VERSION 5.7 ;
  NOWIREEXTENSIONATPIN ON ;
  DIVIDERCHAR "/" ;
  BUSBITCHARS "[]" ;
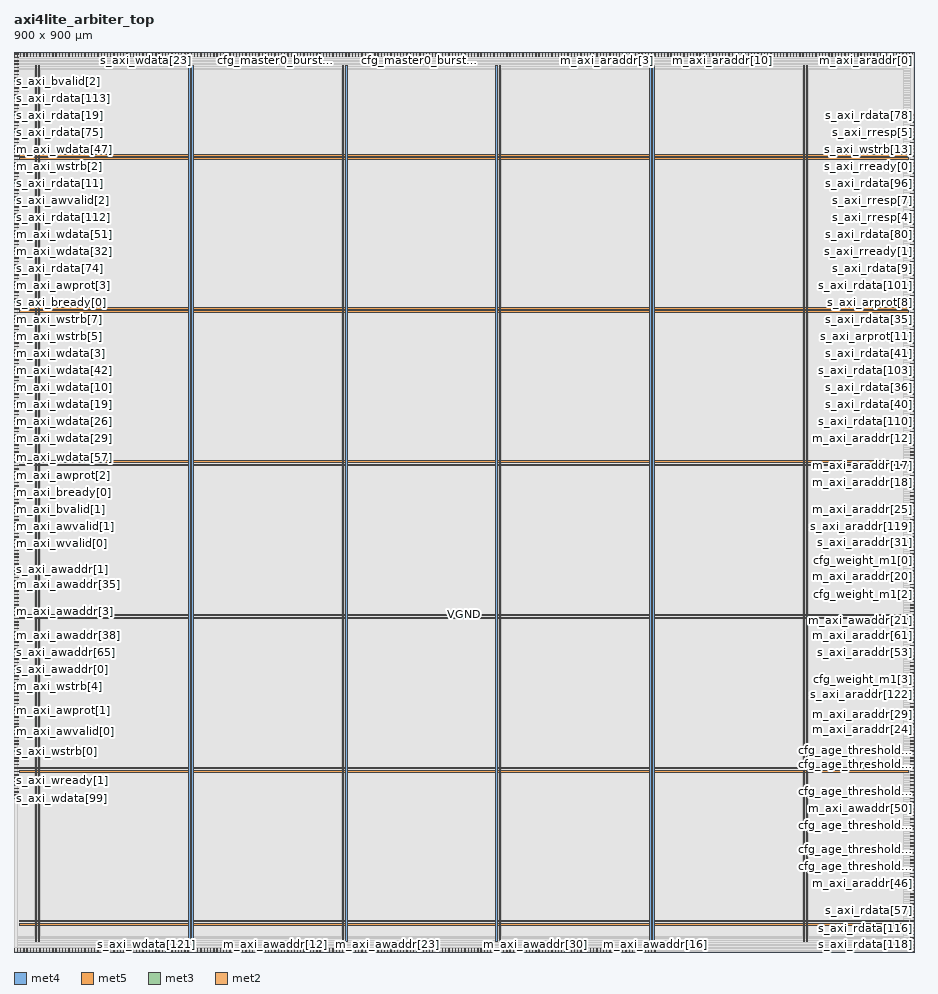
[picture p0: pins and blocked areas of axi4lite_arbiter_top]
MACRO axi4lite_arbiter_top
  CLASS BLOCK ;
  FOREIGN axi4lite_arbiter_top ;
  ORIGIN 0.000 0.000 ;
  SIZE 900.000 BY 900.000 ;
  PIN VGND
    DIRECTION INOUT ;
    USE GROUND ;
    PORT
      LAYER met4 ;
        RECT 24.340 10.640 25.940 886.960 ;
    END
    PORT
      LAYER met4 ;
        RECT 177.940 10.640 179.540 886.960 ;
    END
    PORT
      LAYER met4 ;
        RECT 331.540 10.640 333.140 886.960 ;
    END
    PORT
      LAYER met4 ;
        RECT 485.140 10.640 486.740 886.960 ;
    END
    PORT
      LAYER met4 ;
        RECT 638.740 10.640 640.340 886.960 ;
    END
    PORT
      LAYER met4 ;
        RECT 792.340 10.640 793.940 886.960 ;
    END
    PORT
      LAYER met5 ;
        RECT 5.280 30.030 894.480 31.630 ;
    END
    PORT
      LAYER met5 ;
        RECT 5.280 183.210 894.480 184.810 ;
    END
    PORT
      LAYER met5 ;
        RECT 5.280 336.390 894.480 337.990 ;
    END
    PORT
      LAYER met5 ;
        RECT 5.280 489.570 894.480 491.170 ;
    END
    PORT
      LAYER met5 ;
        RECT 5.280 642.750 894.480 644.350 ;
    END
    PORT
      LAYER met5 ;
        RECT 5.280 795.930 894.480 797.530 ;
    END
  END VGND
  PIN VPWR
    DIRECTION INOUT ;
    USE POWER ;
    PORT
      LAYER met4 ;
        RECT 21.040 10.640 22.640 886.960 ;
    END
    PORT
      LAYER met4 ;
        RECT 174.640 10.640 176.240 886.960 ;
    END
    PORT
      LAYER met4 ;
        RECT 328.240 10.640 329.840 886.960 ;
    END
    PORT
      LAYER met4 ;
        RECT 481.840 10.640 483.440 886.960 ;
    END
    PORT
      LAYER met4 ;
        RECT 635.440 10.640 637.040 886.960 ;
    END
    PORT
      LAYER met4 ;
        RECT 789.040 10.640 790.640 886.960 ;
    END
    PORT
      LAYER met5 ;
        RECT 5.280 26.730 894.480 28.330 ;
    END
    PORT
      LAYER met5 ;
        RECT 5.280 179.910 894.480 181.510 ;
    END
    PORT
      LAYER met5 ;
        RECT 5.280 333.090 894.480 334.690 ;
    END
    PORT
      LAYER met5 ;
        RECT 5.280 486.270 894.480 487.870 ;
    END
    PORT
      LAYER met5 ;
        RECT 5.280 639.450 894.480 641.050 ;
    END
    PORT
      LAYER met5 ;
        RECT 5.280 792.630 894.480 794.230 ;
    END
  END VPWR
  PIN aclk
    DIRECTION INPUT ;
    USE SIGNAL ;
    ANTENNAGATEAREA 0.852000 ;
    ANTENNADIFFAREA 0.869400 ;
    PORT
      LAYER met3 ;
        RECT 896.000 6.840 900.000 7.440 ;
    END
  END aclk
  PIN aresetn
    DIRECTION INPUT ;
    USE SIGNAL ;
    ANTENNAGATEAREA 0.990000 ;
    PORT
      LAYER met3 ;
        RECT 896.000 37.440 900.000 38.040 ;
    END
  END aresetn
  PIN cfg_age_threshold[0]
    DIRECTION INPUT ;
    USE SIGNAL ;
    ANTENNAGATEAREA 0.213000 ;
    PORT
      LAYER met3 ;
        RECT 896.000 85.040 900.000 85.640 ;
    END
  END cfg_age_threshold[0]
  PIN cfg_age_threshold[1]
    DIRECTION INPUT ;
    USE SIGNAL ;
    ANTENNAGATEAREA 0.159000 ;
    PORT
      LAYER met3 ;
        RECT 896.000 187.040 900.000 187.640 ;
    END
  END cfg_age_threshold[1]
  PIN cfg_age_threshold[2]
    DIRECTION INPUT ;
    USE SIGNAL ;
    ANTENNAGATEAREA 0.213000 ;
    PORT
      LAYER met3 ;
        RECT 896.000 193.840 900.000 194.440 ;
    END
  END cfg_age_threshold[2]
  PIN cfg_age_threshold[3]
    DIRECTION INPUT ;
    USE SIGNAL ;
    ANTENNAGATEAREA 0.247500 ;
    PORT
      LAYER met3 ;
        RECT 896.000 125.840 900.000 126.440 ;
    END
  END cfg_age_threshold[3]
  PIN cfg_age_threshold[4]
    DIRECTION INPUT ;
    USE SIGNAL ;
    ANTENNAGATEAREA 0.213000 ;
    PORT
      LAYER met3 ;
        RECT 896.000 159.840 900.000 160.440 ;
    END
  END cfg_age_threshold[4]
  PIN cfg_age_threshold[5]
    DIRECTION INPUT ;
    USE SIGNAL ;
    ANTENNAGATEAREA 0.247500 ;
    PORT
      LAYER met3 ;
        RECT 896.000 102.040 900.000 102.640 ;
    END
  END cfg_age_threshold[5]
  PIN cfg_age_threshold[6]
    DIRECTION INPUT ;
    USE SIGNAL ;
    ANTENNAGATEAREA 0.213000 ;
    PORT
      LAYER met3 ;
        RECT 896.000 173.440 900.000 174.040 ;
    END
  END cfg_age_threshold[6]
  PIN cfg_age_threshold[7]
    DIRECTION INPUT ;
    USE SIGNAL ;
    ANTENNAGATEAREA 0.213000 ;
    PORT
      LAYER met3 ;
        RECT 896.000 234.640 900.000 235.240 ;
    END
  END cfg_age_threshold[7]
  PIN cfg_master0_burst_limit[0]
    DIRECTION INPUT ;
    USE SIGNAL ;
    ANTENNAGATEAREA 0.247500 ;
    PORT
      LAYER met2 ;
        RECT 405.810 896.000 406.090 900.000 ;
    END
  END cfg_master0_burst_limit[0]
  PIN cfg_master0_burst_limit[1]
    DIRECTION INPUT ;
    USE SIGNAL ;
    ANTENNAGATEAREA 0.495000 ;
    PORT
      LAYER met2 ;
        RECT 260.910 896.000 261.190 900.000 ;
    END
  END cfg_master0_burst_limit[1]
  PIN cfg_master0_burst_limit[2]
    DIRECTION INPUT ;
    USE SIGNAL ;
    ANTENNAGATEAREA 0.426000 ;
    PORT
      LAYER met2 ;
        RECT 428.350 896.000 428.630 900.000 ;
    END
  END cfg_master0_burst_limit[2]
  PIN cfg_master0_burst_limit[3]
    DIRECTION INPUT ;
    USE SIGNAL ;
    ANTENNAGATEAREA 0.426000 ;
    PORT
      LAYER met2 ;
        RECT 318.870 896.000 319.150 900.000 ;
    END
  END cfg_master0_burst_limit[3]
  PIN cfg_master0_burst_limit[4]
    DIRECTION INPUT ;
    USE SIGNAL ;
    ANTENNAGATEAREA 0.247500 ;
    PORT
      LAYER met2 ;
        RECT 476.650 896.000 476.930 900.000 ;
    END
  END cfg_master0_burst_limit[4]
  PIN cfg_master0_burst_limit[5]
    DIRECTION INPUT ;
    USE SIGNAL ;
    ANTENNAGATEAREA 0.495000 ;
    PORT
      LAYER met2 ;
        RECT 309.210 896.000 309.490 900.000 ;
    END
  END cfg_master0_burst_limit[5]
  PIN cfg_master0_burst_limit[6]
    DIRECTION INPUT ;
    USE SIGNAL ;
    ANTENNAGATEAREA 0.426000 ;
    PORT
      LAYER met2 ;
        RECT 463.770 896.000 464.050 900.000 ;
    END
  END cfg_master0_burst_limit[6]
  PIN cfg_master0_burst_limit[7]
    DIRECTION INPUT ;
    USE SIGNAL ;
    ANTENNAGATEAREA 0.426000 ;
    PORT
      LAYER met2 ;
        RECT 360.730 896.000 361.010 900.000 ;
    END
  END cfg_master0_burst_limit[7]
  PIN cfg_master0_priority
    DIRECTION INPUT ;
    USE SIGNAL ;
    ANTENNAGATEAREA 0.495000 ;
    PORT
      LAYER met2 ;
        RECT 264.130 896.000 264.410 900.000 ;
    END
  END cfg_master0_priority
  PIN cfg_weight_m0[0]
    DIRECTION INPUT ;
    USE SIGNAL ;
    PORT
      LAYER met2 ;
        RECT 0.090 0.000 0.370 4.000 ;
    END
  END cfg_weight_m0[0]
  PIN cfg_weight_m0[1]
    DIRECTION INPUT ;
    USE SIGNAL ;
    PORT
      LAYER met2 ;
        RECT 3.310 0.000 3.590 4.000 ;
    END
  END cfg_weight_m0[1]
  PIN cfg_weight_m0[2]
    DIRECTION INPUT ;
    USE SIGNAL ;
    PORT
      LAYER met2 ;
        RECT 6.530 0.000 6.810 4.000 ;
    END
  END cfg_weight_m0[2]
  PIN cfg_weight_m0[3]
    DIRECTION INPUT ;
    USE SIGNAL ;
    PORT
      LAYER met2 ;
        RECT 9.750 0.000 10.030 4.000 ;
    END
  END cfg_weight_m0[3]
  PIN cfg_weight_m1[0]
    DIRECTION INPUT ;
    USE SIGNAL ;
    ANTENNAGATEAREA 0.126000 ;
    PORT
      LAYER met3 ;
        RECT 896.000 391.040 900.000 391.640 ;
    END
  END cfg_weight_m1[0]
  PIN cfg_weight_m1[1]
    DIRECTION INPUT ;
    USE SIGNAL ;
    ANTENNAGATEAREA 0.126000 ;
    PORT
      LAYER met3 ;
        RECT 896.000 370.640 900.000 371.240 ;
    END
  END cfg_weight_m1[1]
  PIN cfg_weight_m1[2]
    DIRECTION INPUT ;
    USE SIGNAL ;
    ANTENNAGATEAREA 0.126000 ;
    PORT
      LAYER met3 ;
        RECT 896.000 357.040 900.000 357.640 ;
    END
  END cfg_weight_m1[2]
  PIN cfg_weight_m1[3]
    DIRECTION INPUT ;
    USE SIGNAL ;
    ANTENNAGATEAREA 0.126000 ;
    PORT
      LAYER met3 ;
        RECT 896.000 272.040 900.000 272.640 ;
    END
  END cfg_weight_m1[3]
  PIN cfg_weight_m2[0]
    DIRECTION INPUT ;
    USE SIGNAL ;
    ANTENNAGATEAREA 0.426000 ;
    PORT
      LAYER met2 ;
        RECT 386.490 896.000 386.770 900.000 ;
    END
  END cfg_weight_m2[0]
  PIN cfg_weight_m2[1]
    DIRECTION INPUT ;
    USE SIGNAL ;
    ANTENNAGATEAREA 0.426000 ;
    PORT
      LAYER met2 ;
        RECT 447.670 896.000 447.950 900.000 ;
    END
  END cfg_weight_m2[1]
  PIN cfg_weight_m2[2]
    DIRECTION INPUT ;
    USE SIGNAL ;
    ANTENNAGATEAREA 0.495000 ;
    PORT
      LAYER met2 ;
        RECT 331.750 896.000 332.030 900.000 ;
    END
  END cfg_weight_m2[2]
  PIN cfg_weight_m2[3]
    DIRECTION INPUT ;
    USE SIGNAL ;
    ANTENNAGATEAREA 0.426000 ;
    PORT
      LAYER met2 ;
        RECT 457.330 896.000 457.610 900.000 ;
    END
  END cfg_weight_m2[3]
  PIN cfg_weight_m3[0]
    DIRECTION INPUT ;
    USE SIGNAL ;
    ANTENNAGATEAREA 0.213000 ;
    PORT
      LAYER met3 ;
        RECT 896.000 54.440 900.000 55.040 ;
    END
  END cfg_weight_m3[0]
  PIN cfg_weight_m3[1]
    DIRECTION INPUT ;
    USE SIGNAL ;
    ANTENNAGATEAREA 0.213000 ;
    PORT
      LAYER met3 ;
        RECT 896.000 27.240 900.000 27.840 ;
    END
  END cfg_weight_m3[1]
  PIN cfg_weight_m3[2]
    DIRECTION INPUT ;
    USE SIGNAL ;
    ANTENNAGATEAREA 0.213000 ;
    PORT
      LAYER met3 ;
        RECT 896.000 91.840 900.000 92.440 ;
    END
  END cfg_weight_m3[2]
  PIN cfg_weight_m3[3]
    DIRECTION INPUT ;
    USE SIGNAL ;
    ANTENNAGATEAREA 0.213000 ;
    PORT
      LAYER met3 ;
        RECT 896.000 404.640 900.000 405.240 ;
    END
  END cfg_weight_m3[3]
  PIN m_axi_araddr[0]
    DIRECTION OUTPUT ;
    USE SIGNAL ;
    ANTENNADIFFAREA 0.340600 ;
    PORT
      LAYER met2 ;
        RECT 882.370 896.000 882.650 900.000 ;
    END
  END m_axi_araddr[0]
  PIN m_axi_araddr[10]
    DIRECTION OUTPUT ;
    USE SIGNAL ;
    ANTENNADIFFAREA 0.340600 ;
    PORT
      LAYER met2 ;
        RECT 708.490 896.000 708.770 900.000 ;
    END
  END m_axi_araddr[10]
  PIN m_axi_araddr[11]
    DIRECTION OUTPUT ;
    USE SIGNAL ;
    ANTENNADIFFAREA 0.340600 ;
    PORT
      LAYER met3 ;
        RECT 896.000 360.440 900.000 361.040 ;
    END
  END m_axi_araddr[11]
  PIN m_axi_araddr[12]
    DIRECTION OUTPUT ;
    USE SIGNAL ;
    ANTENNADIFFAREA 0.340600 ;
    PORT
      LAYER met3 ;
        RECT 896.000 513.440 900.000 514.040 ;
    END
  END m_axi_araddr[12]
  PIN m_axi_araddr[13]
    DIRECTION OUTPUT ;
    USE SIGNAL ;
    ANTENNADIFFAREA 0.340600 ;
    PORT
      LAYER met2 ;
        RECT 714.930 896.000 715.210 900.000 ;
    END
  END m_axi_araddr[13]
  PIN m_axi_araddr[14]
    DIRECTION OUTPUT ;
    USE SIGNAL ;
    ANTENNADIFFAREA 0.340600 ;
    PORT
      LAYER met3 ;
        RECT 896.000 397.840 900.000 398.440 ;
    END
  END m_axi_araddr[14]
  PIN m_axi_araddr[15]
    DIRECTION OUTPUT ;
    USE SIGNAL ;
    ANTENNADIFFAREA 0.340600 ;
    PORT
      LAYER met3 ;
        RECT 896.000 170.040 900.000 170.640 ;
    END
  END m_axi_araddr[15]
  PIN m_axi_araddr[16]
    DIRECTION OUTPUT ;
    USE SIGNAL ;
    ANTENNADIFFAREA 0.340600 ;
    PORT
      LAYER met2 ;
        RECT 843.730 896.000 844.010 900.000 ;
    END
  END m_axi_araddr[16]
  PIN m_axi_araddr[17]
    DIRECTION OUTPUT ;
    USE SIGNAL ;
    ANTENNADIFFAREA 0.340600 ;
    PORT
      LAYER met3 ;
        RECT 896.000 486.240 900.000 486.840 ;
    END
  END m_axi_araddr[17]
  PIN m_axi_araddr[18]
    DIRECTION OUTPUT ;
    USE SIGNAL ;
    ANTENNADIFFAREA 0.340600 ;
    PORT
      LAYER met3 ;
        RECT 896.000 469.240 900.000 469.840 ;
    END
  END m_axi_araddr[18]
  PIN m_axi_araddr[19]
    DIRECTION OUTPUT ;
    USE SIGNAL ;
    ANTENNADIFFAREA 0.340600 ;
    PORT
      LAYER met3 ;
        RECT 896.000 268.640 900.000 269.240 ;
    END
  END m_axi_araddr[19]
  PIN m_axi_araddr[1]
    DIRECTION OUTPUT ;
    USE SIGNAL ;
    ANTENNADIFFAREA 0.340600 ;
    PORT
      LAYER met2 ;
        RECT 553.930 896.000 554.210 900.000 ;
    END
  END m_axi_araddr[1]
  PIN m_axi_araddr[20]
    DIRECTION OUTPUT ;
    USE SIGNAL ;
    ANTENNADIFFAREA 0.340600 ;
    PORT
      LAYER met3 ;
        RECT 896.000 367.240 900.000 367.840 ;
    END
  END m_axi_araddr[20]
  PIN m_axi_araddr[21]
    DIRECTION OUTPUT ;
    USE SIGNAL ;
    ANTENNADIFFAREA 0.340600 ;
    PORT
      LAYER met3 ;
        RECT 896.000 462.440 900.000 463.040 ;
    END
  END m_axi_araddr[21]
  PIN m_axi_araddr[22]
    DIRECTION OUTPUT ;
    USE SIGNAL ;
    ANTENNADIFFAREA 0.340600 ;
    PORT
      LAYER met3 ;
        RECT 896.000 455.640 900.000 456.240 ;
    END
  END m_axi_araddr[22]
  PIN m_axi_araddr[23]
    DIRECTION OUTPUT ;
    USE SIGNAL ;
    ANTENNADIFFAREA 0.340600 ;
    PORT
      LAYER met3 ;
        RECT 896.000 132.640 900.000 133.240 ;
    END
  END m_axi_araddr[23]
  PIN m_axi_araddr[24]
    DIRECTION OUTPUT ;
    USE SIGNAL ;
    ANTENNADIFFAREA 0.340600 ;
    PORT
      LAYER met3 ;
        RECT 896.000 214.240 900.000 214.840 ;
    END
  END m_axi_araddr[24]
  PIN m_axi_araddr[25]
    DIRECTION OUTPUT ;
    USE SIGNAL ;
    ANTENNADIFFAREA 0.340600 ;
    PORT
      LAYER met3 ;
        RECT 896.000 442.040 900.000 442.640 ;
    END
  END m_axi_araddr[25]
  PIN m_axi_araddr[26]
    DIRECTION OUTPUT ;
    USE SIGNAL ;
    ANTENNADIFFAREA 0.340600 ;
    PORT
      LAYER met3 ;
        RECT 896.000 129.240 900.000 129.840 ;
    END
  END m_axi_araddr[26]
  PIN m_axi_araddr[27]
    DIRECTION OUTPUT ;
    USE SIGNAL ;
    ANTENNADIFFAREA 0.340600 ;
    PORT
      LAYER met3 ;
        RECT 896.000 319.640 900.000 320.240 ;
    END
  END m_axi_araddr[27]
  PIN m_axi_araddr[28]
    DIRECTION OUTPUT ;
    USE SIGNAL ;
    ANTENNADIFFAREA 0.340600 ;
    PORT
      LAYER met3 ;
        RECT 896.000 476.040 900.000 476.640 ;
    END
  END m_axi_araddr[28]
  PIN m_axi_araddr[29]
    DIRECTION OUTPUT ;
    USE SIGNAL ;
    ANTENNADIFFAREA 0.340600 ;
    PORT
      LAYER met3 ;
        RECT 896.000 244.840 900.000 245.440 ;
    END
  END m_axi_araddr[29]
  PIN m_axi_araddr[2]
    DIRECTION OUTPUT ;
    USE SIGNAL ;
    ANTENNADIFFAREA 0.340600 ;
    PORT
      LAYER met2 ;
        RECT 454.110 896.000 454.390 900.000 ;
    END
  END m_axi_araddr[2]
  PIN m_axi_araddr[30]
    DIRECTION OUTPUT ;
    USE SIGNAL ;
    ANTENNADIFFAREA 0.340600 ;
    PORT
      LAYER met2 ;
        RECT 811.530 896.000 811.810 900.000 ;
    END
  END m_axi_araddr[30]
  PIN m_axi_araddr[31]
    DIRECTION OUTPUT ;
    USE SIGNAL ;
    ANTENNADIFFAREA 0.340600 ;
    PORT
      LAYER met3 ;
        RECT 896.000 394.440 900.000 395.040 ;
    END
  END m_axi_araddr[31]
  PIN m_axi_araddr[32]
    DIRECTION OUTPUT ;
    USE SIGNAL ;
    ANTENNADIFFAREA 0.340600 ;
    PORT
      LAYER met2 ;
        RECT 846.950 896.000 847.230 900.000 ;
    END
  END m_axi_araddr[32]
  PIN m_axi_araddr[33]
    DIRECTION OUTPUT ;
    USE SIGNAL ;
    ANTENNADIFFAREA 0.340600 ;
    PORT
      LAYER met2 ;
        RECT 312.430 896.000 312.710 900.000 ;
    END
  END m_axi_araddr[33]
  PIN m_axi_araddr[34]
    DIRECTION OUTPUT ;
    USE SIGNAL ;
    ANTENNADIFFAREA 0.340600 ;
    PORT
      LAYER met2 ;
        RECT 267.350 896.000 267.630 900.000 ;
    END
  END m_axi_araddr[34]
  PIN m_axi_araddr[35]
    DIRECTION OUTPUT ;
    USE SIGNAL ;
    ANTENNADIFFAREA 0.340600 ;
    PORT
      LAYER met2 ;
        RECT 859.830 896.000 860.110 900.000 ;
    END
  END m_axi_araddr[35]
  PIN m_axi_araddr[36]
    DIRECTION OUTPUT ;
    USE SIGNAL ;
    ANTENNADIFFAREA 0.340600 ;
    PORT
      LAYER met2 ;
        RECT 627.990 896.000 628.270 900.000 ;
    END
  END m_axi_araddr[36]
  PIN m_axi_araddr[37]
    DIRECTION OUTPUT ;
    USE SIGNAL ;
    ANTENNADIFFAREA 0.340600 ;
    PORT
      LAYER met2 ;
        RECT 866.270 896.000 866.550 900.000 ;
    END
  END m_axi_araddr[37]
  PIN m_axi_araddr[38]
    DIRECTION OUTPUT ;
    USE SIGNAL ;
    ANTENNADIFFAREA 0.340600 ;
    PORT
      LAYER met2 ;
        RECT 669.850 896.000 670.130 900.000 ;
    END
  END m_axi_araddr[38]
  PIN m_axi_araddr[39]
    DIRECTION OUTPUT ;
    USE SIGNAL ;
    ANTENNADIFFAREA 0.340600 ;
    PORT
      LAYER met2 ;
        RECT 785.770 896.000 786.050 900.000 ;
    END
  END m_axi_araddr[39]
  PIN m_axi_araddr[3]
    DIRECTION OUTPUT ;
    USE SIGNAL ;
    ANTENNADIFFAREA 0.340600 ;
    PORT
      LAYER met2 ;
        RECT 592.570 896.000 592.850 900.000 ;
    END
  END m_axi_araddr[3]
  PIN m_axi_araddr[40]
    DIRECTION OUTPUT ;
    USE SIGNAL ;
    ANTENNADIFFAREA 0.340600 ;
    PORT
      LAYER met3 ;
        RECT 896.000 663.040 900.000 663.640 ;
    END
  END m_axi_araddr[40]
  PIN m_axi_araddr[41]
    DIRECTION OUTPUT ;
    USE SIGNAL ;
    ANTENNADIFFAREA 0.340600 ;
    PORT
      LAYER met2 ;
        RECT 644.090 896.000 644.370 900.000 ;
    END
  END m_axi_araddr[41]
  PIN m_axi_araddr[42]
    DIRECTION OUTPUT ;
    USE SIGNAL ;
    ANTENNADIFFAREA 0.340600 ;
    PORT
      LAYER met2 ;
        RECT 631.210 896.000 631.490 900.000 ;
    END
  END m_axi_araddr[42]
  PIN m_axi_araddr[43]
    DIRECTION OUTPUT ;
    USE SIGNAL ;
    ANTENNADIFFAREA 0.340600 ;
    PORT
      LAYER met3 ;
        RECT 896.000 88.440 900.000 89.040 ;
    END
  END m_axi_araddr[43]
  PIN m_axi_araddr[44]
    DIRECTION OUTPUT ;
    USE SIGNAL ;
    ANTENNADIFFAREA 0.340600 ;
    PORT
      LAYER met3 ;
        RECT 896.000 23.840 900.000 24.440 ;
    END
  END m_axi_araddr[44]
  PIN m_axi_araddr[45]
    DIRECTION OUTPUT ;
    USE SIGNAL ;
    ANTENNADIFFAREA 0.340600 ;
    PORT
      LAYER met2 ;
        RECT 792.210 896.000 792.490 900.000 ;
    END
  END m_axi_araddr[45]
  PIN m_axi_araddr[46]
    DIRECTION OUTPUT ;
    USE SIGNAL ;
    ANTENNADIFFAREA 0.340600 ;
    PORT
      LAYER met3 ;
        RECT 896.000 68.040 900.000 68.640 ;
    END
  END m_axi_araddr[46]
  PIN m_axi_araddr[47]
    DIRECTION OUTPUT ;
    USE SIGNAL ;
    ANTENNADIFFAREA 0.340600 ;
    PORT
      LAYER met3 ;
        RECT 896.000 190.440 900.000 191.040 ;
    END
  END m_axi_araddr[47]
  PIN m_axi_araddr[48]
    DIRECTION OUTPUT ;
    USE SIGNAL ;
    ANTENNADIFFAREA 0.340600 ;
    PORT
      LAYER met2 ;
        RECT 747.130 896.000 747.410 900.000 ;
    END
  END m_axi_araddr[48]
  PIN m_axi_araddr[49]
    DIRECTION OUTPUT ;
    USE SIGNAL ;
    ANTENNADIFFAREA 0.340600 ;
    PORT
      LAYER met3 ;
        RECT 896.000 489.640 900.000 490.240 ;
    END
  END m_axi_araddr[49]
  PIN m_axi_araddr[4]
    DIRECTION OUTPUT ;
    USE SIGNAL ;
    ANTENNADIFFAREA 0.340600 ;
    PORT
      LAYER met2 ;
        RECT 624.770 896.000 625.050 900.000 ;
    END
  END m_axi_araddr[4]
  PIN m_axi_araddr[50]
    DIRECTION OUTPUT ;
    USE SIGNAL ;
    ANTENNADIFFAREA 0.340600 ;
    PORT
      LAYER met3 ;
        RECT 896.000 472.640 900.000 473.240 ;
    END
  END m_axi_araddr[50]
  PIN m_axi_araddr[51]
    DIRECTION OUTPUT ;
    USE SIGNAL ;
    ANTENNADIFFAREA 0.340600 ;
    PORT
      LAYER met3 ;
        RECT 896.000 479.440 900.000 480.040 ;
    END
  END m_axi_araddr[51]
  PIN m_axi_araddr[52]
    DIRECTION OUTPUT ;
    USE SIGNAL ;
    ANTENNADIFFAREA 0.340600 ;
    PORT
      LAYER met3 ;
        RECT 896.000 448.840 900.000 449.440 ;
    END
  END m_axi_araddr[52]
  PIN m_axi_araddr[53]
    DIRECTION OUTPUT ;
    USE SIGNAL ;
    ANTENNADIFFAREA 0.340600 ;
    PORT
      LAYER met3 ;
        RECT 896.000 459.040 900.000 459.640 ;
    END
  END m_axi_araddr[53]
  PIN m_axi_araddr[54]
    DIRECTION OUTPUT ;
    USE SIGNAL ;
    ANTENNADIFFAREA 0.340600 ;
    PORT
      LAYER met3 ;
        RECT 896.000 465.840 900.000 466.440 ;
    END
  END m_axi_araddr[54]
  PIN m_axi_araddr[55]
    DIRECTION OUTPUT ;
    USE SIGNAL ;
    ANTENNADIFFAREA 0.340600 ;
    PORT
      LAYER met3 ;
        RECT 896.000 197.240 900.000 197.840 ;
    END
  END m_axi_araddr[55]
  PIN m_axi_araddr[56]
    DIRECTION OUTPUT ;
    USE SIGNAL ;
    ANTENNADIFFAREA 0.340600 ;
    PORT
      LAYER met3 ;
        RECT 896.000 452.240 900.000 452.840 ;
    END
  END m_axi_araddr[56]
  PIN m_axi_araddr[57]
    DIRECTION OUTPUT ;
    USE SIGNAL ;
    ANTENNADIFFAREA 0.340600 ;
    PORT
      LAYER met3 ;
        RECT 896.000 445.440 900.000 446.040 ;
    END
  END m_axi_araddr[57]
  PIN m_axi_araddr[58]
    DIRECTION OUTPUT ;
    USE SIGNAL ;
    ANTENNADIFFAREA 0.340600 ;
    PORT
      LAYER met3 ;
        RECT 896.000 261.840 900.000 262.440 ;
    END
  END m_axi_araddr[58]
  PIN m_axi_araddr[59]
    DIRECTION OUTPUT ;
    USE SIGNAL ;
    ANTENNADIFFAREA 0.340600 ;
    PORT
      LAYER met3 ;
        RECT 896.000 295.840 900.000 296.440 ;
    END
  END m_axi_araddr[59]
  PIN m_axi_araddr[5]
    DIRECTION OUTPUT ;
    USE SIGNAL ;
    ANTENNADIFFAREA 0.340600 ;
    PORT
      LAYER met2 ;
        RECT 737.470 896.000 737.750 900.000 ;
    END
  END m_axi_araddr[5]
  PIN m_axi_araddr[60]
    DIRECTION OUTPUT ;
    USE SIGNAL ;
    ANTENNADIFFAREA 0.340600 ;
    PORT
      LAYER met3 ;
        RECT 896.000 482.840 900.000 483.440 ;
    END
  END m_axi_araddr[60]
  PIN m_axi_araddr[61]
    DIRECTION OUTPUT ;
    USE SIGNAL ;
    ANTENNADIFFAREA 0.340600 ;
    PORT
      LAYER met3 ;
        RECT 896.000 316.240 900.000 316.840 ;
    END
  END m_axi_araddr[61]
  PIN m_axi_araddr[62]
    DIRECTION OUTPUT ;
    USE SIGNAL ;
    ANTENNADIFFAREA 0.340600 ;
    PORT
      LAYER met2 ;
        RECT 834.070 896.000 834.350 900.000 ;
    END
  END m_axi_araddr[62]
  PIN m_axi_araddr[63]
    DIRECTION OUTPUT ;
    USE SIGNAL ;
    ANTENNADIFFAREA 0.340600 ;
    PORT
      LAYER met3 ;
        RECT 896.000 258.440 900.000 259.040 ;
    END
  END m_axi_araddr[63]
  PIN m_axi_araddr[6]
    DIRECTION OUTPUT ;
    USE SIGNAL ;
    ANTENNADIFFAREA 0.340600 ;
    PORT
      LAYER met2 ;
        RECT 621.550 896.000 621.830 900.000 ;
    END
  END m_axi_araddr[6]
  PIN m_axi_araddr[7]
    DIRECTION OUTPUT ;
    USE SIGNAL ;
    ANTENNADIFFAREA 0.340600 ;
    PORT
      LAYER met2 ;
        RECT 650.530 896.000 650.810 900.000 ;
    END
  END m_axi_araddr[7]
  PIN m_axi_araddr[8]
    DIRECTION OUTPUT ;
    USE SIGNAL ;
    ANTENNADIFFAREA 0.340600 ;
    PORT
      LAYER met3 ;
        RECT 896.000 629.040 900.000 629.640 ;
    END
  END m_axi_araddr[8]
  PIN m_axi_araddr[9]
    DIRECTION OUTPUT ;
    USE SIGNAL ;
    ANTENNADIFFAREA 0.340600 ;
    PORT
      LAYER met2 ;
        RECT 808.310 896.000 808.590 900.000 ;
    END
  END m_axi_araddr[9]
  PIN m_axi_arprot[0]
    DIRECTION OUTPUT ;
    USE SIGNAL ;
    ANTENNADIFFAREA 0.340600 ;
    PORT
      LAYER met2 ;
        RECT 615.110 896.000 615.390 900.000 ;
    END
  END m_axi_arprot[0]
  PIN m_axi_arprot[1]
    DIRECTION OUTPUT ;
    USE SIGNAL ;
    ANTENNADIFFAREA 0.340600 ;
    PORT
      LAYER met2 ;
        RECT 776.110 896.000 776.390 900.000 ;
    END
  END m_axi_arprot[1]
  PIN m_axi_arprot[2]
    DIRECTION OUTPUT ;
    USE SIGNAL ;
    ANTENNADIFFAREA 0.340600 ;
    PORT
      LAYER met2 ;
        RECT 579.690 896.000 579.970 900.000 ;
    END
  END m_axi_arprot[2]
  PIN m_axi_arprot[3]
    DIRECTION OUTPUT ;
    USE SIGNAL ;
    ANTENNADIFFAREA 0.340600 ;
    PORT
      LAYER met2 ;
        RECT 611.890 896.000 612.170 900.000 ;
    END
  END m_axi_arprot[3]
  PIN m_axi_arprot[4]
    DIRECTION OUTPUT ;
    USE SIGNAL ;
    ANTENNADIFFAREA 0.340600 ;
    PORT
      LAYER met2 ;
        RECT 602.230 896.000 602.510 900.000 ;
    END
  END m_axi_arprot[4]
  PIN m_axi_arprot[5]
    DIRECTION OUTPUT ;
    USE SIGNAL ;
    ANTENNADIFFAREA 0.340600 ;
    PORT
      LAYER met2 ;
        RECT 570.030 896.000 570.310 900.000 ;
    END
  END m_axi_arprot[5]
  PIN m_axi_arready[0]
    DIRECTION INPUT ;
    USE SIGNAL ;
    ANTENNAGATEAREA 0.196500 ;
    PORT
      LAYER met2 ;
        RECT 550.710 896.000 550.990 900.000 ;
    END
  END m_axi_arready[0]
  PIN m_axi_arready[1]
    DIRECTION INPUT ;
    USE SIGNAL ;
    ANTENNAGATEAREA 0.196500 ;
    PORT
      LAYER met2 ;
        RECT 489.530 896.000 489.810 900.000 ;
    END
  END m_axi_arready[1]
  PIN m_axi_arvalid[0]
    DIRECTION OUTPUT ;
    USE SIGNAL ;
    ANTENNADIFFAREA 0.340600 ;
    PORT
      LAYER met2 ;
        RECT 560.370 896.000 560.650 900.000 ;
    END
  END m_axi_arvalid[0]
  PIN m_axi_arvalid[1]
    DIRECTION OUTPUT ;
    USE SIGNAL ;
    ANTENNADIFFAREA 0.340600 ;
    PORT
      LAYER met2 ;
        RECT 508.850 896.000 509.130 900.000 ;
    END
  END m_axi_arvalid[1]
  PIN m_axi_awaddr[0]
    DIRECTION OUTPUT ;
    USE SIGNAL ;
    ANTENNADIFFAREA 0.340600 ;
    PORT
      LAYER met2 ;
        RECT 12.970 0.000 13.250 4.000 ;
    END
  END m_axi_awaddr[0]
  PIN m_axi_awaddr[10]
    DIRECTION OUTPUT ;
    USE SIGNAL ;
    ANTENNADIFFAREA 0.340600 ;
    PORT
      LAYER met2 ;
        RECT 186.850 0.000 187.130 4.000 ;
    END
  END m_axi_awaddr[10]
  PIN m_axi_awaddr[11]
    DIRECTION OUTPUT ;
    USE SIGNAL ;
    ANTENNADIFFAREA 0.340600 ;
    PORT
      LAYER met2 ;
        RECT 257.690 0.000 257.970 4.000 ;
    END
  END m_axi_awaddr[11]
  PIN m_axi_awaddr[12]
    DIRECTION OUTPUT ;
    USE SIGNAL ;
    ANTENNADIFFAREA 0.340600 ;
    PORT
      LAYER met2 ;
        RECT 260.910 0.000 261.190 4.000 ;
    END
  END m_axi_awaddr[12]
  PIN m_axi_awaddr[13]
    DIRECTION OUTPUT ;
    USE SIGNAL ;
    ANTENNADIFFAREA 0.340600 ;
    PORT
      LAYER met2 ;
        RECT 161.090 0.000 161.370 4.000 ;
    END
  END m_axi_awaddr[13]
  PIN m_axi_awaddr[14]
    DIRECTION OUTPUT ;
    USE SIGNAL ;
    ANTENNADIFFAREA 0.340600 ;
    PORT
      LAYER met2 ;
        RECT 244.810 0.000 245.090 4.000 ;
    END
  END m_axi_awaddr[14]
  PIN m_axi_awaddr[15]
    DIRECTION OUTPUT ;
    USE SIGNAL ;
    ANTENNADIFFAREA 0.340600 ;
    PORT
      LAYER met2 ;
        RECT 206.170 0.000 206.450 4.000 ;
    END
  END m_axi_awaddr[15]
  PIN m_axi_awaddr[16]
    DIRECTION OUTPUT ;
    USE SIGNAL ;
    ANTENNADIFFAREA 0.340600 ;
    PORT
      LAYER met2 ;
        RECT 640.870 0.000 641.150 4.000 ;
    END
  END m_axi_awaddr[16]
  PIN m_axi_awaddr[17]
    DIRECTION OUTPUT ;
    USE SIGNAL ;
    ANTENNADIFFAREA 0.340600 ;
    PORT
      LAYER met2 ;
        RECT 589.350 0.000 589.630 4.000 ;
    END
  END m_axi_awaddr[17]
  PIN m_axi_awaddr[18]
    DIRECTION OUTPUT ;
    USE SIGNAL ;
    ANTENNADIFFAREA 0.340600 ;
    PORT
      LAYER met3 ;
        RECT 896.000 326.440 900.000 327.040 ;
    END
  END m_axi_awaddr[18]
  PIN m_axi_awaddr[19]
    DIRECTION OUTPUT ;
    USE SIGNAL ;
    ANTENNADIFFAREA 0.340600 ;
    PORT
      LAYER met2 ;
        RECT 16.190 0.000 16.470 4.000 ;
    END
  END m_axi_awaddr[19]
  PIN m_axi_awaddr[1]
    DIRECTION OUTPUT ;
    USE SIGNAL ;
    ANTENNADIFFAREA 0.340600 ;
    PORT
      LAYER met2 ;
        RECT 144.990 0.000 145.270 4.000 ;
    END
  END m_axi_awaddr[1]
  PIN m_axi_awaddr[20]
    DIRECTION OUTPUT ;
    USE SIGNAL ;
    ANTENNADIFFAREA 0.340600 ;
    PORT
      LAYER met2 ;
        RECT 570.030 0.000 570.310 4.000 ;
    END
  END m_axi_awaddr[20]
  PIN m_axi_awaddr[21]
    DIRECTION OUTPUT ;
    USE SIGNAL ;
    ANTENNADIFFAREA 0.340600 ;
    PORT
      LAYER met3 ;
        RECT 896.000 323.040 900.000 323.640 ;
    END
  END m_axi_awaddr[21]
  PIN m_axi_awaddr[22]
    DIRECTION OUTPUT ;
    USE SIGNAL ;
    ANTENNADIFFAREA 0.340600 ;
    PORT
      LAYER met2 ;
        RECT 547.490 0.000 547.770 4.000 ;
    END
  END m_axi_awaddr[22]
  PIN m_axi_awaddr[23]
    DIRECTION OUTPUT ;
    USE SIGNAL ;
    ANTENNADIFFAREA 0.340600 ;
    PORT
      LAYER met2 ;
        RECT 373.610 0.000 373.890 4.000 ;
    END
  END m_axi_awaddr[23]
  PIN m_axi_awaddr[24]
    DIRECTION OUTPUT ;
    USE SIGNAL ;
    ANTENNADIFFAREA 0.340600 ;
    PORT
      LAYER met2 ;
        RECT 576.470 0.000 576.750 4.000 ;
    END
  END m_axi_awaddr[24]
  PIN m_axi_awaddr[25]
    DIRECTION OUTPUT ;
    USE SIGNAL ;
    ANTENNADIFFAREA 0.340600 ;
    PORT
      LAYER met2 ;
        RECT 454.110 0.000 454.390 4.000 ;
    END
  END m_axi_awaddr[25]
  PIN m_axi_awaddr[26]
    DIRECTION OUTPUT ;
    USE SIGNAL ;
    ANTENNADIFFAREA 0.340600 ;
    PORT
      LAYER met3 ;
        RECT 896.000 119.040 900.000 119.640 ;
    END
  END m_axi_awaddr[26]
  PIN m_axi_awaddr[27]
    DIRECTION OUTPUT ;
    USE SIGNAL ;
    ANTENNADIFFAREA 0.340600 ;
    PORT
      LAYER met3 ;
        RECT 896.000 44.240 900.000 44.840 ;
    END
  END m_axi_awaddr[27]
  PIN m_axi_awaddr[28]
    DIRECTION OUTPUT ;
    USE SIGNAL ;
    ANTENNADIFFAREA 0.340600 ;
    PORT
      LAYER met2 ;
        RECT 557.150 0.000 557.430 4.000 ;
    END
  END m_axi_awaddr[28]
  PIN m_axi_awaddr[29]
    DIRECTION OUTPUT ;
    USE SIGNAL ;
    ANTENNADIFFAREA 0.340600 ;
    PORT
      LAYER met2 ;
        RECT 586.130 0.000 586.410 4.000 ;
    END
  END m_axi_awaddr[29]
  PIN m_axi_awaddr[2]
    DIRECTION OUTPUT ;
    USE SIGNAL ;
    ANTENNADIFFAREA 0.340600 ;
    PORT
      LAYER met3 ;
        RECT 0.000 302.640 4.000 303.240 ;
    END
  END m_axi_awaddr[2]
  PIN m_axi_awaddr[30]
    DIRECTION OUTPUT ;
    USE SIGNAL ;
    ANTENNADIFFAREA 0.340600 ;
    PORT
      LAYER met2 ;
        RECT 521.730 0.000 522.010 4.000 ;
    END
  END m_axi_awaddr[30]
  PIN m_axi_awaddr[31]
    DIRECTION OUTPUT ;
    USE SIGNAL ;
    ANTENNADIFFAREA 0.340600 ;
    PORT
      LAYER met2 ;
        RECT 605.450 0.000 605.730 4.000 ;
    END
  END m_axi_awaddr[31]
  PIN m_axi_awaddr[32]
    DIRECTION OUTPUT ;
    USE SIGNAL ;
    ANTENNADIFFAREA 0.340600 ;
    PORT
      LAYER met2 ;
        RECT 183.630 0.000 183.910 4.000 ;
    END
  END m_axi_awaddr[32]
  PIN m_axi_awaddr[33]
    DIRECTION OUTPUT ;
    USE SIGNAL ;
    ANTENNADIFFAREA 0.340600 ;
    PORT
      LAYER met2 ;
        RECT 141.770 0.000 142.050 4.000 ;
    END
  END m_axi_awaddr[33]
  PIN m_axi_awaddr[34]
    DIRECTION OUTPUT ;
    USE SIGNAL ;
    ANTENNADIFFAREA 0.340600 ;
    PORT
      LAYER met3 ;
        RECT 0.000 411.440 4.000 412.040 ;
    END
  END m_axi_awaddr[34]
  PIN m_axi_awaddr[35]
    DIRECTION OUTPUT ;
    USE SIGNAL ;
    ANTENNADIFFAREA 0.340600 ;
    PORT
      LAYER met3 ;
        RECT 0.000 367.240 4.000 367.840 ;
    END
  END m_axi_awaddr[35]
  PIN m_axi_awaddr[36]
    DIRECTION OUTPUT ;
    USE SIGNAL ;
    ANTENNADIFFAREA 0.340600 ;
    PORT
      LAYER met2 ;
        RECT 61.270 0.000 61.550 4.000 ;
    END
  END m_axi_awaddr[36]
  PIN m_axi_awaddr[37]
    DIRECTION OUTPUT ;
    USE SIGNAL ;
    ANTENNADIFFAREA 0.340600 ;
    PORT
      LAYER met3 ;
        RECT 0.000 251.640 4.000 252.240 ;
    END
  END m_axi_awaddr[37]
  PIN m_axi_awaddr[38]
    DIRECTION OUTPUT ;
    USE SIGNAL ;
    ANTENNADIFFAREA 0.340600 ;
    PORT
      LAYER met3 ;
        RECT 0.000 316.240 4.000 316.840 ;
    END
  END m_axi_awaddr[38]
  PIN m_axi_awaddr[39]
    DIRECTION OUTPUT ;
    USE SIGNAL ;
    ANTENNADIFFAREA 0.340600 ;
    PORT
      LAYER met2 ;
        RECT 299.550 0.000 299.830 4.000 ;
    END
  END m_axi_awaddr[39]
  PIN m_axi_awaddr[3]
    DIRECTION OUTPUT ;
    USE SIGNAL ;
    ANTENNADIFFAREA 0.340600 ;
    PORT
      LAYER met3 ;
        RECT 0.000 340.040 4.000 340.640 ;
    END
  END m_axi_awaddr[3]
  PIN m_axi_awaddr[40]
    DIRECTION OUTPUT ;
    USE SIGNAL ;
    ANTENNADIFFAREA 0.340600 ;
    PORT
      LAYER met2 ;
        RECT 48.390 0.000 48.670 4.000 ;
    END
  END m_axi_awaddr[40]
  PIN m_axi_awaddr[41]
    DIRECTION OUTPUT ;
    USE SIGNAL ;
    ANTENNADIFFAREA 0.340600 ;
    PORT
      LAYER met2 ;
        RECT 173.970 0.000 174.250 4.000 ;
    END
  END m_axi_awaddr[41]
  PIN m_axi_awaddr[42]
    DIRECTION OUTPUT ;
    USE SIGNAL ;
    ANTENNADIFFAREA 0.340600 ;
    PORT
      LAYER met2 ;
        RECT 280.230 0.000 280.510 4.000 ;
    END
  END m_axi_awaddr[42]
  PIN m_axi_awaddr[43]
    DIRECTION OUTPUT ;
    USE SIGNAL ;
    ANTENNADIFFAREA 0.340600 ;
    PORT
      LAYER met2 ;
        RECT 264.130 0.000 264.410 4.000 ;
    END
  END m_axi_awaddr[43]
  PIN m_axi_awaddr[44]
    DIRECTION OUTPUT ;
    USE SIGNAL ;
    ANTENNADIFFAREA 0.340600 ;
    PORT
      LAYER met2 ;
        RECT 267.350 0.000 267.630 4.000 ;
    END
  END m_axi_awaddr[44]
  PIN m_axi_awaddr[45]
    DIRECTION OUTPUT ;
    USE SIGNAL ;
    ANTENNADIFFAREA 0.340600 ;
    PORT
      LAYER met2 ;
        RECT 157.870 0.000 158.150 4.000 ;
    END
  END m_axi_awaddr[45]
  PIN m_axi_awaddr[46]
    DIRECTION OUTPUT ;
    USE SIGNAL ;
    ANTENNADIFFAREA 0.340600 ;
    PORT
      LAYER met2 ;
        RECT 309.210 0.000 309.490 4.000 ;
    END
  END m_axi_awaddr[46]
  PIN m_axi_awaddr[47]
    DIRECTION OUTPUT ;
    USE SIGNAL ;
    ANTENNADIFFAREA 0.340600 ;
    PORT
      LAYER met2 ;
        RECT 202.950 0.000 203.230 4.000 ;
    END
  END m_axi_awaddr[47]
  PIN m_axi_awaddr[48]
    DIRECTION OUTPUT ;
    USE SIGNAL ;
    ANTENNADIFFAREA 0.340600 ;
    PORT
      LAYER met2 ;
        RECT 537.830 0.000 538.110 4.000 ;
    END
  END m_axi_awaddr[48]
  PIN m_axi_awaddr[49]
    DIRECTION OUTPUT ;
    USE SIGNAL ;
    ANTENNADIFFAREA 0.340600 ;
    PORT
      LAYER met2 ;
        RECT 409.030 0.000 409.310 4.000 ;
    END
  END m_axi_awaddr[49]
  PIN m_axi_awaddr[4]
    DIRECTION OUTPUT ;
    USE SIGNAL ;
    ANTENNADIFFAREA 0.340600 ;
    PORT
      LAYER met2 ;
        RECT 51.610 0.000 51.890 4.000 ;
    END
  END m_axi_awaddr[4]
  PIN m_axi_awaddr[50]
    DIRECTION OUTPUT ;
    USE SIGNAL ;
    ANTENNADIFFAREA 0.340600 ;
    PORT
      LAYER met3 ;
        RECT 896.000 142.840 900.000 143.440 ;
    END
  END m_axi_awaddr[50]
  PIN m_axi_awaddr[51]
    DIRECTION OUTPUT ;
    USE SIGNAL ;
    ANTENNADIFFAREA 0.340600 ;
    PORT
      LAYER met2 ;
        RECT 32.290 0.000 32.570 4.000 ;
    END
  END m_axi_awaddr[51]
  PIN m_axi_awaddr[52]
    DIRECTION OUTPUT ;
    USE SIGNAL ;
    ANTENNADIFFAREA 0.340600 ;
    PORT
      LAYER met2 ;
        RECT 380.050 0.000 380.330 4.000 ;
    END
  END m_axi_awaddr[52]
  PIN m_axi_awaddr[53]
    DIRECTION OUTPUT ;
    USE SIGNAL ;
    ANTENNADIFFAREA 0.340600 ;
    PORT
      LAYER met3 ;
        RECT 896.000 302.640 900.000 303.240 ;
    END
  END m_axi_awaddr[53]
  PIN m_axi_awaddr[54]
    DIRECTION OUTPUT ;
    USE SIGNAL ;
    ANTENNADIFFAREA 0.340600 ;
    PORT
      LAYER met2 ;
        RECT 528.170 0.000 528.450 4.000 ;
    END
  END m_axi_awaddr[54]
  PIN m_axi_awaddr[55]
    DIRECTION OUTPUT ;
    USE SIGNAL ;
    ANTENNADIFFAREA 0.340600 ;
    PORT
      LAYER met2 ;
        RECT 25.850 0.000 26.130 4.000 ;
    END
  END m_axi_awaddr[55]
  PIN m_axi_awaddr[56]
    DIRECTION OUTPUT ;
    USE SIGNAL ;
    ANTENNADIFFAREA 0.340600 ;
    PORT
      LAYER met2 ;
        RECT 599.010 0.000 599.290 4.000 ;
    END
  END m_axi_awaddr[56]
  PIN m_axi_awaddr[57]
    DIRECTION OUTPUT ;
    USE SIGNAL ;
    ANTENNADIFFAREA 0.340600 ;
    PORT
      LAYER met2 ;
        RECT 505.630 0.000 505.910 4.000 ;
    END
  END m_axi_awaddr[57]
  PIN m_axi_awaddr[58]
    DIRECTION OUTPUT ;
    USE SIGNAL ;
    ANTENNADIFFAREA 0.340600 ;
    PORT
      LAYER met2 ;
        RECT 544.270 0.000 544.550 4.000 ;
    END
  END m_axi_awaddr[58]
  PIN m_axi_awaddr[59]
    DIRECTION OUTPUT ;
    USE SIGNAL ;
    ANTENNADIFFAREA 0.340600 ;
    PORT
      LAYER met3 ;
        RECT 896.000 47.640 900.000 48.240 ;
    END
  END m_axi_awaddr[59]
  PIN m_axi_awaddr[5]
    DIRECTION OUTPUT ;
    USE SIGNAL ;
    ANTENNADIFFAREA 0.340600 ;
    PORT
      LAYER met3 ;
        RECT 0.000 323.040 4.000 323.640 ;
    END
  END m_axi_awaddr[5]
  PIN m_axi_awaddr[60]
    DIRECTION OUTPUT ;
    USE SIGNAL ;
    ANTENNADIFFAREA 0.340600 ;
    PORT
      LAYER met2 ;
        RECT 611.890 0.000 612.170 4.000 ;
    END
  END m_axi_awaddr[60]
  PIN m_axi_awaddr[61]
    DIRECTION OUTPUT ;
    USE SIGNAL ;
    ANTENNADIFFAREA 0.340600 ;
    PORT
      LAYER met2 ;
        RECT 624.770 0.000 625.050 4.000 ;
    END
  END m_axi_awaddr[61]
  PIN m_axi_awaddr[62]
    DIRECTION OUTPUT ;
    USE SIGNAL ;
    ANTENNADIFFAREA 0.340600 ;
    PORT
      LAYER met2 ;
        RECT 470.210 0.000 470.490 4.000 ;
    END
  END m_axi_awaddr[62]
  PIN m_axi_awaddr[63]
    DIRECTION OUTPUT ;
    USE SIGNAL ;
    ANTENNADIFFAREA 0.340600 ;
    PORT
      LAYER met2 ;
        RECT 631.210 0.000 631.490 4.000 ;
    END
  END m_axi_awaddr[63]
  PIN m_axi_awaddr[6]
    DIRECTION OUTPUT ;
    USE SIGNAL ;
    ANTENNADIFFAREA 0.340600 ;
    PORT
      LAYER met3 ;
        RECT 0.000 357.040 4.000 357.640 ;
    END
  END m_axi_awaddr[6]
  PIN m_axi_awaddr[7]
    DIRECTION OUTPUT ;
    USE SIGNAL ;
    ANTENNADIFFAREA 0.340600 ;
    PORT
      LAYER met2 ;
        RECT 248.030 0.000 248.310 4.000 ;
    END
  END m_axi_awaddr[7]
  PIN m_axi_awaddr[8]
    DIRECTION OUTPUT ;
    USE SIGNAL ;
    ANTENNADIFFAREA 0.340600 ;
    PORT
      LAYER met2 ;
        RECT 425.130 0.000 425.410 4.000 ;
    END
  END m_axi_awaddr[8]
  PIN m_axi_awaddr[9]
    DIRECTION OUTPUT ;
    USE SIGNAL ;
    ANTENNADIFFAREA 0.340600 ;
    PORT
      LAYER met2 ;
        RECT 180.410 0.000 180.690 4.000 ;
    END
  END m_axi_awaddr[9]
  PIN m_axi_awprot[0]
    DIRECTION OUTPUT ;
    USE SIGNAL ;
    ANTENNADIFFAREA 0.340600 ;
    PORT
      LAYER met3 ;
        RECT 0.000 663.040 4.000 663.640 ;
    END
  END m_axi_awprot[0]
  PIN m_axi_awprot[1]
    DIRECTION OUTPUT ;
    USE SIGNAL ;
    ANTENNADIFFAREA 0.340600 ;
    PORT
      LAYER met3 ;
        RECT 0.000 241.440 4.000 242.040 ;
    END
  END m_axi_awprot[1]
  PIN m_axi_awprot[2]
    DIRECTION OUTPUT ;
    USE SIGNAL ;
    ANTENNADIFFAREA 0.340600 ;
    PORT
      LAYER met3 ;
        RECT 0.000 476.040 4.000 476.640 ;
    END
  END m_axi_awprot[2]
  PIN m_axi_awprot[3]
    DIRECTION OUTPUT ;
    USE SIGNAL ;
    ANTENNADIFFAREA 0.340600 ;
    PORT
      LAYER met3 ;
        RECT 0.000 666.440 4.000 667.040 ;
    END
  END m_axi_awprot[3]
  PIN m_axi_awprot[4]
    DIRECTION OUTPUT ;
    USE SIGNAL ;
    ANTENNADIFFAREA 0.340600 ;
    PORT
      LAYER met3 ;
        RECT 0.000 258.440 4.000 259.040 ;
    END
  END m_axi_awprot[4]
  PIN m_axi_awprot[5]
    DIRECTION OUTPUT ;
    USE SIGNAL ;
    ANTENNADIFFAREA 0.340600 ;
    PORT
      LAYER met3 ;
        RECT 0.000 533.840 4.000 534.440 ;
    END
  END m_axi_awprot[5]
  PIN m_axi_awready[0]
    DIRECTION INPUT ;
    USE SIGNAL ;
    ANTENNAGATEAREA 0.196500 ;
    PORT
      LAYER met3 ;
        RECT 0.000 431.840 4.000 432.440 ;
    END
  END m_axi_awready[0]
  PIN m_axi_awready[1]
    DIRECTION INPUT ;
    USE SIGNAL ;
    ANTENNAGATEAREA 0.126000 ;
    PORT
      LAYER met3 ;
        RECT 0.000 234.640 4.000 235.240 ;
    END
  END m_axi_awready[1]
  PIN m_axi_awvalid[0]
    DIRECTION OUTPUT ;
    USE SIGNAL ;
    ANTENNADIFFAREA 0.340600 ;
    PORT
      LAYER met3 ;
        RECT 0.000 227.840 4.000 228.440 ;
    END
  END m_axi_awvalid[0]
  PIN m_axi_awvalid[1]
    DIRECTION OUTPUT ;
    USE SIGNAL ;
    ANTENNADIFFAREA 0.340600 ;
    PORT
      LAYER met3 ;
        RECT 0.000 425.040 4.000 425.640 ;
    END
  END m_axi_awvalid[1]
  PIN m_axi_bready[0]
    DIRECTION OUTPUT ;
    USE SIGNAL ;
    ANTENNADIFFAREA 0.340600 ;
    PORT
      LAYER met3 ;
        RECT 0.000 459.040 4.000 459.640 ;
    END
  END m_axi_bready[0]
  PIN m_axi_bready[1]
    DIRECTION OUTPUT ;
    USE SIGNAL ;
    ANTENNADIFFAREA 0.340600 ;
    PORT
      LAYER met3 ;
        RECT 0.000 455.640 4.000 456.240 ;
    END
  END m_axi_bready[1]
  PIN m_axi_bresp[0]
    DIRECTION INPUT ;
    USE SIGNAL ;
    ANTENNAGATEAREA 0.196500 ;
    PORT
      LAYER met3 ;
        RECT 0.000 312.840 4.000 313.440 ;
    END
  END m_axi_bresp[0]
  PIN m_axi_bresp[1]
    DIRECTION INPUT ;
    USE SIGNAL ;
    ANTENNAGATEAREA 0.196500 ;
    PORT
      LAYER met3 ;
        RECT 0.000 285.640 4.000 286.240 ;
    END
  END m_axi_bresp[1]
  PIN m_axi_bresp[2]
    DIRECTION INPUT ;
    USE SIGNAL ;
    ANTENNAGATEAREA 0.196500 ;
    PORT
      LAYER met3 ;
        RECT 0.000 387.640 4.000 388.240 ;
    END
  END m_axi_bresp[2]
  PIN m_axi_bresp[3]
    DIRECTION INPUT ;
    USE SIGNAL ;
    ANTENNAGATEAREA 0.196500 ;
    PORT
      LAYER met3 ;
        RECT 0.000 275.440 4.000 276.040 ;
    END
  END m_axi_bresp[3]
  PIN m_axi_bvalid[0]
    DIRECTION INPUT ;
    USE SIGNAL ;
    ANTENNAGATEAREA 0.196500 ;
    PORT
      LAYER met3 ;
        RECT 0.000 438.640 4.000 439.240 ;
    END
  END m_axi_bvalid[0]
  PIN m_axi_bvalid[1]
    DIRECTION INPUT ;
    USE SIGNAL ;
    ANTENNAGATEAREA 0.196500 ;
    PORT
      LAYER met3 ;
        RECT 0.000 442.040 4.000 442.640 ;
    END
  END m_axi_bvalid[1]
  PIN m_axi_rdata[0]
    DIRECTION INPUT ;
    USE SIGNAL ;
    ANTENNAGATEAREA 0.196500 ;
    PORT
      LAYER met2 ;
        RECT 434.790 896.000 435.070 900.000 ;
    END
  END m_axi_rdata[0]
  PIN m_axi_rdata[10]
    DIRECTION INPUT ;
    USE SIGNAL ;
    ANTENNAGATEAREA 0.196500 ;
    PORT
      LAYER met2 ;
        RECT 289.890 896.000 290.170 900.000 ;
    END
  END m_axi_rdata[10]
  PIN m_axi_rdata[11]
    DIRECTION INPUT ;
    USE SIGNAL ;
    ANTENNAGATEAREA 0.196500 ;
    PORT
      LAYER met2 ;
        RECT 444.450 896.000 444.730 900.000 ;
    END
  END m_axi_rdata[11]
  PIN m_axi_rdata[12]
    DIRECTION INPUT ;
    USE SIGNAL ;
    ANTENNAGATEAREA 0.196500 ;
    PORT
      LAYER met2 ;
        RECT 479.870 896.000 480.150 900.000 ;
    END
  END m_axi_rdata[12]
  PIN m_axi_rdata[13]
    DIRECTION INPUT ;
    USE SIGNAL ;
    ANTENNAGATEAREA 0.196500 ;
    PORT
      LAYER met2 ;
        RECT 396.150 896.000 396.430 900.000 ;
    END
  END m_axi_rdata[13]
  PIN m_axi_rdata[14]
    DIRECTION INPUT ;
    USE SIGNAL ;
    ANTENNAGATEAREA 0.196500 ;
    PORT
      LAYER met2 ;
        RECT 421.910 896.000 422.190 900.000 ;
    END
  END m_axi_rdata[14]
  PIN m_axi_rdata[15]
    DIRECTION INPUT ;
    USE SIGNAL ;
    ANTENNAGATEAREA 0.196500 ;
    PORT
      LAYER met2 ;
        RECT 415.470 896.000 415.750 900.000 ;
    END
  END m_axi_rdata[15]
  PIN m_axi_rdata[16]
    DIRECTION INPUT ;
    USE SIGNAL ;
    ANTENNAGATEAREA 0.196500 ;
    PORT
      LAYER met2 ;
        RECT 273.790 896.000 274.070 900.000 ;
    END
  END m_axi_rdata[16]
  PIN m_axi_rdata[17]
    DIRECTION INPUT ;
    USE SIGNAL ;
    ANTENNAGATEAREA 0.126000 ;
    PORT
      LAYER met2 ;
        RECT 277.010 896.000 277.290 900.000 ;
    END
  END m_axi_rdata[17]
  PIN m_axi_rdata[18]
    DIRECTION INPUT ;
    USE SIGNAL ;
    ANTENNAGATEAREA 0.196500 ;
    PORT
      LAYER met2 ;
        RECT 293.110 896.000 293.390 900.000 ;
    END
  END m_axi_rdata[18]
  PIN m_axi_rdata[19]
    DIRECTION INPUT ;
    USE SIGNAL ;
    ANTENNAGATEAREA 0.196500 ;
    PORT
      LAYER met2 ;
        RECT 347.850 896.000 348.130 900.000 ;
    END
  END m_axi_rdata[19]
  PIN m_axi_rdata[1]
    DIRECTION INPUT ;
    USE SIGNAL ;
    ANTENNAGATEAREA 0.196500 ;
    PORT
      LAYER met2 ;
        RECT 473.430 896.000 473.710 900.000 ;
    END
  END m_axi_rdata[1]
  PIN m_axi_rdata[20]
    DIRECTION INPUT ;
    USE SIGNAL ;
    ANTENNAGATEAREA 0.196500 ;
    PORT
      LAYER met2 ;
        RECT 495.970 896.000 496.250 900.000 ;
    END
  END m_axi_rdata[20]
  PIN m_axi_rdata[21]
    DIRECTION INPUT ;
    USE SIGNAL ;
    ANTENNAGATEAREA 0.196500 ;
    PORT
      LAYER met2 ;
        RECT 483.090 896.000 483.370 900.000 ;
    END
  END m_axi_rdata[21]
  PIN m_axi_rdata[22]
    DIRECTION INPUT ;
    USE SIGNAL ;
    ANTENNAGATEAREA 0.196500 ;
    PORT
      LAYER met2 ;
        RECT 357.510 896.000 357.790 900.000 ;
    END
  END m_axi_rdata[22]
  PIN m_axi_rdata[23]
    DIRECTION INPUT ;
    USE SIGNAL ;
    ANTENNAGATEAREA 0.196500 ;
    PORT
      LAYER met2 ;
        RECT 518.510 896.000 518.790 900.000 ;
    END
  END m_axi_rdata[23]
  PIN m_axi_rdata[24]
    DIRECTION INPUT ;
    USE SIGNAL ;
    ANTENNAGATEAREA 0.196500 ;
    PORT
      LAYER met2 ;
        RECT 412.250 896.000 412.530 900.000 ;
    END
  END m_axi_rdata[24]
  PIN m_axi_rdata[25]
    DIRECTION INPUT ;
    USE SIGNAL ;
    ANTENNAGATEAREA 0.196500 ;
    PORT
      LAYER met2 ;
        RECT 512.070 896.000 512.350 900.000 ;
    END
  END m_axi_rdata[25]
  PIN m_axi_rdata[26]
    DIRECTION INPUT ;
    USE SIGNAL ;
    ANTENNAGATEAREA 0.213000 ;
    PORT
      LAYER met2 ;
        RECT 315.650 896.000 315.930 900.000 ;
    END
  END m_axi_rdata[26]
  PIN m_axi_rdata[27]
    DIRECTION INPUT ;
    USE SIGNAL ;
    ANTENNAGATEAREA 0.196500 ;
    PORT
      LAYER met2 ;
        RECT 338.190 896.000 338.470 900.000 ;
    END
  END m_axi_rdata[27]
  PIN m_axi_rdata[28]
    DIRECTION INPUT ;
    USE SIGNAL ;
    ANTENNAGATEAREA 0.196500 ;
    PORT
      LAYER met2 ;
        RECT 392.930 896.000 393.210 900.000 ;
    END
  END m_axi_rdata[28]
  PIN m_axi_rdata[29]
    DIRECTION INPUT ;
    USE SIGNAL ;
    ANTENNAGATEAREA 0.196500 ;
    PORT
      LAYER met2 ;
        RECT 470.210 896.000 470.490 900.000 ;
    END
  END m_axi_rdata[29]
  PIN m_axi_rdata[2]
    DIRECTION INPUT ;
    USE SIGNAL ;
    ANTENNAGATEAREA 0.196500 ;
    PORT
      LAYER met2 ;
        RECT 299.550 896.000 299.830 900.000 ;
    END
  END m_axi_rdata[2]
  PIN m_axi_rdata[30]
    DIRECTION INPUT ;
    USE SIGNAL ;
    ANTENNAGATEAREA 0.196500 ;
    PORT
      LAYER met2 ;
        RECT 302.770 896.000 303.050 900.000 ;
    END
  END m_axi_rdata[30]
  PIN m_axi_rdata[31]
    DIRECTION INPUT ;
    USE SIGNAL ;
    ANTENNAGATEAREA 0.196500 ;
    PORT
      LAYER met2 ;
        RECT 367.170 896.000 367.450 900.000 ;
    END
  END m_axi_rdata[31]
  PIN m_axi_rdata[32]
    DIRECTION INPUT ;
    USE SIGNAL ;
    ANTENNAGATEAREA 0.196500 ;
    PORT
      LAYER met2 ;
        RECT 286.670 896.000 286.950 900.000 ;
    END
  END m_axi_rdata[32]
  PIN m_axi_rdata[33]
    DIRECTION INPUT ;
    USE SIGNAL ;
    ANTENNAGATEAREA 0.196500 ;
    PORT
      LAYER met2 ;
        RECT 524.950 896.000 525.230 900.000 ;
    END
  END m_axi_rdata[33]
  PIN m_axi_rdata[34]
    DIRECTION INPUT ;
    USE SIGNAL ;
    ANTENNAGATEAREA 0.196500 ;
    PORT
      LAYER met2 ;
        RECT 296.330 896.000 296.610 900.000 ;
    END
  END m_axi_rdata[34]
  PIN m_axi_rdata[35]
    DIRECTION INPUT ;
    USE SIGNAL ;
    ANTENNAGATEAREA 0.196500 ;
    PORT
      LAYER met2 ;
        RECT 283.450 896.000 283.730 900.000 ;
    END
  END m_axi_rdata[35]
  PIN m_axi_rdata[36]
    DIRECTION INPUT ;
    USE SIGNAL ;
    ANTENNAGATEAREA 0.196500 ;
    PORT
      LAYER met2 ;
        RECT 557.150 896.000 557.430 900.000 ;
    END
  END m_axi_rdata[36]
  PIN m_axi_rdata[37]
    DIRECTION INPUT ;
    USE SIGNAL ;
    ANTENNAGATEAREA 0.196500 ;
    PORT
      LAYER met2 ;
        RECT 534.610 896.000 534.890 900.000 ;
    END
  END m_axi_rdata[37]
  PIN m_axi_rdata[38]
    DIRECTION INPUT ;
    USE SIGNAL ;
    ANTENNAGATEAREA 0.196500 ;
    PORT
      LAYER met2 ;
        RECT 257.690 896.000 257.970 900.000 ;
    END
  END m_axi_rdata[38]
  PIN m_axi_rdata[39]
    DIRECTION INPUT ;
    USE SIGNAL ;
    ANTENNAGATEAREA 0.196500 ;
    PORT
      LAYER met2 ;
        RECT 325.310 896.000 325.590 900.000 ;
    END
  END m_axi_rdata[39]
  PIN m_axi_rdata[3]
    DIRECTION INPUT ;
    USE SIGNAL ;
    ANTENNAGATEAREA 0.196500 ;
    PORT
      LAYER met2 ;
        RECT 344.630 896.000 344.910 900.000 ;
    END
  END m_axi_rdata[3]
  PIN m_axi_rdata[40]
    DIRECTION INPUT ;
    USE SIGNAL ;
    ANTENNAGATEAREA 0.196500 ;
    PORT
      LAYER met2 ;
        RECT 515.290 896.000 515.570 900.000 ;
    END
  END m_axi_rdata[40]
  PIN m_axi_rdata[41]
    DIRECTION INPUT ;
    USE SIGNAL ;
    ANTENNAGATEAREA 0.196500 ;
    PORT
      LAYER met2 ;
        RECT 376.830 896.000 377.110 900.000 ;
    END
  END m_axi_rdata[41]
  PIN m_axi_rdata[42]
    DIRECTION INPUT ;
    USE SIGNAL ;
    ANTENNAGATEAREA 0.196500 ;
    PORT
      LAYER met2 ;
        RECT 380.050 896.000 380.330 900.000 ;
    END
  END m_axi_rdata[42]
  PIN m_axi_rdata[43]
    DIRECTION INPUT ;
    USE SIGNAL ;
    ANTENNAGATEAREA 0.196500 ;
    PORT
      LAYER met2 ;
        RECT 441.230 896.000 441.510 900.000 ;
    END
  END m_axi_rdata[43]
  PIN m_axi_rdata[44]
    DIRECTION INPUT ;
    USE SIGNAL ;
    ANTENNAGATEAREA 0.196500 ;
    PORT
      LAYER met2 ;
        RECT 460.550 896.000 460.830 900.000 ;
    END
  END m_axi_rdata[44]
  PIN m_axi_rdata[45]
    DIRECTION INPUT ;
    USE SIGNAL ;
    ANTENNAGATEAREA 0.196500 ;
    PORT
      LAYER met2 ;
        RECT 389.710 896.000 389.990 900.000 ;
    END
  END m_axi_rdata[45]
  PIN m_axi_rdata[46]
    DIRECTION INPUT ;
    USE SIGNAL ;
    ANTENNAGATEAREA 0.196500 ;
    PORT
      LAYER met2 ;
        RECT 354.290 896.000 354.570 900.000 ;
    END
  END m_axi_rdata[46]
  PIN m_axi_rdata[47]
    DIRECTION INPUT ;
    USE SIGNAL ;
    ANTENNAGATEAREA 0.196500 ;
    PORT
      LAYER met2 ;
        RECT 505.630 896.000 505.910 900.000 ;
    END
  END m_axi_rdata[47]
  PIN m_axi_rdata[48]
    DIRECTION INPUT ;
    USE SIGNAL ;
    ANTENNAGATEAREA 0.196500 ;
    PORT
      LAYER met2 ;
        RECT 328.530 896.000 328.810 900.000 ;
    END
  END m_axi_rdata[48]
  PIN m_axi_rdata[49]
    DIRECTION INPUT ;
    USE SIGNAL ;
    ANTENNAGATEAREA 0.196500 ;
    PORT
      LAYER met2 ;
        RECT 438.010 896.000 438.290 900.000 ;
    END
  END m_axi_rdata[49]
  PIN m_axi_rdata[4]
    DIRECTION INPUT ;
    USE SIGNAL ;
    ANTENNAGATEAREA 0.159000 ;
    PORT
      LAYER met2 ;
        RECT 270.570 896.000 270.850 900.000 ;
    END
  END m_axi_rdata[4]
  PIN m_axi_rdata[50]
    DIRECTION INPUT ;
    USE SIGNAL ;
    ANTENNAGATEAREA 0.196500 ;
    PORT
      LAYER met2 ;
        RECT 450.890 896.000 451.170 900.000 ;
    END
  END m_axi_rdata[50]
  PIN m_axi_rdata[51]
    DIRECTION INPUT ;
    USE SIGNAL ;
    ANTENNAGATEAREA 0.196500 ;
    PORT
      LAYER met2 ;
        RECT 383.270 896.000 383.550 900.000 ;
    END
  END m_axi_rdata[51]
  PIN m_axi_rdata[52]
    DIRECTION INPUT ;
    USE SIGNAL ;
    ANTENNAGATEAREA 0.196500 ;
    PORT
      LAYER met2 ;
        RECT 373.610 896.000 373.890 900.000 ;
    END
  END m_axi_rdata[52]
  PIN m_axi_rdata[53]
    DIRECTION INPUT ;
    USE SIGNAL ;
    ANTENNAGATEAREA 0.196500 ;
    PORT
      LAYER met2 ;
        RECT 531.390 896.000 531.670 900.000 ;
    END
  END m_axi_rdata[53]
  PIN m_axi_rdata[54]
    DIRECTION INPUT ;
    USE SIGNAL ;
    ANTENNAGATEAREA 0.196500 ;
    PORT
      LAYER met2 ;
        RECT 418.690 896.000 418.970 900.000 ;
    END
  END m_axi_rdata[54]
  PIN m_axi_rdata[55]
    DIRECTION INPUT ;
    USE SIGNAL ;
    ANTENNAGATEAREA 0.213000 ;
    PORT
      LAYER met2 ;
        RECT 280.230 896.000 280.510 900.000 ;
    END
  END m_axi_rdata[55]
  PIN m_axi_rdata[56]
    DIRECTION INPUT ;
    USE SIGNAL ;
    ANTENNAGATEAREA 0.196500 ;
    PORT
      LAYER met2 ;
        RECT 425.130 896.000 425.410 900.000 ;
    END
  END m_axi_rdata[56]
  PIN m_axi_rdata[57]
    DIRECTION INPUT ;
    USE SIGNAL ;
    ANTENNAGATEAREA 0.196500 ;
    PORT
      LAYER met2 ;
        RECT 409.030 896.000 409.310 900.000 ;
    END
  END m_axi_rdata[57]
  PIN m_axi_rdata[58]
    DIRECTION INPUT ;
    USE SIGNAL ;
    ANTENNAGATEAREA 0.196500 ;
    PORT
      LAYER met2 ;
        RECT 521.730 896.000 522.010 900.000 ;
    END
  END m_axi_rdata[58]
  PIN m_axi_rdata[59]
    DIRECTION INPUT ;
    USE SIGNAL ;
    ANTENNAGATEAREA 0.196500 ;
    PORT
      LAYER met2 ;
        RECT 399.370 896.000 399.650 900.000 ;
    END
  END m_axi_rdata[59]
  PIN m_axi_rdata[5]
    DIRECTION INPUT ;
    USE SIGNAL ;
    ANTENNAGATEAREA 0.159000 ;
    PORT
      LAYER met2 ;
        RECT 305.990 896.000 306.270 900.000 ;
    END
  END m_axi_rdata[5]
  PIN m_axi_rdata[60]
    DIRECTION INPUT ;
    USE SIGNAL ;
    ANTENNAGATEAREA 0.196500 ;
    PORT
      LAYER met2 ;
        RECT 363.950 896.000 364.230 900.000 ;
    END
  END m_axi_rdata[60]
  PIN m_axi_rdata[61]
    DIRECTION INPUT ;
    USE SIGNAL ;
    ANTENNAGATEAREA 0.196500 ;
    PORT
      LAYER met2 ;
        RECT 341.410 896.000 341.690 900.000 ;
    END
  END m_axi_rdata[61]
  PIN m_axi_rdata[62]
    DIRECTION INPUT ;
    USE SIGNAL ;
    ANTENNAGATEAREA 0.196500 ;
    PORT
      LAYER met2 ;
        RECT 370.390 896.000 370.670 900.000 ;
    END
  END m_axi_rdata[62]
  PIN m_axi_rdata[63]
    DIRECTION INPUT ;
    USE SIGNAL ;
    ANTENNAGATEAREA 0.196500 ;
    PORT
      LAYER met2 ;
        RECT 334.970 896.000 335.250 900.000 ;
    END
  END m_axi_rdata[63]
  PIN m_axi_rdata[6]
    DIRECTION INPUT ;
    USE SIGNAL ;
    ANTENNAGATEAREA 0.196500 ;
    PORT
      LAYER met2 ;
        RECT 351.070 896.000 351.350 900.000 ;
    END
  END m_axi_rdata[6]
  PIN m_axi_rdata[7]
    DIRECTION INPUT ;
    USE SIGNAL ;
    ANTENNAGATEAREA 0.126000 ;
    PORT
      LAYER met2 ;
        RECT 431.570 896.000 431.850 900.000 ;
    END
  END m_axi_rdata[7]
  PIN m_axi_rdata[8]
    DIRECTION INPUT ;
    USE SIGNAL ;
    ANTENNAGATEAREA 0.213000 ;
    PORT
      LAYER met2 ;
        RECT 402.590 896.000 402.870 900.000 ;
    END
  END m_axi_rdata[8]
  PIN m_axi_rdata[9]
    DIRECTION INPUT ;
    USE SIGNAL ;
    ANTENNAGATEAREA 0.196500 ;
    PORT
      LAYER met2 ;
        RECT 322.090 896.000 322.370 900.000 ;
    END
  END m_axi_rdata[9]
  PIN m_axi_rready[0]
    DIRECTION OUTPUT ;
    USE SIGNAL ;
    ANTENNADIFFAREA 0.340600 ;
    PORT
      LAYER met2 ;
        RECT 544.270 896.000 544.550 900.000 ;
    END
  END m_axi_rready[0]
  PIN m_axi_rready[1]
    DIRECTION OUTPUT ;
    USE SIGNAL ;
    ANTENNADIFFAREA 0.340600 ;
    PORT
      LAYER met2 ;
        RECT 492.750 896.000 493.030 900.000 ;
    END
  END m_axi_rready[1]
  PIN m_axi_rresp[0]
    DIRECTION INPUT ;
    USE SIGNAL ;
    ANTENNAGATEAREA 0.159000 ;
    PORT
      LAYER met2 ;
        RECT 537.830 896.000 538.110 900.000 ;
    END
  END m_axi_rresp[0]
  PIN m_axi_rresp[1]
    DIRECTION INPUT ;
    USE SIGNAL ;
    ANTENNAGATEAREA 0.159000 ;
    PORT
      LAYER met2 ;
        RECT 502.410 896.000 502.690 900.000 ;
    END
  END m_axi_rresp[1]
  PIN m_axi_rresp[2]
    DIRECTION INPUT ;
    USE SIGNAL ;
    ANTENNAGATEAREA 0.159000 ;
    PORT
      LAYER met2 ;
        RECT 541.050 896.000 541.330 900.000 ;
    END
  END m_axi_rresp[2]
  PIN m_axi_rresp[3]
    DIRECTION INPUT ;
    USE SIGNAL ;
    ANTENNAGATEAREA 0.213000 ;
    PORT
      LAYER met2 ;
        RECT 499.190 896.000 499.470 900.000 ;
    END
  END m_axi_rresp[3]
  PIN m_axi_rvalid[0]
    DIRECTION INPUT ;
    USE SIGNAL ;
    ANTENNAGATEAREA 0.159000 ;
    PORT
      LAYER met2 ;
        RECT 528.170 896.000 528.450 900.000 ;
    END
  END m_axi_rvalid[0]
  PIN m_axi_rvalid[1]
    DIRECTION INPUT ;
    USE SIGNAL ;
    ANTENNAGATEAREA 0.213000 ;
    PORT
      LAYER met2 ;
        RECT 486.310 896.000 486.590 900.000 ;
    END
  END m_axi_rvalid[1]
  PIN m_axi_wdata[0]
    DIRECTION OUTPUT ;
    USE SIGNAL ;
    ANTENNADIFFAREA 0.340600 ;
    PORT
      LAYER met3 ;
        RECT 0.000 724.240 4.000 724.840 ;
    END
  END m_axi_wdata[0]
  PIN m_axi_wdata[10]
    DIRECTION OUTPUT ;
    USE SIGNAL ;
    ANTENNADIFFAREA 0.340600 ;
    PORT
      LAYER met3 ;
        RECT 0.000 564.440 4.000 565.040 ;
    END
  END m_axi_wdata[10]
  PIN m_axi_wdata[11]
    DIRECTION OUTPUT ;
    USE SIGNAL ;
    ANTENNADIFFAREA 0.340600 ;
    PORT
      LAYER met3 ;
        RECT 0.000 754.840 4.000 755.440 ;
    END
  END m_axi_wdata[11]
  PIN m_axi_wdata[12]
    DIRECTION OUTPUT ;
    USE SIGNAL ;
    ANTENNADIFFAREA 0.340600 ;
    PORT
      LAYER met3 ;
        RECT 0.000 588.240 4.000 588.840 ;
    END
  END m_axi_wdata[12]
  PIN m_axi_wdata[13]
    DIRECTION OUTPUT ;
    USE SIGNAL ;
    ANTENNADIFFAREA 0.340600 ;
    PORT
      LAYER met3 ;
        RECT 0.000 540.640 4.000 541.240 ;
    END
  END m_axi_wdata[13]
  PIN m_axi_wdata[14]
    DIRECTION OUTPUT ;
    USE SIGNAL ;
    ANTENNADIFFAREA 0.340600 ;
    PORT
      LAYER met3 ;
        RECT 0.000 652.840 4.000 653.440 ;
    END
  END m_axi_wdata[14]
  PIN m_axi_wdata[15]
    DIRECTION OUTPUT ;
    USE SIGNAL ;
    ANTENNADIFFAREA 0.340600 ;
    PORT
      LAYER met3 ;
        RECT 0.000 629.040 4.000 629.640 ;
    END
  END m_axi_wdata[15]
  PIN m_axi_wdata[16]
    DIRECTION OUTPUT ;
    USE SIGNAL ;
    ANTENNADIFFAREA 0.340600 ;
    PORT
      LAYER met3 ;
        RECT 0.000 707.240 4.000 707.840 ;
    END
  END m_axi_wdata[16]
  PIN m_axi_wdata[17]
    DIRECTION OUTPUT ;
    USE SIGNAL ;
    ANTENNADIFFAREA 0.340600 ;
    PORT
      LAYER met3 ;
        RECT 0.000 595.040 4.000 595.640 ;
    END
  END m_axi_wdata[17]
  PIN m_axi_wdata[18]
    DIRECTION OUTPUT ;
    USE SIGNAL ;
    ANTENNADIFFAREA 0.340600 ;
    PORT
      LAYER met3 ;
        RECT 0.000 550.840 4.000 551.440 ;
    END
  END m_axi_wdata[18]
  PIN m_axi_wdata[19]
    DIRECTION OUTPUT ;
    USE SIGNAL ;
    ANTENNADIFFAREA 0.340600 ;
    PORT
      LAYER met3 ;
        RECT 0.000 547.440 4.000 548.040 ;
    END
  END m_axi_wdata[19]
  PIN m_axi_wdata[1]
    DIRECTION OUTPUT ;
    USE SIGNAL ;
    ANTENNADIFFAREA 0.340600 ;
    PORT
      LAYER met3 ;
        RECT 0.000 608.640 4.000 609.240 ;
    END
  END m_axi_wdata[1]
  PIN m_axi_wdata[20]
    DIRECTION OUTPUT ;
    USE SIGNAL ;
    ANTENNADIFFAREA 0.340600 ;
    PORT
      LAYER met3 ;
        RECT 0.000 578.040 4.000 578.640 ;
    END
  END m_axi_wdata[20]
  PIN m_axi_wdata[21]
    DIRECTION OUTPUT ;
    USE SIGNAL ;
    ANTENNADIFFAREA 0.340600 ;
    PORT
      LAYER met3 ;
        RECT 0.000 561.040 4.000 561.640 ;
    END
  END m_axi_wdata[21]
  PIN m_axi_wdata[22]
    DIRECTION OUTPUT ;
    USE SIGNAL ;
    ANTENNADIFFAREA 0.340600 ;
    PORT
      LAYER met3 ;
        RECT 0.000 574.640 4.000 575.240 ;
    END
  END m_axi_wdata[22]
  PIN m_axi_wdata[23]
    DIRECTION OUTPUT ;
    USE SIGNAL ;
    ANTENNADIFFAREA 0.340600 ;
    PORT
      LAYER met3 ;
        RECT 0.000 537.240 4.000 537.840 ;
    END
  END m_axi_wdata[23]
  PIN m_axi_wdata[24]
    DIRECTION OUTPUT ;
    USE SIGNAL ;
    ANTENNADIFFAREA 0.340600 ;
    PORT
      LAYER met3 ;
        RECT 0.000 557.640 4.000 558.240 ;
    END
  END m_axi_wdata[24]
  PIN m_axi_wdata[25]
    DIRECTION OUTPUT ;
    USE SIGNAL ;
    ANTENNADIFFAREA 0.340600 ;
    PORT
      LAYER met3 ;
        RECT 0.000 489.640 4.000 490.240 ;
    END
  END m_axi_wdata[25]
  PIN m_axi_wdata[26]
    DIRECTION OUTPUT ;
    USE SIGNAL ;
    ANTENNADIFFAREA 0.340600 ;
    PORT
      LAYER met3 ;
        RECT 0.000 530.440 4.000 531.040 ;
    END
  END m_axi_wdata[26]
  PIN m_axi_wdata[27]
    DIRECTION OUTPUT ;
    USE SIGNAL ;
    ANTENNADIFFAREA 0.340600 ;
    PORT
      LAYER met3 ;
        RECT 0.000 516.840 4.000 517.440 ;
    END
  END m_axi_wdata[27]
  PIN m_axi_wdata[28]
    DIRECTION OUTPUT ;
    USE SIGNAL ;
    ANTENNADIFFAREA 0.340600 ;
    PORT
      LAYER met3 ;
        RECT 0.000 506.640 4.000 507.240 ;
    END
  END m_axi_wdata[28]
  PIN m_axi_wdata[29]
    DIRECTION OUTPUT ;
    USE SIGNAL ;
    ANTENNADIFFAREA 0.340600 ;
    PORT
      LAYER met3 ;
        RECT 0.000 513.440 4.000 514.040 ;
    END
  END m_axi_wdata[29]
  PIN m_axi_wdata[2]
    DIRECTION OUTPUT ;
    USE SIGNAL ;
    ANTENNADIFFAREA 0.340600 ;
    PORT
      LAYER met3 ;
        RECT 0.000 659.640 4.000 660.240 ;
    END
  END m_axi_wdata[2]
  PIN m_axi_wdata[30]
    DIRECTION OUTPUT ;
    USE SIGNAL ;
    ANTENNADIFFAREA 0.340600 ;
    PORT
      LAYER met3 ;
        RECT 0.000 499.840 4.000 500.440 ;
    END
  END m_axi_wdata[30]
  PIN m_axi_wdata[31]
    DIRECTION OUTPUT ;
    USE SIGNAL ;
    ANTENNADIFFAREA 0.340600 ;
    PORT
      LAYER met3 ;
        RECT 0.000 669.840 4.000 670.440 ;
    END
  END m_axi_wdata[31]
  PIN m_axi_wdata[32]
    DIRECTION OUTPUT ;
    USE SIGNAL ;
    ANTENNADIFFAREA 0.340600 ;
    PORT
      LAYER met3 ;
        RECT 0.000 700.440 4.000 701.040 ;
    END
  END m_axi_wdata[32]
  PIN m_axi_wdata[33]
    DIRECTION OUTPUT ;
    USE SIGNAL ;
    ANTENNADIFFAREA 0.340600 ;
    PORT
      LAYER met3 ;
        RECT 0.000 690.240 4.000 690.840 ;
    END
  END m_axi_wdata[33]
  PIN m_axi_wdata[34]
    DIRECTION OUTPUT ;
    USE SIGNAL ;
    ANTENNADIFFAREA 0.340600 ;
    PORT
      LAYER met3 ;
        RECT 0.000 601.840 4.000 602.440 ;
    END
  END m_axi_wdata[34]
  PIN m_axi_wdata[35]
    DIRECTION OUTPUT ;
    USE SIGNAL ;
    ANTENNADIFFAREA 0.340600 ;
    PORT
      LAYER met3 ;
        RECT 0.000 778.640 4.000 779.240 ;
    END
  END m_axi_wdata[35]
  PIN m_axi_wdata[36]
    DIRECTION OUTPUT ;
    USE SIGNAL ;
    ANTENNADIFFAREA 0.340600 ;
    PORT
      LAYER met3 ;
        RECT 0.000 720.840 4.000 721.440 ;
    END
  END m_axi_wdata[36]
  PIN m_axi_wdata[37]
    DIRECTION OUTPUT ;
    USE SIGNAL ;
    ANTENNADIFFAREA 0.340600 ;
    PORT
      LAYER met3 ;
        RECT 0.000 731.040 4.000 731.640 ;
    END
  END m_axi_wdata[37]
  PIN m_axi_wdata[38]
    DIRECTION OUTPUT ;
    USE SIGNAL ;
    ANTENNADIFFAREA 0.340600 ;
    PORT
      LAYER met3 ;
        RECT 0.000 748.040 4.000 748.640 ;
    END
  END m_axi_wdata[38]
  PIN m_axi_wdata[39]
    DIRECTION OUTPUT ;
    USE SIGNAL ;
    ANTENNADIFFAREA 0.340600 ;
    PORT
      LAYER met3 ;
        RECT 0.000 826.240 4.000 826.840 ;
    END
  END m_axi_wdata[39]
  PIN m_axi_wdata[3]
    DIRECTION OUTPUT ;
    USE SIGNAL ;
    ANTENNADIFFAREA 0.340600 ;
    PORT
      LAYER met3 ;
        RECT 0.000 598.440 4.000 599.040 ;
    END
  END m_axi_wdata[3]
  PIN m_axi_wdata[40]
    DIRECTION OUTPUT ;
    USE SIGNAL ;
    ANTENNADIFFAREA 0.340600 ;
    PORT
      LAYER met3 ;
        RECT 0.000 697.040 4.000 697.640 ;
    END
  END m_axi_wdata[40]
  PIN m_axi_wdata[41]
    DIRECTION OUTPUT ;
    USE SIGNAL ;
    ANTENNADIFFAREA 0.340600 ;
    PORT
      LAYER met3 ;
        RECT 0.000 737.840 4.000 738.440 ;
    END
  END m_axi_wdata[41]
  PIN m_axi_wdata[42]
    DIRECTION OUTPUT ;
    USE SIGNAL ;
    ANTENNADIFFAREA 0.340600 ;
    PORT
      LAYER met3 ;
        RECT 0.000 581.440 4.000 582.040 ;
    END
  END m_axi_wdata[42]
  PIN m_axi_wdata[43]
    DIRECTION OUTPUT ;
    USE SIGNAL ;
    ANTENNADIFFAREA 0.340600 ;
    PORT
      LAYER met3 ;
        RECT 0.000 833.040 4.000 833.640 ;
    END
  END m_axi_wdata[43]
  PIN m_axi_wdata[44]
    DIRECTION OUTPUT ;
    USE SIGNAL ;
    ANTENNADIFFAREA 0.340600 ;
    PORT
      LAYER met3 ;
        RECT 0.000 680.040 4.000 680.640 ;
    END
  END m_axi_wdata[44]
  PIN m_axi_wdata[45]
    DIRECTION OUTPUT ;
    USE SIGNAL ;
    ANTENNADIFFAREA 0.340600 ;
    PORT
      LAYER met3 ;
        RECT 0.000 771.840 4.000 772.440 ;
    END
  END m_axi_wdata[45]
  PIN m_axi_wdata[46]
    DIRECTION OUTPUT ;
    USE SIGNAL ;
    ANTENNADIFFAREA 0.340600 ;
    PORT
      LAYER met3 ;
        RECT 0.000 673.240 4.000 673.840 ;
    END
  END m_axi_wdata[46]
  PIN m_axi_wdata[47]
    DIRECTION OUTPUT ;
    USE SIGNAL ;
    ANTENNADIFFAREA 0.340600 ;
    PORT
      LAYER met3 ;
        RECT 0.000 802.440 4.000 803.040 ;
    END
  END m_axi_wdata[47]
  PIN m_axi_wdata[48]
    DIRECTION OUTPUT ;
    USE SIGNAL ;
    ANTENNADIFFAREA 0.340600 ;
    PORT
      LAYER met3 ;
        RECT 0.000 639.240 4.000 639.840 ;
    END
  END m_axi_wdata[48]
  PIN m_axi_wdata[49]
    DIRECTION OUTPUT ;
    USE SIGNAL ;
    ANTENNADIFFAREA 0.340600 ;
    PORT
      LAYER met3 ;
        RECT 0.000 788.840 4.000 789.440 ;
    END
  END m_axi_wdata[49]
  PIN m_axi_wdata[4]
    DIRECTION OUTPUT ;
    USE SIGNAL ;
    ANTENNADIFFAREA 0.340600 ;
    PORT
      LAYER met3 ;
        RECT 0.000 612.040 4.000 612.640 ;
    END
  END m_axi_wdata[4]
  PIN m_axi_wdata[50]
    DIRECTION OUTPUT ;
    USE SIGNAL ;
    ANTENNADIFFAREA 0.340600 ;
    PORT
      LAYER met3 ;
        RECT 0.000 544.040 4.000 544.640 ;
    END
  END m_axi_wdata[50]
  PIN m_axi_wdata[51]
    DIRECTION OUTPUT ;
    USE SIGNAL ;
    ANTENNADIFFAREA 0.340600 ;
    PORT
      LAYER met3 ;
        RECT 0.000 717.440 4.000 718.040 ;
    END
  END m_axi_wdata[51]
  PIN m_axi_wdata[52]
    DIRECTION OUTPUT ;
    USE SIGNAL ;
    ANTENNADIFFAREA 0.340600 ;
    PORT
      LAYER met3 ;
        RECT 0.000 584.840 4.000 585.440 ;
    END
  END m_axi_wdata[52]
  PIN m_axi_wdata[53]
    DIRECTION OUTPUT ;
    USE SIGNAL ;
    ANTENNADIFFAREA 0.340600 ;
    PORT
      LAYER met3 ;
        RECT 0.000 567.840 4.000 568.440 ;
    END
  END m_axi_wdata[53]
  PIN m_axi_wdata[54]
    DIRECTION OUTPUT ;
    USE SIGNAL ;
    ANTENNADIFFAREA 0.340600 ;
    PORT
      LAYER met3 ;
        RECT 0.000 571.240 4.000 571.840 ;
    END
  END m_axi_wdata[54]
  PIN m_axi_wdata[55]
    DIRECTION OUTPUT ;
    USE SIGNAL ;
    ANTENNADIFFAREA 0.340600 ;
    PORT
      LAYER met3 ;
        RECT 0.000 625.640 4.000 626.240 ;
    END
  END m_axi_wdata[55]
  PIN m_axi_wdata[56]
    DIRECTION OUTPUT ;
    USE SIGNAL ;
    ANTENNADIFFAREA 0.340600 ;
    PORT
      LAYER met3 ;
        RECT 0.000 554.240 4.000 554.840 ;
    END
  END m_axi_wdata[56]
  PIN m_axi_wdata[57]
    DIRECTION OUTPUT ;
    USE SIGNAL ;
    ANTENNADIFFAREA 0.340600 ;
    PORT
      LAYER met3 ;
        RECT 0.000 486.240 4.000 486.840 ;
    END
  END m_axi_wdata[57]
  PIN m_axi_wdata[58]
    DIRECTION OUTPUT ;
    USE SIGNAL ;
    ANTENNADIFFAREA 0.340600 ;
    PORT
      LAYER met3 ;
        RECT 0.000 527.040 4.000 527.640 ;
    END
  END m_axi_wdata[58]
  PIN m_axi_wdata[59]
    DIRECTION OUTPUT ;
    USE SIGNAL ;
    ANTENNADIFFAREA 0.340600 ;
    PORT
      LAYER met3 ;
        RECT 0.000 520.240 4.000 520.840 ;
    END
  END m_axi_wdata[59]
  PIN m_axi_wdata[5]
    DIRECTION OUTPUT ;
    USE SIGNAL ;
    ANTENNADIFFAREA 0.340600 ;
    PORT
      LAYER met3 ;
        RECT 0.000 850.040 4.000 850.640 ;
    END
  END m_axi_wdata[5]
  PIN m_axi_wdata[60]
    DIRECTION OUTPUT ;
    USE SIGNAL ;
    ANTENNADIFFAREA 0.340600 ;
    PORT
      LAYER met3 ;
        RECT 0.000 510.040 4.000 510.640 ;
    END
  END m_axi_wdata[60]
  PIN m_axi_wdata[61]
    DIRECTION OUTPUT ;
    USE SIGNAL ;
    ANTENNADIFFAREA 0.340600 ;
    PORT
      LAYER met3 ;
        RECT 0.000 523.640 4.000 524.240 ;
    END
  END m_axi_wdata[61]
  PIN m_axi_wdata[62]
    DIRECTION OUTPUT ;
    USE SIGNAL ;
    ANTENNADIFFAREA 0.340600 ;
    PORT
      LAYER met3 ;
        RECT 0.000 503.240 4.000 503.840 ;
    END
  END m_axi_wdata[62]
  PIN m_axi_wdata[63]
    DIRECTION OUTPUT ;
    USE SIGNAL ;
    ANTENNADIFFAREA 0.340600 ;
    PORT
      LAYER met3 ;
        RECT 0.000 493.040 4.000 493.640 ;
    END
  END m_axi_wdata[63]
  PIN m_axi_wdata[6]
    DIRECTION OUTPUT ;
    USE SIGNAL ;
    ANTENNADIFFAREA 0.340600 ;
    PORT
      LAYER met3 ;
        RECT 0.000 792.240 4.000 792.840 ;
    END
  END m_axi_wdata[6]
  PIN m_axi_wdata[7]
    DIRECTION OUTPUT ;
    USE SIGNAL ;
    ANTENNADIFFAREA 0.340600 ;
    PORT
      LAYER met3 ;
        RECT 0.000 761.640 4.000 762.240 ;
    END
  END m_axi_wdata[7]
  PIN m_axi_wdata[8]
    DIRECTION OUTPUT ;
    USE SIGNAL ;
    ANTENNADIFFAREA 0.340600 ;
    PORT
      LAYER met3 ;
        RECT 0.000 686.840 4.000 687.440 ;
    END
  END m_axi_wdata[8]
  PIN m_axi_wdata[9]
    DIRECTION OUTPUT ;
    USE SIGNAL ;
    ANTENNADIFFAREA 0.340600 ;
    PORT
      LAYER met3 ;
        RECT 0.000 591.640 4.000 592.240 ;
    END
  END m_axi_wdata[9]
  PIN m_axi_wready[0]
    DIRECTION INPUT ;
    USE SIGNAL ;
    ANTENNAGATEAREA 0.196500 ;
    PORT
      LAYER met3 ;
        RECT 0.000 278.840 4.000 279.440 ;
    END
  END m_axi_wready[0]
  PIN m_axi_wready[1]
    DIRECTION INPUT ;
    USE SIGNAL ;
    ANTENNAGATEAREA 0.196500 ;
    PORT
      LAYER met3 ;
        RECT 0.000 404.640 4.000 405.240 ;
    END
  END m_axi_wready[1]
  PIN m_axi_wstrb[0]
    DIRECTION OUTPUT ;
    USE SIGNAL ;
    ANTENNADIFFAREA 0.340600 ;
    PORT
      LAYER met3 ;
        RECT 0.000 428.440 4.000 429.040 ;
    END
  END m_axi_wstrb[0]
  PIN m_axi_wstrb[1]
    DIRECTION OUTPUT ;
    USE SIGNAL ;
    ANTENNADIFFAREA 0.340600 ;
    PORT
      LAYER met3 ;
        RECT 0.000 744.640 4.000 745.240 ;
    END
  END m_axi_wstrb[1]
  PIN m_axi_wstrb[2]
    DIRECTION OUTPUT ;
    USE SIGNAL ;
    ANTENNADIFFAREA 0.340600 ;
    PORT
      LAYER met3 ;
        RECT 0.000 785.440 4.000 786.040 ;
    END
  END m_axi_wstrb[2]
  PIN m_axi_wstrb[3]
    DIRECTION OUTPUT ;
    USE SIGNAL ;
    ANTENNADIFFAREA 0.340600 ;
    PORT
      LAYER met3 ;
        RECT 0.000 646.040 4.000 646.640 ;
    END
  END m_axi_wstrb[3]
  PIN m_axi_wstrb[4]
    DIRECTION OUTPUT ;
    USE SIGNAL ;
    ANTENNADIFFAREA 0.340600 ;
    PORT
      LAYER met3 ;
        RECT 0.000 265.240 4.000 265.840 ;
    END
  END m_axi_wstrb[4]
  PIN m_axi_wstrb[5]
    DIRECTION OUTPUT ;
    USE SIGNAL ;
    ANTENNADIFFAREA 0.340600 ;
    PORT
      LAYER met3 ;
        RECT 0.000 615.440 4.000 616.040 ;
    END
  END m_axi_wstrb[5]
  PIN m_axi_wstrb[6]
    DIRECTION OUTPUT ;
    USE SIGNAL ;
    ANTENNADIFFAREA 0.340600 ;
    PORT
      LAYER met3 ;
        RECT 0.000 727.640 4.000 728.240 ;
    END
  END m_axi_wstrb[6]
  PIN m_axi_wstrb[7]
    DIRECTION OUTPUT ;
    USE SIGNAL ;
    ANTENNADIFFAREA 0.340600 ;
    PORT
      LAYER met3 ;
        RECT 0.000 632.440 4.000 633.040 ;
    END
  END m_axi_wstrb[7]
  PIN m_axi_wvalid[0]
    DIRECTION OUTPUT ;
    USE SIGNAL ;
    ANTENNADIFFAREA 0.340600 ;
    PORT
      LAYER met3 ;
        RECT 0.000 408.040 4.000 408.640 ;
    END
  END m_axi_wvalid[0]
  PIN m_axi_wvalid[1]
    DIRECTION OUTPUT ;
    USE SIGNAL ;
    ANTENNADIFFAREA 0.340600 ;
    PORT
      LAYER met3 ;
        RECT 0.000 445.440 4.000 446.040 ;
    END
  END m_axi_wvalid[1]
  PIN s_axi_araddr[0]
    DIRECTION INPUT ;
    USE SIGNAL ;
    ANTENNAGATEAREA 0.196500 ;
    PORT
      LAYER met2 ;
        RECT 872.710 896.000 872.990 900.000 ;
    END
  END s_axi_araddr[0]
  PIN s_axi_araddr[100]
    DIRECTION INPUT ;
    USE SIGNAL ;
    ANTENNAGATEAREA 0.196500 ;
    PORT
      LAYER met2 ;
        RECT 608.670 896.000 608.950 900.000 ;
    END
  END s_axi_araddr[100]
  PIN s_axi_araddr[101]
    DIRECTION INPUT ;
    USE SIGNAL ;
    ANTENNAGATEAREA 0.196500 ;
    PORT
      LAYER met2 ;
        RECT 805.090 896.000 805.370 900.000 ;
    END
  END s_axi_araddr[101]
  PIN s_axi_araddr[102]
    DIRECTION INPUT ;
    USE SIGNAL ;
    ANTENNAGATEAREA 0.126000 ;
    PORT
      LAYER met2 ;
        RECT 692.390 896.000 692.670 900.000 ;
    END
  END s_axi_araddr[102]
  PIN s_axi_araddr[103]
    DIRECTION INPUT ;
    USE SIGNAL ;
    ANTENNAGATEAREA 0.126000 ;
    PORT
      LAYER met2 ;
        RECT 779.330 896.000 779.610 900.000 ;
    END
  END s_axi_araddr[103]
  PIN s_axi_araddr[104]
    DIRECTION INPUT ;
    USE SIGNAL ;
    ANTENNAGATEAREA 0.196500 ;
    PORT
      LAYER met2 ;
        RECT 656.970 896.000 657.250 900.000 ;
    END
  END s_axi_araddr[104]
  PIN s_axi_araddr[105]
    DIRECTION INPUT ;
    USE SIGNAL ;
    ANTENNAGATEAREA 0.126000 ;
    PORT
      LAYER met2 ;
        RECT 788.990 896.000 789.270 900.000 ;
    END
  END s_axi_araddr[105]
  PIN s_axi_araddr[106]
    DIRECTION INPUT ;
    USE SIGNAL ;
    ANTENNAGATEAREA 0.196500 ;
    PORT
      LAYER met2 ;
        RECT 689.170 896.000 689.450 900.000 ;
    END
  END s_axi_araddr[106]
  PIN s_axi_araddr[107]
    DIRECTION INPUT ;
    USE SIGNAL ;
    ANTENNAGATEAREA 0.126000 ;
    PORT
      LAYER met3 ;
        RECT 896.000 414.840 900.000 415.440 ;
    END
  END s_axi_araddr[107]
  PIN s_axi_araddr[108]
    DIRECTION INPUT ;
    USE SIGNAL ;
    ANTENNAGATEAREA 0.196500 ;
    PORT
      LAYER met2 ;
        RECT 705.270 896.000 705.550 900.000 ;
    END
  END s_axi_araddr[108]
  PIN s_axi_araddr[109]
    DIRECTION INPUT ;
    USE SIGNAL ;
    ANTENNAGATEAREA 0.196500 ;
    PORT
      LAYER met2 ;
        RECT 640.870 896.000 641.150 900.000 ;
    END
  END s_axi_araddr[109]
  PIN s_axi_araddr[10]
    DIRECTION INPUT ;
    USE SIGNAL ;
    ANTENNAGATEAREA 0.196500 ;
    PORT
      LAYER met2 ;
        RECT 685.950 896.000 686.230 900.000 ;
    END
  END s_axi_araddr[10]
  PIN s_axi_araddr[110]
    DIRECTION INPUT ;
    USE SIGNAL ;
    ANTENNAGATEAREA 0.213000 ;
    PORT
      LAYER met2 ;
        RECT 721.370 896.000 721.650 900.000 ;
    END
  END s_axi_araddr[110]
  PIN s_axi_araddr[111]
    DIRECTION INPUT ;
    USE SIGNAL ;
    ANTENNAGATEAREA 0.196500 ;
    PORT
      LAYER met3 ;
        RECT 896.000 499.840 900.000 500.440 ;
    END
  END s_axi_araddr[111]
  PIN s_axi_araddr[112]
    DIRECTION INPUT ;
    USE SIGNAL ;
    ANTENNAGATEAREA 0.196500 ;
    PORT
      LAYER met2 ;
        RECT 801.870 896.000 802.150 900.000 ;
    END
  END s_axi_araddr[112]
  PIN s_axi_araddr[113]
    DIRECTION INPUT ;
    USE SIGNAL ;
    ANTENNAGATEAREA 0.196500 ;
    PORT
      LAYER met2 ;
        RECT 885.590 896.000 885.870 900.000 ;
    END
  END s_axi_araddr[113]
  PIN s_axi_araddr[114]
    DIRECTION INPUT ;
    USE SIGNAL ;
    ANTENNAGATEAREA 0.196500 ;
    PORT
      LAYER met2 ;
        RECT 895.250 896.000 895.530 900.000 ;
    END
  END s_axi_araddr[114]
  PIN s_axi_araddr[115]
    DIRECTION INPUT ;
    USE SIGNAL ;
    ANTENNAGATEAREA 0.196500 ;
    PORT
      LAYER met2 ;
        RECT 863.050 896.000 863.330 900.000 ;
    END
  END s_axi_araddr[115]
  PIN s_axi_araddr[116]
    DIRECTION INPUT ;
    USE SIGNAL ;
    ANTENNAGATEAREA 0.196500 ;
    PORT
      LAYER met3 ;
        RECT 896.000 346.840 900.000 347.440 ;
    END
  END s_axi_araddr[116]
  PIN s_axi_araddr[117]
    DIRECTION INPUT ;
    USE SIGNAL ;
    ANTENNAGATEAREA 0.196500 ;
    PORT
      LAYER met3 ;
        RECT 896.000 156.440 900.000 157.040 ;
    END
  END s_axi_araddr[117]
  PIN s_axi_araddr[118]
    DIRECTION INPUT ;
    USE SIGNAL ;
    ANTENNAGATEAREA 0.196500 ;
    PORT
      LAYER met3 ;
        RECT 896.000 217.640 900.000 218.240 ;
    END
  END s_axi_araddr[118]
  PIN s_axi_araddr[119]
    DIRECTION INPUT ;
    USE SIGNAL ;
    ANTENNAGATEAREA 0.196500 ;
    PORT
      LAYER met3 ;
        RECT 896.000 425.040 900.000 425.640 ;
    END
  END s_axi_araddr[119]
  PIN s_axi_araddr[11]
    DIRECTION INPUT ;
    USE SIGNAL ;
    ANTENNAGATEAREA 0.159000 ;
    PORT
      LAYER met3 ;
        RECT 896.000 95.240 900.000 95.840 ;
    END
  END s_axi_araddr[11]
  PIN s_axi_araddr[120]
    DIRECTION INPUT ;
    USE SIGNAL ;
    ANTENNAGATEAREA 0.196500 ;
    PORT
      LAYER met3 ;
        RECT 896.000 431.840 900.000 432.440 ;
    END
  END s_axi_araddr[120]
  PIN s_axi_araddr[121]
    DIRECTION INPUT ;
    USE SIGNAL ;
    ANTENNAGATEAREA 0.196500 ;
    PORT
      LAYER met3 ;
        RECT 896.000 241.440 900.000 242.040 ;
    END
  END s_axi_araddr[121]
  PIN s_axi_araddr[122]
    DIRECTION INPUT ;
    USE SIGNAL ;
    ANTENNAGATEAREA 0.196500 ;
    PORT
      LAYER met3 ;
        RECT 896.000 265.240 900.000 265.840 ;
    END
  END s_axi_araddr[122]
  PIN s_axi_araddr[123]
    DIRECTION INPUT ;
    USE SIGNAL ;
    ANTENNAGATEAREA 0.196500 ;
    PORT
      LAYER met3 ;
        RECT 896.000 292.440 900.000 293.040 ;
    END
  END s_axi_araddr[123]
  PIN s_axi_araddr[124]
    DIRECTION INPUT ;
    USE SIGNAL ;
    ANTENNAGATEAREA 0.196500 ;
    PORT
      LAYER met3 ;
        RECT 896.000 204.040 900.000 204.640 ;
    END
  END s_axi_araddr[124]
  PIN s_axi_araddr[125]
    DIRECTION INPUT ;
    USE SIGNAL ;
    ANTENNAGATEAREA 0.196500 ;
    PORT
      LAYER met3 ;
        RECT 896.000 275.440 900.000 276.040 ;
    END
  END s_axi_araddr[125]
  PIN s_axi_araddr[126]
    DIRECTION INPUT ;
    USE SIGNAL ;
    ANTENNAGATEAREA 0.196500 ;
    PORT
      LAYER met3 ;
        RECT 896.000 74.840 900.000 75.440 ;
    END
  END s_axi_araddr[126]
  PIN s_axi_araddr[127]
    DIRECTION INPUT ;
    USE SIGNAL ;
    ANTENNAGATEAREA 0.213000 ;
    PORT
      LAYER met3 ;
        RECT 896.000 183.640 900.000 184.240 ;
    END
  END s_axi_araddr[127]
  PIN s_axi_araddr[12]
    DIRECTION INPUT ;
    USE SIGNAL ;
    ANTENNAGATEAREA 0.196500 ;
    PORT
      LAYER met2 ;
        RECT 766.450 896.000 766.730 900.000 ;
    END
  END s_axi_araddr[12]
  PIN s_axi_araddr[13]
    DIRECTION INPUT ;
    USE SIGNAL ;
    ANTENNAGATEAREA 0.196500 ;
    PORT
      LAYER met2 ;
        RECT 743.910 896.000 744.190 900.000 ;
    END
  END s_axi_araddr[13]
  PIN s_axi_araddr[14]
    DIRECTION INPUT ;
    USE SIGNAL ;
    ANTENNAGATEAREA 0.196500 ;
    PORT
      LAYER met2 ;
        RECT 750.350 896.000 750.630 900.000 ;
    END
  END s_axi_araddr[14]
  PIN s_axi_araddr[15]
    DIRECTION INPUT ;
    USE SIGNAL ;
    ANTENNAGATEAREA 0.196500 ;
    PORT
      LAYER met3 ;
        RECT 896.000 387.640 900.000 388.240 ;
    END
  END s_axi_araddr[15]
  PIN s_axi_araddr[16]
    DIRECTION INPUT ;
    USE SIGNAL ;
    ANTENNAGATEAREA 0.196500 ;
    PORT
      LAYER met2 ;
        RECT 824.410 896.000 824.690 900.000 ;
    END
  END s_axi_araddr[16]
  PIN s_axi_araddr[17]
    DIRECTION INPUT ;
    USE SIGNAL ;
    ANTENNAGATEAREA 0.196500 ;
    PORT
      LAYER met2 ;
        RECT 888.810 896.000 889.090 900.000 ;
    END
  END s_axi_araddr[17]
  PIN s_axi_araddr[18]
    DIRECTION INPUT ;
    USE SIGNAL ;
    ANTENNAGATEAREA 0.213000 ;
    PORT
      LAYER met2 ;
        RECT 582.910 896.000 583.190 900.000 ;
    END
  END s_axi_araddr[18]
  PIN s_axi_araddr[19]
    DIRECTION INPUT ;
    USE SIGNAL ;
    ANTENNAGATEAREA 0.213000 ;
    PORT
      LAYER met2 ;
        RECT 547.490 896.000 547.770 900.000 ;
    END
  END s_axi_araddr[19]
  PIN s_axi_araddr[1]
    DIRECTION INPUT ;
    USE SIGNAL ;
    ANTENNAGATEAREA 0.196500 ;
    PORT
      LAYER met2 ;
        RECT 660.190 896.000 660.470 900.000 ;
    END
  END s_axi_araddr[1]
  PIN s_axi_araddr[20]
    DIRECTION INPUT ;
    USE SIGNAL ;
    ANTENNAGATEAREA 0.213000 ;
    PORT
      LAYER met3 ;
        RECT 896.000 149.640 900.000 150.240 ;
    END
  END s_axi_araddr[20]
  PIN s_axi_araddr[21]
    DIRECTION INPUT ;
    USE SIGNAL ;
    ANTENNAGATEAREA 0.196500 ;
    PORT
      LAYER met3 ;
        RECT 896.000 309.440 900.000 310.040 ;
    END
  END s_axi_araddr[21]
  PIN s_axi_araddr[22]
    DIRECTION INPUT ;
    USE SIGNAL ;
    ANTENNAGATEAREA 0.213000 ;
    PORT
      LAYER met2 ;
        RECT 573.250 896.000 573.530 900.000 ;
    END
  END s_axi_araddr[22]
  PIN s_axi_araddr[23]
    DIRECTION INPUT ;
    USE SIGNAL ;
    ANTENNAGATEAREA 0.196500 ;
    PORT
      LAYER met3 ;
        RECT 896.000 227.840 900.000 228.440 ;
    END
  END s_axi_araddr[23]
  PIN s_axi_araddr[24]
    DIRECTION INPUT ;
    USE SIGNAL ;
    ANTENNAGATEAREA 0.196500 ;
    PORT
      LAYER met3 ;
        RECT 896.000 428.440 900.000 429.040 ;
    END
  END s_axi_araddr[24]
  PIN s_axi_araddr[25]
    DIRECTION INPUT ;
    USE SIGNAL ;
    ANTENNAGATEAREA 0.196500 ;
    PORT
      LAYER met3 ;
        RECT 896.000 224.440 900.000 225.040 ;
    END
  END s_axi_araddr[25]
  PIN s_axi_araddr[26]
    DIRECTION INPUT ;
    USE SIGNAL ;
    ANTENNAGATEAREA 0.213000 ;
    PORT
      LAYER met3 ;
        RECT 896.000 122.440 900.000 123.040 ;
    END
  END s_axi_araddr[26]
  PIN s_axi_araddr[27]
    DIRECTION INPUT ;
    USE SIGNAL ;
    ANTENNAGATEAREA 0.196500 ;
    PORT
      LAYER met3 ;
        RECT 896.000 153.040 900.000 153.640 ;
    END
  END s_axi_araddr[27]
  PIN s_axi_araddr[28]
    DIRECTION INPUT ;
    USE SIGNAL ;
    ANTENNAGATEAREA 0.126000 ;
    PORT
      LAYER met3 ;
        RECT 896.000 238.040 900.000 238.640 ;
    END
  END s_axi_araddr[28]
  PIN s_axi_araddr[29]
    DIRECTION INPUT ;
    USE SIGNAL ;
    ANTENNAGATEAREA 0.213000 ;
    PORT
      LAYER met2 ;
        RECT 563.590 896.000 563.870 900.000 ;
    END
  END s_axi_araddr[29]
  PIN s_axi_araddr[2]
    DIRECTION INPUT ;
    USE SIGNAL ;
    ANTENNAGATEAREA 0.196500 ;
    PORT
      LAYER met2 ;
        RECT 856.610 896.000 856.890 900.000 ;
    END
  END s_axi_araddr[2]
  PIN s_axi_araddr[30]
    DIRECTION INPUT ;
    USE SIGNAL ;
    ANTENNAGATEAREA 0.213000 ;
    PORT
      LAYER met2 ;
        RECT 666.630 896.000 666.910 900.000 ;
    END
  END s_axi_araddr[30]
  PIN s_axi_araddr[31]
    DIRECTION INPUT ;
    USE SIGNAL ;
    ANTENNAGATEAREA 0.196500 ;
    PORT
      LAYER met3 ;
        RECT 896.000 401.240 900.000 401.840 ;
    END
  END s_axi_araddr[31]
  PIN s_axi_araddr[32]
    DIRECTION INPUT ;
    USE SIGNAL ;
    ANTENNAGATEAREA 0.196500 ;
    PORT
      LAYER met2 ;
        RECT 679.510 896.000 679.790 900.000 ;
    END
  END s_axi_araddr[32]
  PIN s_axi_araddr[33]
    DIRECTION INPUT ;
    USE SIGNAL ;
    ANTENNAGATEAREA 0.126000 ;
    PORT
      LAYER met2 ;
        RECT 875.930 896.000 876.210 900.000 ;
    END
  END s_axi_araddr[33]
  PIN s_axi_araddr[34]
    DIRECTION INPUT ;
    USE SIGNAL ;
    ANTENNAGATEAREA 0.196500 ;
    PORT
      LAYER met2 ;
        RECT 586.130 896.000 586.410 900.000 ;
    END
  END s_axi_araddr[34]
  PIN s_axi_araddr[35]
    DIRECTION INPUT ;
    USE SIGNAL ;
    ANTENNAGATEAREA 0.126000 ;
    PORT
      LAYER met2 ;
        RECT 756.790 896.000 757.070 900.000 ;
    END
  END s_axi_araddr[35]
  PIN s_axi_araddr[36]
    DIRECTION INPUT ;
    USE SIGNAL ;
    ANTENNAGATEAREA 0.126000 ;
    PORT
      LAYER met2 ;
        RECT 618.330 896.000 618.610 900.000 ;
    END
  END s_axi_araddr[36]
  PIN s_axi_araddr[37]
    DIRECTION INPUT ;
    USE SIGNAL ;
    ANTENNAGATEAREA 0.126000 ;
    PORT
      LAYER met2 ;
        RECT 605.450 896.000 605.730 900.000 ;
    END
  END s_axi_araddr[37]
  PIN s_axi_araddr[38]
    DIRECTION INPUT ;
    USE SIGNAL ;
    ANTENNAGATEAREA 0.196500 ;
    PORT
      LAYER met2 ;
        RECT 676.290 896.000 676.570 900.000 ;
    END
  END s_axi_araddr[38]
  PIN s_axi_araddr[39]
    DIRECTION INPUT ;
    USE SIGNAL ;
    ANTENNAGATEAREA 0.196500 ;
    PORT
      LAYER met2 ;
        RECT 740.690 896.000 740.970 900.000 ;
    END
  END s_axi_araddr[39]
  PIN s_axi_araddr[3]
    DIRECTION INPUT ;
    USE SIGNAL ;
    ANTENNAGATEAREA 0.196500 ;
    PORT
      LAYER met2 ;
        RECT 817.970 896.000 818.250 900.000 ;
    END
  END s_axi_araddr[3]
  PIN s_axi_araddr[40]
    DIRECTION INPUT ;
    USE SIGNAL ;
    ANTENNAGATEAREA 0.126000 ;
    PORT
      LAYER met2 ;
        RECT 682.730 896.000 683.010 900.000 ;
    END
  END s_axi_araddr[40]
  PIN s_axi_araddr[41]
    DIRECTION INPUT ;
    USE SIGNAL ;
    ANTENNAGATEAREA 0.196500 ;
    PORT
      LAYER met2 ;
        RECT 634.430 896.000 634.710 900.000 ;
    END
  END s_axi_araddr[41]
  PIN s_axi_araddr[42]
    DIRECTION INPUT ;
    USE SIGNAL ;
    ANTENNAGATEAREA 0.126000 ;
    PORT
      LAYER met2 ;
        RECT 727.810 896.000 728.090 900.000 ;
    END
  END s_axi_araddr[42]
  PIN s_axi_araddr[43]
    DIRECTION INPUT ;
    USE SIGNAL ;
    ANTENNAGATEAREA 0.196500 ;
    PORT
      LAYER met3 ;
        RECT 896.000 340.040 900.000 340.640 ;
    END
  END s_axi_araddr[43]
  PIN s_axi_araddr[44]
    DIRECTION INPUT ;
    USE SIGNAL ;
    ANTENNAGATEAREA 0.196500 ;
    PORT
      LAYER met2 ;
        RECT 734.250 896.000 734.530 900.000 ;
    END
  END s_axi_araddr[44]
  PIN s_axi_araddr[45]
    DIRECTION INPUT ;
    USE SIGNAL ;
    ANTENNAGATEAREA 0.126000 ;
    PORT
      LAYER met2 ;
        RECT 637.650 896.000 637.930 900.000 ;
    END
  END s_axi_araddr[45]
  PIN s_axi_araddr[46]
    DIRECTION INPUT ;
    USE SIGNAL ;
    ANTENNAGATEAREA 0.196500 ;
    PORT
      LAYER met2 ;
        RECT 718.150 896.000 718.430 900.000 ;
    END
  END s_axi_araddr[46]
  PIN s_axi_araddr[47]
    DIRECTION INPUT ;
    USE SIGNAL ;
    ANTENNAGATEAREA 0.126000 ;
    ANTENNADIFFAREA 0.434700 ;
    PORT
      LAYER met3 ;
        RECT 896.000 503.240 900.000 503.840 ;
    END
  END s_axi_araddr[47]
  PIN s_axi_araddr[48]
    DIRECTION INPUT ;
    USE SIGNAL ;
    ANTENNAGATEAREA 0.196500 ;
    PORT
      LAYER met2 ;
        RECT 869.490 896.000 869.770 900.000 ;
    END
  END s_axi_araddr[48]
  PIN s_axi_araddr[49]
    DIRECTION INPUT ;
    USE SIGNAL ;
    ANTENNAGATEAREA 0.196500 ;
    PORT
      LAYER met2 ;
        RECT 760.010 896.000 760.290 900.000 ;
    END
  END s_axi_araddr[49]
  PIN s_axi_araddr[4]
    DIRECTION INPUT ;
    USE SIGNAL ;
    ANTENNAGATEAREA 0.196500 ;
    PORT
      LAYER met2 ;
        RECT 821.190 896.000 821.470 900.000 ;
    END
  END s_axi_araddr[4]
  PIN s_axi_araddr[50]
    DIRECTION INPUT ;
    USE SIGNAL ;
    ANTENNAGATEAREA 0.196500 ;
    PORT
      LAYER met2 ;
        RECT 898.470 896.000 898.750 900.000 ;
    END
  END s_axi_araddr[50]
  PIN s_axi_araddr[51]
    DIRECTION INPUT ;
    USE SIGNAL ;
    ANTENNAGATEAREA 0.159000 ;
    PORT
      LAYER met2 ;
        RECT 466.990 896.000 467.270 900.000 ;
    END
  END s_axi_araddr[51]
  PIN s_axi_araddr[52]
    DIRECTION INPUT ;
    USE SIGNAL ;
    ANTENNAGATEAREA 0.196500 ;
    PORT
      LAYER met3 ;
        RECT 896.000 336.640 900.000 337.240 ;
    END
  END s_axi_araddr[52]
  PIN s_axi_araddr[53]
    DIRECTION INPUT ;
    USE SIGNAL ;
    ANTENNAGATEAREA 0.196500 ;
    PORT
      LAYER met3 ;
        RECT 896.000 299.240 900.000 299.840 ;
    END
  END s_axi_araddr[53]
  PIN s_axi_araddr[54]
    DIRECTION INPUT ;
    USE SIGNAL ;
    ANTENNAGATEAREA 0.213000 ;
    PORT
      LAYER met2 ;
        RECT 576.470 896.000 576.750 900.000 ;
    END
  END s_axi_araddr[54]
  PIN s_axi_araddr[55]
    DIRECTION INPUT ;
    USE SIGNAL ;
    ANTENNAGATEAREA 0.196500 ;
    PORT
      LAYER met3 ;
        RECT 896.000 363.840 900.000 364.440 ;
    END
  END s_axi_araddr[55]
  PIN s_axi_araddr[56]
    DIRECTION INPUT ;
    USE SIGNAL ;
    ANTENNAGATEAREA 0.196500 ;
    PORT
      LAYER met3 ;
        RECT 896.000 435.240 900.000 435.840 ;
    END
  END s_axi_araddr[56]
  PIN s_axi_araddr[57]
    DIRECTION INPUT ;
    USE SIGNAL ;
    ANTENNAGATEAREA 0.196500 ;
    PORT
      LAYER met3 ;
        RECT 896.000 221.040 900.000 221.640 ;
    END
  END s_axi_araddr[57]
  PIN s_axi_araddr[58]
    DIRECTION INPUT ;
    USE SIGNAL ;
    ANTENNAGATEAREA 0.196500 ;
    PORT
      LAYER met3 ;
        RECT 896.000 384.240 900.000 384.840 ;
    END
  END s_axi_araddr[58]
  PIN s_axi_araddr[59]
    DIRECTION INPUT ;
    USE SIGNAL ;
    ANTENNAGATEAREA 0.196500 ;
    PORT
      LAYER met3 ;
        RECT 896.000 207.440 900.000 208.040 ;
    END
  END s_axi_araddr[59]
  PIN s_axi_araddr[5]
    DIRECTION INPUT ;
    USE SIGNAL ;
    ANTENNAGATEAREA 0.196500 ;
    PORT
      LAYER met2 ;
        RECT 698.830 896.000 699.110 900.000 ;
    END
  END s_axi_araddr[5]
  PIN s_axi_araddr[60]
    DIRECTION INPUT ;
    USE SIGNAL ;
    ANTENNAGATEAREA 0.196500 ;
    PORT
      LAYER met3 ;
        RECT 896.000 333.240 900.000 333.840 ;
    END
  END s_axi_araddr[60]
  PIN s_axi_araddr[61]
    DIRECTION INPUT ;
    USE SIGNAL ;
    ANTENNAGATEAREA 0.213000 ;
    PORT
      LAYER met2 ;
        RECT 566.810 896.000 567.090 900.000 ;
    END
  END s_axi_araddr[61]
  PIN s_axi_araddr[62]
    DIRECTION INPUT ;
    USE SIGNAL ;
    ANTENNAGATEAREA 0.196500 ;
    PORT
      LAYER met2 ;
        RECT 795.430 896.000 795.710 900.000 ;
    END
  END s_axi_araddr[62]
  PIN s_axi_araddr[63]
    DIRECTION INPUT ;
    USE SIGNAL ;
    ANTENNAGATEAREA 0.196500 ;
    PORT
      LAYER met3 ;
        RECT 896.000 418.240 900.000 418.840 ;
    END
  END s_axi_araddr[63]
  PIN s_axi_araddr[64]
    DIRECTION INPUT ;
    USE SIGNAL ;
    ANTENNAGATEAREA 0.196500 ;
    PORT
      LAYER met2 ;
        RECT 830.850 896.000 831.130 900.000 ;
    END
  END s_axi_araddr[64]
  PIN s_axi_araddr[65]
    DIRECTION INPUT ;
    USE SIGNAL ;
    ANTENNAGATEAREA 0.196500 ;
    PORT
      LAYER met2 ;
        RECT 673.070 896.000 673.350 900.000 ;
    END
  END s_axi_araddr[65]
  PIN s_axi_araddr[66]
    DIRECTION INPUT ;
    USE SIGNAL ;
    ANTENNAGATEAREA 0.196500 ;
    PORT
      LAYER met2 ;
        RECT 837.290 896.000 837.570 900.000 ;
    END
  END s_axi_araddr[66]
  PIN s_axi_araddr[67]
    DIRECTION INPUT ;
    USE SIGNAL ;
    ANTENNAGATEAREA 0.196500 ;
    PORT
      LAYER met2 ;
        RECT 595.790 896.000 596.070 900.000 ;
    END
  END s_axi_araddr[67]
  PIN s_axi_araddr[68]
    DIRECTION INPUT ;
    USE SIGNAL ;
    ANTENNAGATEAREA 0.196500 ;
    PORT
      LAYER met2 ;
        RECT 814.750 896.000 815.030 900.000 ;
    END
  END s_axi_araddr[68]
  PIN s_axi_araddr[69]
    DIRECTION INPUT ;
    USE SIGNAL ;
    ANTENNAGATEAREA 0.196500 ;
    PORT
      LAYER met2 ;
        RECT 702.050 896.000 702.330 900.000 ;
    END
  END s_axi_araddr[69]
  PIN s_axi_araddr[6]
    DIRECTION INPUT ;
    USE SIGNAL ;
    ANTENNAGATEAREA 0.196500 ;
    PORT
      LAYER met2 ;
        RECT 753.570 896.000 753.850 900.000 ;
    END
  END s_axi_araddr[6]
  PIN s_axi_araddr[70]
    DIRECTION INPUT ;
    USE SIGNAL ;
    ANTENNAGATEAREA 0.196500 ;
    PORT
      LAYER met2 ;
        RECT 853.390 896.000 853.670 900.000 ;
    END
  END s_axi_araddr[70]
  PIN s_axi_araddr[71]
    DIRECTION INPUT ;
    USE SIGNAL ;
    ANTENNAGATEAREA 0.196500 ;
    PORT
      LAYER met2 ;
        RECT 850.170 896.000 850.450 900.000 ;
    END
  END s_axi_araddr[71]
  PIN s_axi_araddr[72]
    DIRECTION INPUT ;
    USE SIGNAL ;
    ANTENNAGATEAREA 0.196500 ;
    PORT
      LAYER met2 ;
        RECT 769.670 896.000 769.950 900.000 ;
    END
  END s_axi_araddr[72]
  PIN s_axi_araddr[73]
    DIRECTION INPUT ;
    USE SIGNAL ;
    ANTENNAGATEAREA 0.196500 ;
    PORT
      LAYER met2 ;
        RECT 711.710 896.000 711.990 900.000 ;
    END
  END s_axi_araddr[73]
  PIN s_axi_araddr[74]
    DIRECTION INPUT ;
    USE SIGNAL ;
    ANTENNAGATEAREA 0.196500 ;
    PORT
      LAYER met2 ;
        RECT 782.550 896.000 782.830 900.000 ;
    END
  END s_axi_araddr[74]
  PIN s_axi_araddr[75]
    DIRECTION INPUT ;
    USE SIGNAL ;
    ANTENNAGATEAREA 0.196500 ;
    PORT
      LAYER met3 ;
        RECT 896.000 493.040 900.000 493.640 ;
    END
  END s_axi_araddr[75]
  PIN s_axi_araddr[76]
    DIRECTION INPUT ;
    USE SIGNAL ;
    ANTENNAGATEAREA 0.196500 ;
    PORT
      LAYER met2 ;
        RECT 827.630 896.000 827.910 900.000 ;
    END
  END s_axi_araddr[76]
  PIN s_axi_araddr[77]
    DIRECTION INPUT ;
    USE SIGNAL ;
    ANTENNAGATEAREA 0.196500 ;
    PORT
      LAYER met2 ;
        RECT 647.310 896.000 647.590 900.000 ;
    END
  END s_axi_araddr[77]
  PIN s_axi_araddr[78]
    DIRECTION INPUT ;
    USE SIGNAL ;
    ANTENNAGATEAREA 0.213000 ;
    PORT
      LAYER met3 ;
        RECT 896.000 496.440 900.000 497.040 ;
    END
  END s_axi_araddr[78]
  PIN s_axi_araddr[79]
    DIRECTION INPUT ;
    USE SIGNAL ;
    ANTENNAGATEAREA 0.159000 ;
    PORT
      LAYER met3 ;
        RECT 896.000 163.240 900.000 163.840 ;
    END
  END s_axi_araddr[79]
  PIN s_axi_araddr[7]
    DIRECTION INPUT ;
    USE SIGNAL ;
    ANTENNAGATEAREA 0.196500 ;
    PORT
      LAYER met2 ;
        RECT 695.610 896.000 695.890 900.000 ;
    END
  END s_axi_araddr[7]
  PIN s_axi_araddr[80]
    DIRECTION INPUT ;
    USE SIGNAL ;
    ANTENNAGATEAREA 0.196500 ;
    PORT
      LAYER met2 ;
        RECT 763.230 896.000 763.510 900.000 ;
    END
  END s_axi_araddr[80]
  PIN s_axi_araddr[81]
    DIRECTION INPUT ;
    USE SIGNAL ;
    ANTENNAGATEAREA 0.196500 ;
    PORT
      LAYER met2 ;
        RECT 879.150 896.000 879.430 900.000 ;
    END
  END s_axi_araddr[81]
  PIN s_axi_araddr[82]
    DIRECTION INPUT ;
    USE SIGNAL ;
    ANTENNAGATEAREA 0.196500 ;
    PORT
      LAYER met2 ;
        RECT 892.030 896.000 892.310 900.000 ;
    END
  END s_axi_araddr[82]
  PIN s_axi_araddr[83]
    DIRECTION INPUT ;
    USE SIGNAL ;
    ANTENNAGATEAREA 0.213000 ;
    PORT
      LAYER met2 ;
        RECT 653.750 896.000 654.030 900.000 ;
    END
  END s_axi_araddr[83]
  PIN s_axi_araddr[84]
    DIRECTION INPUT ;
    USE SIGNAL ;
    ANTENNAGATEAREA 0.196500 ;
    PORT
      LAYER met3 ;
        RECT 896.000 200.640 900.000 201.240 ;
    END
  END s_axi_araddr[84]
  PIN s_axi_araddr[85]
    DIRECTION INPUT ;
    USE SIGNAL ;
    ANTENNAGATEAREA 0.196500 ;
    PORT
      LAYER met3 ;
        RECT 896.000 210.840 900.000 211.440 ;
    END
  END s_axi_araddr[85]
  PIN s_axi_araddr[86]
    DIRECTION INPUT ;
    USE SIGNAL ;
    ANTENNAGATEAREA 0.196500 ;
    PORT
      LAYER met3 ;
        RECT 896.000 115.640 900.000 116.240 ;
    END
  END s_axi_araddr[86]
  PIN s_axi_araddr[87]
    DIRECTION INPUT ;
    USE SIGNAL ;
    ANTENNAGATEAREA 0.196500 ;
    PORT
      LAYER met3 ;
        RECT 896.000 248.240 900.000 248.840 ;
    END
  END s_axi_araddr[87]
  PIN s_axi_araddr[88]
    DIRECTION INPUT ;
    USE SIGNAL ;
    ANTENNAGATEAREA 0.196500 ;
    PORT
      LAYER met3 ;
        RECT 896.000 289.040 900.000 289.640 ;
    END
  END s_axi_araddr[88]
  PIN s_axi_araddr[89]
    DIRECTION INPUT ;
    USE SIGNAL ;
    ANTENNAGATEAREA 0.196500 ;
    PORT
      LAYER met3 ;
        RECT 896.000 278.840 900.000 279.440 ;
    END
  END s_axi_araddr[89]
  PIN s_axi_araddr[8]
    DIRECTION INPUT ;
    USE SIGNAL ;
    ANTENNAGATEAREA 0.196500 ;
    PORT
      LAYER met2 ;
        RECT 772.890 896.000 773.170 900.000 ;
    END
  END s_axi_araddr[8]
  PIN s_axi_araddr[90]
    DIRECTION INPUT ;
    USE SIGNAL ;
    ANTENNAGATEAREA 0.196500 ;
    PORT
      LAYER met3 ;
        RECT 896.000 353.640 900.000 354.240 ;
    END
  END s_axi_araddr[90]
  PIN s_axi_araddr[91]
    DIRECTION INPUT ;
    USE SIGNAL ;
    ANTENNAGATEAREA 0.196500 ;
    PORT
      LAYER met3 ;
        RECT 896.000 255.040 900.000 255.640 ;
    END
  END s_axi_araddr[91]
  PIN s_axi_araddr[92]
    DIRECTION INPUT ;
    USE SIGNAL ;
    ANTENNAGATEAREA 0.196500 ;
    PORT
      LAYER met3 ;
        RECT 896.000 136.040 900.000 136.640 ;
    END
  END s_axi_araddr[92]
  PIN s_axi_araddr[93]
    DIRECTION INPUT ;
    USE SIGNAL ;
    ANTENNAGATEAREA 0.196500 ;
    PORT
      LAYER met3 ;
        RECT 896.000 231.240 900.000 231.840 ;
    END
  END s_axi_araddr[93]
  PIN s_axi_araddr[94]
    DIRECTION INPUT ;
    USE SIGNAL ;
    ANTENNAGATEAREA 0.126000 ;
    ANTENNADIFFAREA 0.434700 ;
    PORT
      LAYER met3 ;
        RECT 896.000 61.240 900.000 61.840 ;
    END
  END s_axi_araddr[94]
  PIN s_axi_araddr[95]
    DIRECTION INPUT ;
    USE SIGNAL ;
    ANTENNAGATEAREA 0.196500 ;
    PORT
      LAYER met3 ;
        RECT 896.000 438.640 900.000 439.240 ;
    END
  END s_axi_araddr[95]
  PIN s_axi_araddr[96]
    DIRECTION INPUT ;
    USE SIGNAL ;
    ANTENNAGATEAREA 0.196500 ;
    PORT
      LAYER met2 ;
        RECT 798.650 896.000 798.930 900.000 ;
    END
  END s_axi_araddr[96]
  PIN s_axi_araddr[97]
    DIRECTION INPUT ;
    USE SIGNAL ;
    ANTENNAGATEAREA 0.126000 ;
    PORT
      LAYER met2 ;
        RECT 724.590 896.000 724.870 900.000 ;
    END
  END s_axi_araddr[97]
  PIN s_axi_araddr[98]
    DIRECTION INPUT ;
    USE SIGNAL ;
    ANTENNAGATEAREA 0.126000 ;
    PORT
      LAYER met2 ;
        RECT 731.030 896.000 731.310 900.000 ;
    END
  END s_axi_araddr[98]
  PIN s_axi_araddr[99]
    DIRECTION INPUT ;
    USE SIGNAL ;
    ANTENNAGATEAREA 0.196500 ;
    PORT
      LAYER met2 ;
        RECT 589.350 896.000 589.630 900.000 ;
    END
  END s_axi_araddr[99]
  PIN s_axi_araddr[9]
    DIRECTION INPUT ;
    USE SIGNAL ;
    ANTENNAGATEAREA 0.196500 ;
    PORT
      LAYER met2 ;
        RECT 663.410 896.000 663.690 900.000 ;
    END
  END s_axi_araddr[9]
  PIN s_axi_arprot[0]
    DIRECTION INPUT ;
    USE SIGNAL ;
    ANTENNAGATEAREA 0.126000 ;
    PORT
      LAYER met2 ;
        RECT 840.510 896.000 840.790 900.000 ;
    END
  END s_axi_arprot[0]
  PIN s_axi_arprot[10]
    DIRECTION INPUT ;
    USE SIGNAL ;
    ANTENNAGATEAREA 0.213000 ;
    PORT
      LAYER met2 ;
        RECT 599.010 896.000 599.290 900.000 ;
    END
  END s_axi_arprot[10]
  PIN s_axi_arprot[11]
    DIRECTION INPUT ;
    USE SIGNAL ;
    ANTENNAGATEAREA 0.196500 ;
    PORT
      LAYER met3 ;
        RECT 896.000 615.440 900.000 616.040 ;
    END
  END s_axi_arprot[11]
  PIN s_axi_arprot[1]
    DIRECTION INPUT ;
    USE SIGNAL ;
    ANTENNAGATEAREA 0.196500 ;
    PORT
      LAYER met3 ;
        RECT 896.000 601.840 900.000 602.440 ;
    END
  END s_axi_arprot[1]
  PIN s_axi_arprot[2]
    DIRECTION INPUT ;
    USE SIGNAL ;
    ANTENNAGATEAREA 0.196500 ;
    PORT
      LAYER met3 ;
        RECT 896.000 595.040 900.000 595.640 ;
    END
  END s_axi_arprot[2]
  PIN s_axi_arprot[3]
    DIRECTION INPUT ;
    USE SIGNAL ;
    ANTENNAGATEAREA 0.126000 ;
    ANTENNADIFFAREA 0.434700 ;
    PORT
      LAYER met3 ;
        RECT 896.000 591.640 900.000 592.240 ;
    END
  END s_axi_arprot[3]
  PIN s_axi_arprot[4]
    DIRECTION INPUT ;
    USE SIGNAL ;
    ANTENNAGATEAREA 0.126000 ;
    PORT
      LAYER met3 ;
        RECT 896.000 612.040 900.000 612.640 ;
    END
  END s_axi_arprot[4]
  PIN s_axi_arprot[5]
    DIRECTION INPUT ;
    USE SIGNAL ;
    ANTENNAGATEAREA 0.126000 ;
    PORT
      LAYER met3 ;
        RECT 896.000 639.240 900.000 639.840 ;
    END
  END s_axi_arprot[5]
  PIN s_axi_arprot[6]
    DIRECTION INPUT ;
    USE SIGNAL ;
    ANTENNAGATEAREA 0.196500 ;
    PORT
      LAYER met3 ;
        RECT 896.000 642.640 900.000 643.240 ;
    END
  END s_axi_arprot[6]
  PIN s_axi_arprot[7]
    DIRECTION INPUT ;
    USE SIGNAL ;
    ANTENNAGATEAREA 0.196500 ;
    PORT
      LAYER met3 ;
        RECT 896.000 608.640 900.000 609.240 ;
    END
  END s_axi_arprot[7]
  PIN s_axi_arprot[8]
    DIRECTION INPUT ;
    USE SIGNAL ;
    ANTENNAGATEAREA 0.196500 ;
    PORT
      LAYER met3 ;
        RECT 896.000 649.440 900.000 650.040 ;
    END
  END s_axi_arprot[8]
  PIN s_axi_arprot[9]
    DIRECTION INPUT ;
    USE SIGNAL ;
    ANTENNAGATEAREA 0.196500 ;
    PORT
      LAYER met3 ;
        RECT 896.000 625.640 900.000 626.240 ;
    END
  END s_axi_arprot[9]
  PIN s_axi_arready[0]
    DIRECTION OUTPUT ;
    USE SIGNAL ;
    ANTENNADIFFAREA 0.340600 ;
    PORT
      LAYER met3 ;
        RECT 896.000 374.040 900.000 374.640 ;
    END
  END s_axi_arready[0]
  PIN s_axi_arready[1]
    DIRECTION OUTPUT ;
    USE SIGNAL ;
    ANTENNADIFFAREA 0.340600 ;
    PORT
      LAYER met3 ;
        RECT 896.000 506.640 900.000 507.240 ;
    END
  END s_axi_arready[1]
  PIN s_axi_arready[2]
    DIRECTION OUTPUT ;
    USE SIGNAL ;
    ANTENNADIFFAREA 0.340600 ;
    PORT
      LAYER met3 ;
        RECT 896.000 350.240 900.000 350.840 ;
    END
  END s_axi_arready[2]
  PIN s_axi_arready[3]
    DIRECTION OUTPUT ;
    USE SIGNAL ;
    ANTENNADIFFAREA 0.340600 ;
    PORT
      LAYER met3 ;
        RECT 896.000 146.240 900.000 146.840 ;
    END
  END s_axi_arready[3]
  PIN s_axi_arvalid[0]
    DIRECTION INPUT ;
    USE SIGNAL ;
    ANTENNAGATEAREA 0.213000 ;
    PORT
      LAYER met3 ;
        RECT 896.000 166.640 900.000 167.240 ;
    END
  END s_axi_arvalid[0]
  PIN s_axi_arvalid[1]
    DIRECTION INPUT ;
    USE SIGNAL ;
    ANTENNAGATEAREA 0.126000 ;
    PORT
      LAYER met3 ;
        RECT 896.000 251.640 900.000 252.240 ;
    END
  END s_axi_arvalid[1]
  PIN s_axi_arvalid[2]
    DIRECTION INPUT ;
    USE SIGNAL ;
    ANTENNAGATEAREA 0.126000 ;
    PORT
      LAYER met3 ;
        RECT 896.000 180.240 900.000 180.840 ;
    END
  END s_axi_arvalid[2]
  PIN s_axi_arvalid[3]
    DIRECTION INPUT ;
    USE SIGNAL ;
    ANTENNAGATEAREA 0.126000 ;
    PORT
      LAYER met3 ;
        RECT 896.000 81.640 900.000 82.240 ;
    END
  END s_axi_arvalid[3]
  PIN s_axi_awaddr[0]
    DIRECTION INPUT ;
    USE SIGNAL ;
    ANTENNAGATEAREA 0.126000 ;
    PORT
      LAYER met3 ;
        RECT 0.000 282.240 4.000 282.840 ;
    END
  END s_axi_awaddr[0]
  PIN s_axi_awaddr[100]
    DIRECTION INPUT ;
    USE SIGNAL ;
    ANTENNAGATEAREA 0.126000 ;
    PORT
      LAYER met2 ;
        RECT 125.670 0.000 125.950 4.000 ;
    END
  END s_axi_awaddr[100]
  PIN s_axi_awaddr[101]
    DIRECTION INPUT ;
    USE SIGNAL ;
    ANTENNAGATEAREA 0.126000 ;
    PORT
      LAYER met3 ;
        RECT 0.000 309.440 4.000 310.040 ;
    END
  END s_axi_awaddr[101]
  PIN s_axi_awaddr[102]
    DIRECTION INPUT ;
    USE SIGNAL ;
    ANTENNAGATEAREA 0.126000 ;
    PORT
      LAYER met2 ;
        RECT 238.370 0.000 238.650 4.000 ;
    END
  END s_axi_awaddr[102]
  PIN s_axi_awaddr[103]
    DIRECTION INPUT ;
    USE SIGNAL ;
    ANTENNAGATEAREA 0.126000 ;
    PORT
      LAYER met2 ;
        RECT 254.470 0.000 254.750 4.000 ;
    END
  END s_axi_awaddr[103]
  PIN s_axi_awaddr[104]
    DIRECTION INPUT ;
    USE SIGNAL ;
    ANTENNAGATEAREA 0.126000 ;
    PORT
      LAYER met2 ;
        RECT 357.510 0.000 357.790 4.000 ;
    END
  END s_axi_awaddr[104]
  PIN s_axi_awaddr[105]
    DIRECTION INPUT ;
    USE SIGNAL ;
    ANTENNAGATEAREA 0.126000 ;
    PORT
      LAYER met2 ;
        RECT 177.190 0.000 177.470 4.000 ;
    END
  END s_axi_awaddr[105]
  PIN s_axi_awaddr[106]
    DIRECTION INPUT ;
    USE SIGNAL ;
    ANTENNAGATEAREA 0.126000 ;
    PORT
      LAYER met3 ;
        RECT 0.000 343.440 4.000 344.040 ;
    END
  END s_axi_awaddr[106]
  PIN s_axi_awaddr[107]
    DIRECTION INPUT ;
    USE SIGNAL ;
    ANTENNAGATEAREA 0.126000 ;
    PORT
      LAYER met3 ;
        RECT 0.000 360.440 4.000 361.040 ;
    END
  END s_axi_awaddr[107]
  PIN s_axi_awaddr[108]
    DIRECTION INPUT ;
    USE SIGNAL ;
    ANTENNAGATEAREA 0.126000 ;
    PORT
      LAYER met3 ;
        RECT 0.000 329.840 4.000 330.440 ;
    END
  END s_axi_awaddr[108]
  PIN s_axi_awaddr[109]
    DIRECTION INPUT ;
    USE SIGNAL ;
    ANTENNAGATEAREA 0.126000 ;
    PORT
      LAYER met2 ;
        RECT 151.430 0.000 151.710 4.000 ;
    END
  END s_axi_awaddr[109]
  PIN s_axi_awaddr[10]
    DIRECTION INPUT ;
    USE SIGNAL ;
    ANTENNAGATEAREA 0.126000 ;
    PORT
      LAYER met2 ;
        RECT 277.010 0.000 277.290 4.000 ;
    END
  END s_axi_awaddr[10]
  PIN s_axi_awaddr[110]
    DIRECTION INPUT ;
    USE SIGNAL ;
    ANTENNAGATEAREA 0.126000 ;
    PORT
      LAYER met2 ;
        RECT 228.710 0.000 228.990 4.000 ;
    END
  END s_axi_awaddr[110]
  PIN s_axi_awaddr[111]
    DIRECTION INPUT ;
    USE SIGNAL ;
    ANTENNAGATEAREA 0.126000 ;
    PORT
      LAYER met2 ;
        RECT 212.610 0.000 212.890 4.000 ;
    END
  END s_axi_awaddr[111]
  PIN s_axi_awaddr[112]
    DIRECTION INPUT ;
    USE SIGNAL ;
    ANTENNAGATEAREA 0.126000 ;
    PORT
      LAYER met2 ;
        RECT 190.070 0.000 190.350 4.000 ;
    END
  END s_axi_awaddr[112]
  PIN s_axi_awaddr[113]
    DIRECTION INPUT ;
    USE SIGNAL ;
    ANTENNAGATEAREA 0.126000 ;
    PORT
      LAYER met2 ;
        RECT 483.090 0.000 483.370 4.000 ;
    END
  END s_axi_awaddr[113]
  PIN s_axi_awaddr[114]
    DIRECTION INPUT ;
    USE SIGNAL ;
    ANTENNAGATEAREA 0.126000 ;
    PORT
      LAYER met2 ;
        RECT 531.390 0.000 531.670 4.000 ;
    END
  END s_axi_awaddr[114]
  PIN s_axi_awaddr[115]
    DIRECTION INPUT ;
    USE SIGNAL ;
    ANTENNAGATEAREA 0.126000 ;
    PORT
      LAYER met2 ;
        RECT 334.970 0.000 335.250 4.000 ;
    END
  END s_axi_awaddr[115]
  PIN s_axi_awaddr[116]
    DIRECTION INPUT ;
    USE SIGNAL ;
    ANTENNAGATEAREA 0.126000 ;
    PORT
      LAYER met2 ;
        RECT 312.430 0.000 312.710 4.000 ;
    END
  END s_axi_awaddr[116]
  PIN s_axi_awaddr[117]
    DIRECTION INPUT ;
    USE SIGNAL ;
    ANTENNAGATEAREA 0.126000 ;
    PORT
      LAYER met2 ;
        RECT 573.250 0.000 573.530 4.000 ;
    END
  END s_axi_awaddr[117]
  PIN s_axi_awaddr[118]
    DIRECTION INPUT ;
    USE SIGNAL ;
    ANTENNAGATEAREA 0.126000 ;
    PORT
      LAYER met2 ;
        RECT 534.610 0.000 534.890 4.000 ;
    END
  END s_axi_awaddr[118]
  PIN s_axi_awaddr[119]
    DIRECTION INPUT ;
    USE SIGNAL ;
    ANTENNAGATEAREA 0.126000 ;
    PORT
      LAYER met2 ;
        RECT 331.750 0.000 332.030 4.000 ;
    END
  END s_axi_awaddr[119]
  PIN s_axi_awaddr[11]
    DIRECTION INPUT ;
    USE SIGNAL ;
    ANTENNAGATEAREA 0.126000 ;
    PORT
      LAYER met2 ;
        RECT 289.890 0.000 290.170 4.000 ;
    END
  END s_axi_awaddr[11]
  PIN s_axi_awaddr[120]
    DIRECTION INPUT ;
    USE SIGNAL ;
    ANTENNAGATEAREA 0.126000 ;
    PORT
      LAYER met2 ;
        RECT 193.290 0.000 193.570 4.000 ;
    END
  END s_axi_awaddr[120]
  PIN s_axi_awaddr[121]
    DIRECTION INPUT ;
    USE SIGNAL ;
    ANTENNAGATEAREA 0.126000 ;
    PORT
      LAYER met2 ;
        RECT 396.150 0.000 396.430 4.000 ;
    END
  END s_axi_awaddr[121]
  PIN s_axi_awaddr[122]
    DIRECTION INPUT ;
    USE SIGNAL ;
    ANTENNAGATEAREA 0.126000 ;
    PORT
      LAYER met2 ;
        RECT 621.550 0.000 621.830 4.000 ;
    END
  END s_axi_awaddr[122]
  PIN s_axi_awaddr[123]
    DIRECTION INPUT ;
    USE SIGNAL ;
    ANTENNAGATEAREA 0.126000 ;
    PORT
      LAYER met2 ;
        RECT 392.930 0.000 393.210 4.000 ;
    END
  END s_axi_awaddr[123]
  PIN s_axi_awaddr[124]
    DIRECTION INPUT ;
    USE SIGNAL ;
    ANTENNAGATEAREA 0.126000 ;
    PORT
      LAYER met2 ;
        RECT 489.530 0.000 489.810 4.000 ;
    END
  END s_axi_awaddr[124]
  PIN s_axi_awaddr[125]
    DIRECTION INPUT ;
    USE SIGNAL ;
    ANTENNAGATEAREA 0.126000 ;
    PORT
      LAYER met2 ;
        RECT 550.710 0.000 550.990 4.000 ;
    END
  END s_axi_awaddr[125]
  PIN s_axi_awaddr[126]
    DIRECTION INPUT ;
    USE SIGNAL ;
    ANTENNAGATEAREA 0.126000 ;
    PORT
      LAYER met2 ;
        RECT 499.190 0.000 499.470 4.000 ;
    END
  END s_axi_awaddr[126]
  PIN s_axi_awaddr[127]
    DIRECTION INPUT ;
    USE SIGNAL ;
    ANTENNAGATEAREA 0.126000 ;
    PORT
      LAYER met2 ;
        RECT 402.590 0.000 402.870 4.000 ;
    END
  END s_axi_awaddr[127]
  PIN s_axi_awaddr[12]
    DIRECTION INPUT ;
    USE SIGNAL ;
    ANTENNAGATEAREA 0.126000 ;
    PORT
      LAYER met2 ;
        RECT 251.250 0.000 251.530 4.000 ;
    END
  END s_axi_awaddr[12]
  PIN s_axi_awaddr[13]
    DIRECTION INPUT ;
    USE SIGNAL ;
    ANTENNAGATEAREA 0.126000 ;
    PORT
      LAYER met2 ;
        RECT 167.530 0.000 167.810 4.000 ;
    END
  END s_axi_awaddr[13]
  PIN s_axi_awaddr[14]
    DIRECTION INPUT ;
    USE SIGNAL ;
    ANTENNAGATEAREA 0.126000 ;
    PORT
      LAYER met2 ;
        RECT 318.870 0.000 319.150 4.000 ;
    END
  END s_axi_awaddr[14]
  PIN s_axi_awaddr[15]
    DIRECTION INPUT ;
    USE SIGNAL ;
    ANTENNAGATEAREA 0.126000 ;
    PORT
      LAYER met2 ;
        RECT 241.590 0.000 241.870 4.000 ;
    END
  END s_axi_awaddr[15]
  PIN s_axi_awaddr[16]
    DIRECTION INPUT ;
    USE SIGNAL ;
    ANTENNAGATEAREA 0.126000 ;
    PORT
      LAYER met2 ;
        RECT 338.190 0.000 338.470 4.000 ;
    END
  END s_axi_awaddr[16]
  PIN s_axi_awaddr[17]
    DIRECTION INPUT ;
    USE SIGNAL ;
    ANTENNAGATEAREA 0.126000 ;
    PORT
      LAYER met2 ;
        RECT 421.910 0.000 422.190 4.000 ;
    END
  END s_axi_awaddr[17]
  PIN s_axi_awaddr[18]
    DIRECTION INPUT ;
    USE SIGNAL ;
    ANTENNAGATEAREA 0.126000 ;
    PORT
      LAYER met2 ;
        RECT 438.010 0.000 438.290 4.000 ;
    END
  END s_axi_awaddr[18]
  PIN s_axi_awaddr[19]
    DIRECTION INPUT ;
    USE SIGNAL ;
    ANTENNAGATEAREA 0.126000 ;
    PORT
      LAYER met2 ;
        RECT 219.050 0.000 219.330 4.000 ;
    END
  END s_axi_awaddr[19]
  PIN s_axi_awaddr[1]
    DIRECTION INPUT ;
    USE SIGNAL ;
    ANTENNAGATEAREA 0.126000 ;
    PORT
      LAYER met3 ;
        RECT 0.000 374.040 4.000 374.640 ;
    END
  END s_axi_awaddr[1]
  PIN s_axi_awaddr[20]
    DIRECTION INPUT ;
    USE SIGNAL ;
    ANTENNAGATEAREA 0.196500 ;
    PORT
      LAYER met2 ;
        RECT 231.930 0.000 232.210 4.000 ;
    END
  END s_axi_awaddr[20]
  PIN s_axi_awaddr[21]
    DIRECTION INPUT ;
    USE SIGNAL ;
    ANTENNAGATEAREA 0.126000 ;
    PORT
      LAYER met3 ;
        RECT 896.000 329.840 900.000 330.440 ;
    END
  END s_axi_awaddr[21]
  PIN s_axi_awaddr[22]
    DIRECTION INPUT ;
    USE SIGNAL ;
    ANTENNAGATEAREA 0.126000 ;
    PORT
      LAYER met2 ;
        RECT 512.070 0.000 512.350 4.000 ;
    END
  END s_axi_awaddr[22]
  PIN s_axi_awaddr[23]
    DIRECTION INPUT ;
    USE SIGNAL ;
    ANTENNAGATEAREA 0.126000 ;
    PORT
      LAYER met2 ;
        RECT 347.850 0.000 348.130 4.000 ;
    END
  END s_axi_awaddr[23]
  PIN s_axi_awaddr[24]
    DIRECTION INPUT ;
    USE SIGNAL ;
    ANTENNAGATEAREA 0.126000 ;
    PORT
      LAYER met2 ;
        RECT 67.710 0.000 67.990 4.000 ;
    END
  END s_axi_awaddr[24]
  PIN s_axi_awaddr[25]
    DIRECTION INPUT ;
    USE SIGNAL ;
    ANTENNAGATEAREA 0.213000 ;
    PORT
      LAYER met3 ;
        RECT 896.000 112.240 900.000 112.840 ;
    END
  END s_axi_awaddr[25]
  PIN s_axi_awaddr[26]
    DIRECTION INPUT ;
    USE SIGNAL ;
    ANTENNAGATEAREA 0.126000 ;
    PORT
      LAYER met2 ;
        RECT 618.330 0.000 618.610 4.000 ;
    END
  END s_axi_awaddr[26]
  PIN s_axi_awaddr[27]
    DIRECTION INPUT ;
    USE SIGNAL ;
    ANTENNAGATEAREA 0.126000 ;
    PORT
      LAYER met2 ;
        RECT 492.750 0.000 493.030 4.000 ;
    END
  END s_axi_awaddr[27]
  PIN s_axi_awaddr[28]
    DIRECTION INPUT ;
    USE SIGNAL ;
    ANTENNAGATEAREA 0.126000 ;
    PORT
      LAYER met2 ;
        RECT 502.410 0.000 502.690 4.000 ;
    END
  END s_axi_awaddr[28]
  PIN s_axi_awaddr[29]
    DIRECTION INPUT ;
    USE SIGNAL ;
    ANTENNAGATEAREA 0.126000 ;
    PORT
      LAYER met2 ;
        RECT 582.910 0.000 583.190 4.000 ;
    END
  END s_axi_awaddr[29]
  PIN s_axi_awaddr[2]
    DIRECTION INPUT ;
    USE SIGNAL ;
    ANTENNAGATEAREA 0.126000 ;
    PORT
      LAYER met3 ;
        RECT 0.000 248.240 4.000 248.840 ;
    END
  END s_axi_awaddr[2]
  PIN s_axi_awaddr[30]
    DIRECTION INPUT ;
    USE SIGNAL ;
    ANTENNAGATEAREA 0.126000 ;
    PORT
      LAYER met2 ;
        RECT 592.570 0.000 592.850 4.000 ;
    END
  END s_axi_awaddr[30]
  PIN s_axi_awaddr[31]
    DIRECTION INPUT ;
    USE SIGNAL ;
    ANTENNAGATEAREA 0.126000 ;
    PORT
      LAYER met2 ;
        RECT 553.930 0.000 554.210 4.000 ;
    END
  END s_axi_awaddr[31]
  PIN s_axi_awaddr[32]
    DIRECTION INPUT ;
    USE SIGNAL ;
    ANTENNAGATEAREA 0.126000 ;
    PORT
      LAYER met3 ;
        RECT 0.000 333.240 4.000 333.840 ;
    END
  END s_axi_awaddr[32]
  PIN s_axi_awaddr[33]
    DIRECTION INPUT ;
    USE SIGNAL ;
    ANTENNAGATEAREA 0.213000 ;
    PORT
      LAYER met2 ;
        RECT 164.310 0.000 164.590 4.000 ;
    END
  END s_axi_awaddr[33]
  PIN s_axi_awaddr[34]
    DIRECTION INPUT ;
    USE SIGNAL ;
    ANTENNAGATEAREA 0.126000 ;
    PORT
      LAYER met3 ;
        RECT 0.000 292.440 4.000 293.040 ;
    END
  END s_axi_awaddr[34]
  PIN s_axi_awaddr[35]
    DIRECTION INPUT ;
    USE SIGNAL ;
    ANTENNAGATEAREA 0.126000 ;
    PORT
      LAYER met3 ;
        RECT 0.000 384.240 4.000 384.840 ;
    END
  END s_axi_awaddr[35]
  PIN s_axi_awaddr[36]
    DIRECTION INPUT ;
    USE SIGNAL ;
    ANTENNAGATEAREA 0.126000 ;
    PORT
      LAYER met2 ;
        RECT 370.390 0.000 370.670 4.000 ;
    END
  END s_axi_awaddr[36]
  PIN s_axi_awaddr[37]
    DIRECTION INPUT ;
    USE SIGNAL ;
    ANTENNAGATEAREA 0.126000 ;
    PORT
      LAYER met3 ;
        RECT 0.000 231.240 4.000 231.840 ;
    END
  END s_axi_awaddr[37]
  PIN s_axi_awaddr[38]
    DIRECTION INPUT ;
    USE SIGNAL ;
    ANTENNAGATEAREA 0.126000 ;
    PORT
      LAYER met2 ;
        RECT 286.670 0.000 286.950 4.000 ;
    END
  END s_axi_awaddr[38]
  PIN s_axi_awaddr[39]
    DIRECTION INPUT ;
    USE SIGNAL ;
    ANTENNAGATEAREA 0.126000 ;
    PORT
      LAYER met2 ;
        RECT 302.770 0.000 303.050 4.000 ;
    END
  END s_axi_awaddr[39]
  PIN s_axi_awaddr[3]
    DIRECTION INPUT ;
    USE SIGNAL ;
    ANTENNAGATEAREA 0.126000 ;
    PORT
      LAYER met3 ;
        RECT 0.000 394.440 4.000 395.040 ;
    END
  END s_axi_awaddr[3]
  PIN s_axi_awaddr[40]
    DIRECTION INPUT ;
    USE SIGNAL ;
    ANTENNAGATEAREA 0.126000 ;
    PORT
      LAYER met2 ;
        RECT 363.950 0.000 364.230 4.000 ;
    END
  END s_axi_awaddr[40]
  PIN s_axi_awaddr[41]
    DIRECTION INPUT ;
    USE SIGNAL ;
    ANTENNAGATEAREA 0.126000 ;
    PORT
      LAYER met2 ;
        RECT 215.830 0.000 216.110 4.000 ;
    END
  END s_axi_awaddr[41]
  PIN s_axi_awaddr[42]
    DIRECTION INPUT ;
    USE SIGNAL ;
    ANTENNAGATEAREA 0.126000 ;
    PORT
      LAYER met2 ;
        RECT 283.450 0.000 283.730 4.000 ;
    END
  END s_axi_awaddr[42]
  PIN s_axi_awaddr[43]
    DIRECTION INPUT ;
    USE SIGNAL ;
    ANTENNAGATEAREA 0.126000 ;
    PORT
      LAYER met2 ;
        RECT 270.570 0.000 270.850 4.000 ;
    END
  END s_axi_awaddr[43]
  PIN s_axi_awaddr[44]
    DIRECTION INPUT ;
    USE SIGNAL ;
    ANTENNAGATEAREA 0.126000 ;
    PORT
      LAYER met2 ;
        RECT 273.790 0.000 274.070 4.000 ;
    END
  END s_axi_awaddr[44]
  PIN s_axi_awaddr[45]
    DIRECTION INPUT ;
    USE SIGNAL ;
    ANTENNAGATEAREA 0.126000 ;
    PORT
      LAYER met2 ;
        RECT 196.510 0.000 196.790 4.000 ;
    END
  END s_axi_awaddr[45]
  PIN s_axi_awaddr[46]
    DIRECTION INPUT ;
    USE SIGNAL ;
    ANTENNAGATEAREA 0.126000 ;
    PORT
      LAYER met2 ;
        RECT 315.650 0.000 315.930 4.000 ;
    END
  END s_axi_awaddr[46]
  PIN s_axi_awaddr[47]
    DIRECTION INPUT ;
    USE SIGNAL ;
    ANTENNAGATEAREA 0.126000 ;
    PORT
      LAYER met2 ;
        RECT 225.490 0.000 225.770 4.000 ;
    END
  END s_axi_awaddr[47]
  PIN s_axi_awaddr[48]
    DIRECTION INPUT ;
    USE SIGNAL ;
    ANTENNAGATEAREA 0.126000 ;
    PORT
      LAYER met2 ;
        RECT 209.390 0.000 209.670 4.000 ;
    END
  END s_axi_awaddr[48]
  PIN s_axi_awaddr[49]
    DIRECTION INPUT ;
    USE SIGNAL ;
    ANTENNAGATEAREA 0.126000 ;
    PORT
      LAYER met2 ;
        RECT 560.370 0.000 560.650 4.000 ;
    END
  END s_axi_awaddr[49]
  PIN s_axi_awaddr[4]
    DIRECTION INPUT ;
    USE SIGNAL ;
    ANTENNAGATEAREA 0.126000 ;
    PORT
      LAYER met2 ;
        RECT 135.330 0.000 135.610 4.000 ;
    END
  END s_axi_awaddr[4]
  PIN s_axi_awaddr[50]
    DIRECTION INPUT ;
    USE SIGNAL ;
    ANTENNAGATEAREA 0.126000 ;
    PORT
      LAYER met2 ;
        RECT 515.290 0.000 515.570 4.000 ;
    END
  END s_axi_awaddr[50]
  PIN s_axi_awaddr[51]
    DIRECTION INPUT ;
    USE SIGNAL ;
    ANTENNAGATEAREA 0.126000 ;
    PORT
      LAYER met2 ;
        RECT 328.530 0.000 328.810 4.000 ;
    END
  END s_axi_awaddr[51]
  PIN s_axi_awaddr[52]
    DIRECTION INPUT ;
    USE SIGNAL ;
    ANTENNAGATEAREA 0.126000 ;
    PORT
      LAYER met2 ;
        RECT 322.090 0.000 322.370 4.000 ;
    END
  END s_axi_awaddr[52]
  PIN s_axi_awaddr[53]
    DIRECTION INPUT ;
    USE SIGNAL ;
    ANTENNAGATEAREA 0.126000 ;
    PORT
      LAYER met2 ;
        RECT 441.230 0.000 441.510 4.000 ;
    END
  END s_axi_awaddr[53]
  PIN s_axi_awaddr[54]
    DIRECTION INPUT ;
    USE SIGNAL ;
    ANTENNAGATEAREA 0.126000 ;
    PORT
      LAYER met2 ;
        RECT 518.510 0.000 518.790 4.000 ;
    END
  END s_axi_awaddr[54]
  PIN s_axi_awaddr[55]
    DIRECTION INPUT ;
    USE SIGNAL ;
    ANTENNAGATEAREA 0.126000 ;
    PORT
      LAYER met2 ;
        RECT 344.630 0.000 344.910 4.000 ;
    END
  END s_axi_awaddr[55]
  PIN s_axi_awaddr[56]
    DIRECTION INPUT ;
    USE SIGNAL ;
    ANTENNAGATEAREA 0.126000 ;
    PORT
      LAYER met2 ;
        RECT 325.310 0.000 325.590 4.000 ;
    END
  END s_axi_awaddr[56]
  PIN s_axi_awaddr[57]
    DIRECTION INPUT ;
    USE SIGNAL ;
    ANTENNAGATEAREA 0.126000 ;
    PORT
      LAYER met2 ;
        RECT 637.650 0.000 637.930 4.000 ;
    END
  END s_axi_awaddr[57]
  PIN s_axi_awaddr[58]
    DIRECTION INPUT ;
    USE SIGNAL ;
    ANTENNAGATEAREA 0.126000 ;
    PORT
      LAYER met2 ;
        RECT 595.790 0.000 596.070 4.000 ;
    END
  END s_axi_awaddr[58]
  PIN s_axi_awaddr[59]
    DIRECTION INPUT ;
    USE SIGNAL ;
    ANTENNAGATEAREA 0.126000 ;
    PORT
      LAYER met2 ;
        RECT 434.790 0.000 435.070 4.000 ;
    END
  END s_axi_awaddr[59]
  PIN s_axi_awaddr[5]
    DIRECTION INPUT ;
    USE SIGNAL ;
    ANTENNAGATEAREA 0.126000 ;
    PORT
      LAYER met3 ;
        RECT 0.000 353.640 4.000 354.240 ;
    END
  END s_axi_awaddr[5]
  PIN s_axi_awaddr[60]
    DIRECTION INPUT ;
    USE SIGNAL ;
    ANTENNAGATEAREA 0.126000 ;
    PORT
      LAYER met2 ;
        RECT 627.990 0.000 628.270 4.000 ;
    END
  END s_axi_awaddr[60]
  PIN s_axi_awaddr[61]
    DIRECTION INPUT ;
    USE SIGNAL ;
    ANTENNAGATEAREA 0.126000 ;
    PORT
      LAYER met2 ;
        RECT 466.990 0.000 467.270 4.000 ;
    END
  END s_axi_awaddr[61]
  PIN s_axi_awaddr[62]
    DIRECTION INPUT ;
    USE SIGNAL ;
    ANTENNAGATEAREA 0.126000 ;
    PORT
      LAYER met2 ;
        RECT 473.430 0.000 473.710 4.000 ;
    END
  END s_axi_awaddr[62]
  PIN s_axi_awaddr[63]
    DIRECTION INPUT ;
    USE SIGNAL ;
    ANTENNAGATEAREA 0.126000 ;
    PORT
      LAYER met2 ;
        RECT 602.230 0.000 602.510 4.000 ;
    END
  END s_axi_awaddr[63]
  PIN s_axi_awaddr[64]
    DIRECTION INPUT ;
    USE SIGNAL ;
    ANTENNAGATEAREA 0.126000 ;
    PORT
      LAYER met3 ;
        RECT 0.000 391.040 4.000 391.640 ;
    END
  END s_axi_awaddr[64]
  PIN s_axi_awaddr[65]
    DIRECTION INPUT ;
    USE SIGNAL ;
    ANTENNAGATEAREA 0.126000 ;
    PORT
      LAYER met3 ;
        RECT 0.000 299.240 4.000 299.840 ;
    END
  END s_axi_awaddr[65]
  PIN s_axi_awaddr[66]
    DIRECTION INPUT ;
    USE SIGNAL ;
    ANTENNAGATEAREA 0.126000 ;
    PORT
      LAYER met3 ;
        RECT 0.000 319.640 4.000 320.240 ;
    END
  END s_axi_awaddr[66]
  PIN s_axi_awaddr[67]
    DIRECTION INPUT ;
    USE SIGNAL ;
    ANTENNAGATEAREA 0.126000 ;
    PORT
      LAYER met3 ;
        RECT 0.000 244.840 4.000 245.440 ;
    END
  END s_axi_awaddr[67]
  PIN s_axi_awaddr[68]
    DIRECTION INPUT ;
    USE SIGNAL ;
    ANTENNAGATEAREA 0.126000 ;
    PORT
      LAYER met3 ;
        RECT 0.000 401.240 4.000 401.840 ;
    END
  END s_axi_awaddr[68]
  PIN s_axi_awaddr[69]
    DIRECTION INPUT ;
    USE SIGNAL ;
    ANTENNAGATEAREA 0.126000 ;
    PORT
      LAYER met3 ;
        RECT 0.000 346.840 4.000 347.440 ;
    END
  END s_axi_awaddr[69]
  PIN s_axi_awaddr[6]
    DIRECTION INPUT ;
    USE SIGNAL ;
    ANTENNAGATEAREA 0.126000 ;
    PORT
      LAYER met2 ;
        RECT 293.110 0.000 293.390 4.000 ;
    END
  END s_axi_awaddr[6]
  PIN s_axi_awaddr[70]
    DIRECTION INPUT ;
    USE SIGNAL ;
    ANTENNAGATEAREA 0.126000 ;
    PORT
      LAYER met3 ;
        RECT 0.000 221.040 4.000 221.640 ;
    END
  END s_axi_awaddr[70]
  PIN s_axi_awaddr[71]
    DIRECTION INPUT ;
    USE SIGNAL ;
    ANTENNAGATEAREA 0.126000 ;
    PORT
      LAYER met2 ;
        RECT 296.330 0.000 296.610 4.000 ;
    END
  END s_axi_awaddr[71]
  PIN s_axi_awaddr[72]
    DIRECTION INPUT ;
    USE SIGNAL ;
    ANTENNAGATEAREA 0.126000 ;
    PORT
      LAYER met2 ;
        RECT 367.170 0.000 367.450 4.000 ;
    END
  END s_axi_awaddr[72]
  PIN s_axi_awaddr[73]
    DIRECTION INPUT ;
    USE SIGNAL ;
    ANTENNAGATEAREA 0.126000 ;
    PORT
      LAYER met2 ;
        RECT 170.750 0.000 171.030 4.000 ;
    END
  END s_axi_awaddr[73]
  PIN s_axi_awaddr[74]
    DIRECTION INPUT ;
    USE SIGNAL ;
    ANTENNAGATEAREA 0.126000 ;
    PORT
      LAYER met3 ;
        RECT 0.000 336.640 4.000 337.240 ;
    END
  END s_axi_awaddr[74]
  PIN s_axi_awaddr[75]
    DIRECTION INPUT ;
    USE SIGNAL ;
    ANTENNAGATEAREA 0.126000 ;
    PORT
      LAYER met3 ;
        RECT 0.000 306.040 4.000 306.640 ;
    END
  END s_axi_awaddr[75]
  PIN s_axi_awaddr[76]
    DIRECTION INPUT ;
    USE SIGNAL ;
    ANTENNAGATEAREA 0.126000 ;
    PORT
      LAYER met3 ;
        RECT 0.000 295.840 4.000 296.440 ;
    END
  END s_axi_awaddr[76]
  PIN s_axi_awaddr[77]
    DIRECTION INPUT ;
    USE SIGNAL ;
    ANTENNAGATEAREA 0.126000 ;
    PORT
      LAYER met2 ;
        RECT 154.650 0.000 154.930 4.000 ;
    END
  END s_axi_awaddr[77]
  PIN s_axi_awaddr[78]
    DIRECTION INPUT ;
    USE SIGNAL ;
    ANTENNAGATEAREA 0.126000 ;
    PORT
      LAYER met2 ;
        RECT 235.150 0.000 235.430 4.000 ;
    END
  END s_axi_awaddr[78]
  PIN s_axi_awaddr[79]
    DIRECTION INPUT ;
    USE SIGNAL ;
    ANTENNAGATEAREA 0.126000 ;
    PORT
      LAYER met2 ;
        RECT 222.270 0.000 222.550 4.000 ;
    END
  END s_axi_awaddr[79]
  PIN s_axi_awaddr[7]
    DIRECTION INPUT ;
    USE SIGNAL ;
    ANTENNAGATEAREA 0.126000 ;
    PORT
      LAYER met2 ;
        RECT 305.990 0.000 306.270 4.000 ;
    END
  END s_axi_awaddr[7]
  PIN s_axi_awaddr[80]
    DIRECTION INPUT ;
    USE SIGNAL ;
    ANTENNAGATEAREA 0.126000 ;
    PORT
      LAYER met2 ;
        RECT 360.730 0.000 361.010 4.000 ;
    END
  END s_axi_awaddr[80]
  PIN s_axi_awaddr[81]
    DIRECTION INPUT ;
    USE SIGNAL ;
    ANTENNAGATEAREA 0.126000 ;
    PORT
      LAYER met2 ;
        RECT 541.050 0.000 541.330 4.000 ;
    END
  END s_axi_awaddr[81]
  PIN s_axi_awaddr[82]
    DIRECTION INPUT ;
    USE SIGNAL ;
    ANTENNAGATEAREA 0.126000 ;
    PORT
      LAYER met2 ;
        RECT 479.870 0.000 480.150 4.000 ;
    END
  END s_axi_awaddr[82]
  PIN s_axi_awaddr[83]
    DIRECTION INPUT ;
    USE SIGNAL ;
    ANTENNAGATEAREA 0.126000 ;
    PORT
      LAYER met2 ;
        RECT 351.070 0.000 351.350 4.000 ;
    END
  END s_axi_awaddr[83]
  PIN s_axi_awaddr[84]
    DIRECTION INPUT ;
    USE SIGNAL ;
    ANTENNAGATEAREA 0.126000 ;
    PORT
      LAYER met2 ;
        RECT 341.410 0.000 341.690 4.000 ;
    END
  END s_axi_awaddr[84]
  PIN s_axi_awaddr[85]
    DIRECTION INPUT ;
    USE SIGNAL ;
    ANTENNAGATEAREA 0.126000 ;
    PORT
      LAYER met2 ;
        RECT 563.590 0.000 563.870 4.000 ;
    END
  END s_axi_awaddr[85]
  PIN s_axi_awaddr[86]
    DIRECTION INPUT ;
    USE SIGNAL ;
    ANTENNAGATEAREA 0.126000 ;
    PORT
      LAYER met2 ;
        RECT 634.430 0.000 634.710 4.000 ;
    END
  END s_axi_awaddr[86]
  PIN s_axi_awaddr[87]
    DIRECTION INPUT ;
    USE SIGNAL ;
    ANTENNAGATEAREA 0.126000 ;
    PORT
      LAYER met2 ;
        RECT 354.290 0.000 354.570 4.000 ;
    END
  END s_axi_awaddr[87]
  PIN s_axi_awaddr[88]
    DIRECTION INPUT ;
    USE SIGNAL ;
    ANTENNAGATEAREA 0.126000 ;
    PORT
      LAYER met2 ;
        RECT 148.210 0.000 148.490 4.000 ;
    END
  END s_axi_awaddr[88]
  PIN s_axi_awaddr[89]
    DIRECTION INPUT ;
    USE SIGNAL ;
    ANTENNAGATEAREA 0.126000 ;
    PORT
      LAYER met2 ;
        RECT 508.850 0.000 509.130 4.000 ;
    END
  END s_axi_awaddr[89]
  PIN s_axi_awaddr[8]
    DIRECTION INPUT ;
    USE SIGNAL ;
    ANTENNAGATEAREA 0.126000 ;
    PORT
      LAYER met2 ;
        RECT 87.030 0.000 87.310 4.000 ;
    END
  END s_axi_awaddr[8]
  PIN s_axi_awaddr[90]
    DIRECTION INPUT ;
    USE SIGNAL ;
    ANTENNAGATEAREA 0.126000 ;
    PORT
      LAYER met2 ;
        RECT 524.950 0.000 525.230 4.000 ;
    END
  END s_axi_awaddr[90]
  PIN s_axi_awaddr[91]
    DIRECTION INPUT ;
    USE SIGNAL ;
    ANTENNAGATEAREA 0.126000 ;
    PORT
      LAYER met2 ;
        RECT 608.670 0.000 608.950 4.000 ;
    END
  END s_axi_awaddr[91]
  PIN s_axi_awaddr[92]
    DIRECTION INPUT ;
    USE SIGNAL ;
    ANTENNAGATEAREA 0.126000 ;
    PORT
      LAYER met2 ;
        RECT 579.690 0.000 579.970 4.000 ;
    END
  END s_axi_awaddr[92]
  PIN s_axi_awaddr[93]
    DIRECTION INPUT ;
    USE SIGNAL ;
    ANTENNAGATEAREA 0.126000 ;
    PORT
      LAYER met2 ;
        RECT 495.970 0.000 496.250 4.000 ;
    END
  END s_axi_awaddr[93]
  PIN s_axi_awaddr[94]
    DIRECTION INPUT ;
    USE SIGNAL ;
    ANTENNAGATEAREA 0.126000 ;
    PORT
      LAYER met2 ;
        RECT 476.650 0.000 476.930 4.000 ;
    END
  END s_axi_awaddr[94]
  PIN s_axi_awaddr[95]
    DIRECTION INPUT ;
    USE SIGNAL ;
    ANTENNAGATEAREA 0.126000 ;
    PORT
      LAYER met2 ;
        RECT 615.110 0.000 615.390 4.000 ;
    END
  END s_axi_awaddr[95]
  PIN s_axi_awaddr[96]
    DIRECTION INPUT ;
    USE SIGNAL ;
    ANTENNAGATEAREA 0.126000 ;
    PORT
      LAYER met3 ;
        RECT 0.000 380.840 4.000 381.440 ;
    END
  END s_axi_awaddr[96]
  PIN s_axi_awaddr[97]
    DIRECTION INPUT ;
    USE SIGNAL ;
    ANTENNAGATEAREA 0.126000 ;
    PORT
      LAYER met3 ;
        RECT 0.000 326.440 4.000 327.040 ;
    END
  END s_axi_awaddr[97]
  PIN s_axi_awaddr[98]
    DIRECTION INPUT ;
    USE SIGNAL ;
    ANTENNAGATEAREA 0.126000 ;
    PORT
      LAYER met3 ;
        RECT 0.000 370.640 4.000 371.240 ;
    END
  END s_axi_awaddr[98]
  PIN s_axi_awaddr[99]
    DIRECTION INPUT ;
    USE SIGNAL ;
    ANTENNAGATEAREA 0.126000 ;
    PORT
      LAYER met3 ;
        RECT 0.000 363.840 4.000 364.440 ;
    END
  END s_axi_awaddr[99]
  PIN s_axi_awaddr[9]
    DIRECTION INPUT ;
    USE SIGNAL ;
    ANTENNAGATEAREA 0.126000 ;
    PORT
      LAYER met2 ;
        RECT 199.730 0.000 200.010 4.000 ;
    END
  END s_axi_awaddr[9]
  PIN s_axi_awprot[0]
    DIRECTION INPUT ;
    USE SIGNAL ;
    ANTENNAGATEAREA 0.126000 ;
    PORT
      LAYER met3 ;
        RECT 0.000 397.840 4.000 398.440 ;
    END
  END s_axi_awprot[0]
  PIN s_axi_awprot[10]
    DIRECTION INPUT ;
    USE SIGNAL ;
    ANTENNAGATEAREA 0.126000 ;
    PORT
      LAYER met3 ;
        RECT 0.000 482.840 4.000 483.440 ;
    END
  END s_axi_awprot[10]
  PIN s_axi_awprot[11]
    DIRECTION INPUT ;
    USE SIGNAL ;
    ANTENNAGATEAREA 0.126000 ;
    PORT
      LAYER met3 ;
        RECT 0.000 472.640 4.000 473.240 ;
    END
  END s_axi_awprot[11]
  PIN s_axi_awprot[1]
    DIRECTION INPUT ;
    USE SIGNAL ;
    ANTENNAGATEAREA 0.126000 ;
    PORT
      LAYER met3 ;
        RECT 0.000 255.040 4.000 255.640 ;
    END
  END s_axi_awprot[1]
  PIN s_axi_awprot[2]
    DIRECTION INPUT ;
    USE SIGNAL ;
    ANTENNAGATEAREA 0.126000 ;
    PORT
      LAYER met3 ;
        RECT 0.000 693.640 4.000 694.240 ;
    END
  END s_axi_awprot[2]
  PIN s_axi_awprot[3]
    DIRECTION INPUT ;
    USE SIGNAL ;
    ANTENNAGATEAREA 0.126000 ;
    PORT
      LAYER met3 ;
        RECT 0.000 863.640 4.000 864.240 ;
    END
  END s_axi_awprot[3]
  PIN s_axi_awprot[4]
    DIRECTION INPUT ;
    USE SIGNAL ;
    ANTENNAGATEAREA 0.126000 ;
    PORT
      LAYER met3 ;
        RECT 0.000 414.840 4.000 415.440 ;
    END
  END s_axi_awprot[4]
  PIN s_axi_awprot[5]
    DIRECTION INPUT ;
    USE SIGNAL ;
    ANTENNAGATEAREA 0.126000 ;
    PORT
      LAYER met3 ;
        RECT 0.000 782.040 4.000 782.640 ;
    END
  END s_axi_awprot[5]
  PIN s_axi_awprot[6]
    DIRECTION INPUT ;
    USE SIGNAL ;
    ANTENNAGATEAREA 0.126000 ;
    PORT
      LAYER met3 ;
        RECT 0.000 775.240 4.000 775.840 ;
    END
  END s_axi_awprot[6]
  PIN s_axi_awprot[7]
    DIRECTION INPUT ;
    USE SIGNAL ;
    ANTENNAGATEAREA 0.126000 ;
    PORT
      LAYER met3 ;
        RECT 0.000 479.440 4.000 480.040 ;
    END
  END s_axi_awprot[7]
  PIN s_axi_awprot[8]
    DIRECTION INPUT ;
    USE SIGNAL ;
    ANTENNAGATEAREA 0.126000 ;
    PORT
      LAYER met3 ;
        RECT 0.000 469.240 4.000 469.840 ;
    END
  END s_axi_awprot[8]
  PIN s_axi_awprot[9]
    DIRECTION INPUT ;
    USE SIGNAL ;
    ANTENNAGATEAREA 0.126000 ;
    PORT
      LAYER met3 ;
        RECT 0.000 496.440 4.000 497.040 ;
    END
  END s_axi_awprot[9]
  PIN s_axi_awready[0]
    DIRECTION OUTPUT ;
    USE SIGNAL ;
    ANTENNADIFFAREA 0.340600 ;
    PORT
      LAYER met3 ;
        RECT 0.000 418.240 4.000 418.840 ;
    END
  END s_axi_awready[0]
  PIN s_axi_awready[1]
    DIRECTION OUTPUT ;
    USE SIGNAL ;
    ANTENNADIFFAREA 0.340600 ;
    PORT
      LAYER met2 ;
        RECT 418.690 0.000 418.970 4.000 ;
    END
  END s_axi_awready[1]
  PIN s_axi_awready[2]
    DIRECTION OUTPUT ;
    USE SIGNAL ;
    ANTENNADIFFAREA 0.340600 ;
    PORT
      LAYER met3 ;
        RECT 0.000 710.640 4.000 711.240 ;
    END
  END s_axi_awready[2]
  PIN s_axi_awready[3]
    DIRECTION OUTPUT ;
    USE SIGNAL ;
    ANTENNADIFFAREA 0.340600 ;
    PORT
      LAYER met3 ;
        RECT 0.000 350.240 4.000 350.840 ;
    END
  END s_axi_awready[3]
  PIN s_axi_awvalid[0]
    DIRECTION INPUT ;
    USE SIGNAL ;
    ANTENNAGATEAREA 0.213000 ;
    PORT
      LAYER met3 ;
        RECT 0.000 289.040 4.000 289.640 ;
    END
  END s_axi_awvalid[0]
  PIN s_axi_awvalid[1]
    DIRECTION INPUT ;
    USE SIGNAL ;
    ANTENNAGATEAREA 0.213000 ;
    PORT
      LAYER met2 ;
        RECT 463.770 0.000 464.050 4.000 ;
    END
  END s_axi_awvalid[1]
  PIN s_axi_awvalid[2]
    DIRECTION INPUT ;
    USE SIGNAL ;
    ANTENNAGATEAREA 0.213000 ;
    PORT
      LAYER met3 ;
        RECT 0.000 751.440 4.000 752.040 ;
    END
  END s_axi_awvalid[2]
  PIN s_axi_awvalid[3]
    DIRECTION INPUT ;
    USE SIGNAL ;
    ANTENNAGATEAREA 0.213000 ;
    PORT
      LAYER met3 ;
        RECT 0.000 268.640 4.000 269.240 ;
    END
  END s_axi_awvalid[3]
  PIN s_axi_bready[0]
    DIRECTION INPUT ;
    USE SIGNAL ;
    ANTENNAGATEAREA 0.213000 ;
    PORT
      LAYER met3 ;
        RECT 0.000 649.440 4.000 650.040 ;
    END
  END s_axi_bready[0]
  PIN s_axi_bready[1]
    DIRECTION INPUT ;
    USE SIGNAL ;
    ANTENNAGATEAREA 0.213000 ;
    PORT
      LAYER met3 ;
        RECT 0.000 741.240 4.000 741.840 ;
    END
  END s_axi_bready[1]
  PIN s_axi_bready[2]
    DIRECTION INPUT ;
    USE SIGNAL ;
    ANTENNAGATEAREA 0.196500 ;
    PORT
      LAYER met3 ;
        RECT 0.000 462.440 4.000 463.040 ;
    END
  END s_axi_bready[2]
  PIN s_axi_bready[3]
    DIRECTION INPUT ;
    USE SIGNAL ;
    ANTENNAGATEAREA 0.196500 ;
    PORT
      LAYER met3 ;
        RECT 0.000 448.840 4.000 449.440 ;
    END
  END s_axi_bready[3]
  PIN s_axi_bresp[0]
    DIRECTION OUTPUT ;
    USE SIGNAL ;
    ANTENNADIFFAREA 0.340600 ;
    PORT
      LAYER met3 ;
        RECT 0.000 421.640 4.000 422.240 ;
    END
  END s_axi_bresp[0]
  PIN s_axi_bresp[1]
    DIRECTION OUTPUT ;
    USE SIGNAL ;
    ANTENNADIFFAREA 0.340600 ;
    PORT
      LAYER met3 ;
        RECT 0.000 261.840 4.000 262.440 ;
    END
  END s_axi_bresp[1]
  PIN s_axi_bresp[2]
    DIRECTION OUTPUT ;
    USE SIGNAL ;
    ANTENNADIFFAREA 0.340600 ;
    PORT
      LAYER met3 ;
        RECT 0.000 377.440 4.000 378.040 ;
    END
  END s_axi_bresp[2]
  PIN s_axi_bresp[3]
    DIRECTION OUTPUT ;
    USE SIGNAL ;
    ANTENNADIFFAREA 0.340600 ;
    PORT
      LAYER met3 ;
        RECT 0.000 272.040 4.000 272.640 ;
    END
  END s_axi_bresp[3]
  PIN s_axi_bresp[4]
    DIRECTION OUTPUT ;
    USE SIGNAL ;
    ANTENNADIFFAREA 0.340600 ;
    PORT
      LAYER met3 ;
        RECT 0.000 238.040 4.000 238.640 ;
    END
  END s_axi_bresp[4]
  PIN s_axi_bresp[5]
    DIRECTION OUTPUT ;
    USE SIGNAL ;
    ANTENNADIFFAREA 0.340600 ;
    PORT
      LAYER met3 ;
        RECT 0.000 435.240 4.000 435.840 ;
    END
  END s_axi_bresp[5]
  PIN s_axi_bresp[6]
    DIRECTION OUTPUT ;
    USE SIGNAL ;
    ANTENNADIFFAREA 0.340600 ;
    PORT
      LAYER met3 ;
        RECT 0.000 224.440 4.000 225.040 ;
    END
  END s_axi_bresp[6]
  PIN s_axi_bresp[7]
    DIRECTION OUTPUT ;
    USE SIGNAL ;
    ANTENNADIFFAREA 0.340600 ;
    PORT
      LAYER met3 ;
        RECT 0.000 452.240 4.000 452.840 ;
    END
  END s_axi_bresp[7]
  PIN s_axi_bvalid[0]
    DIRECTION OUTPUT ;
    USE SIGNAL ;
    ANTENNADIFFAREA 0.340600 ;
    PORT
      LAYER met3 ;
        RECT 0.000 465.840 4.000 466.440 ;
    END
  END s_axi_bvalid[0]
  PIN s_axi_bvalid[1]
    DIRECTION OUTPUT ;
    USE SIGNAL ;
    ANTENNADIFFAREA 0.340600 ;
    PORT
      LAYER met3 ;
        RECT 0.000 714.040 4.000 714.640 ;
    END
  END s_axi_bvalid[1]
  PIN s_axi_bvalid[2]
    DIRECTION OUTPUT ;
    USE SIGNAL ;
    ANTENNADIFFAREA 0.340600 ;
    PORT
      LAYER met3 ;
        RECT 0.000 870.440 4.000 871.040 ;
    END
  END s_axi_bvalid[2]
  PIN s_axi_bvalid[3]
    DIRECTION OUTPUT ;
    USE SIGNAL ;
    ANTENNADIFFAREA 0.340600 ;
    PORT
      LAYER met3 ;
        RECT 0.000 676.640 4.000 677.240 ;
    END
  END s_axi_bvalid[3]
  PIN s_axi_rdata[0]
    DIRECTION OUTPUT ;
    USE SIGNAL ;
    ANTENNADIFFAREA 0.340600 ;
    PORT
      LAYER met3 ;
        RECT 896.000 656.240 900.000 656.840 ;
    END
  END s_axi_rdata[0]
  PIN s_axi_rdata[100]
    DIRECTION OUTPUT ;
    USE SIGNAL ;
    ANTENNADIFFAREA 0.340600 ;
    PORT
      LAYER met3 ;
        RECT 896.000 550.840 900.000 551.440 ;
    END
  END s_axi_rdata[100]
  PIN s_axi_rdata[101]
    DIRECTION OUTPUT ;
    USE SIGNAL ;
    ANTENNADIFFAREA 0.340600 ;
    PORT
      LAYER met3 ;
        RECT 896.000 666.440 900.000 667.040 ;
    END
  END s_axi_rdata[101]
  PIN s_axi_rdata[102]
    DIRECTION OUTPUT ;
    USE SIGNAL ;
    ANTENNADIFFAREA 0.340600 ;
    PORT
      LAYER met3 ;
        RECT 896.000 527.040 900.000 527.640 ;
    END
  END s_axi_rdata[102]
  PIN s_axi_rdata[103]
    DIRECTION OUTPUT ;
    USE SIGNAL ;
    ANTENNADIFFAREA 0.340600 ;
    PORT
      LAYER met3 ;
        RECT 896.000 581.440 900.000 582.040 ;
    END
  END s_axi_rdata[103]
  PIN s_axi_rdata[104]
    DIRECTION OUTPUT ;
    USE SIGNAL ;
    ANTENNADIFFAREA 0.340600 ;
    PORT
      LAYER met3 ;
        RECT 896.000 544.040 900.000 544.640 ;
    END
  END s_axi_rdata[104]
  PIN s_axi_rdata[105]
    DIRECTION OUTPUT ;
    USE SIGNAL ;
    ANTENNADIFFAREA 0.340600 ;
    PORT
      LAYER met3 ;
        RECT 896.000 669.840 900.000 670.440 ;
    END
  END s_axi_rdata[105]
  PIN s_axi_rdata[106]
    DIRECTION OUTPUT ;
    USE SIGNAL ;
    ANTENNADIFFAREA 0.340600 ;
    PORT
      LAYER met3 ;
        RECT 0.000 812.640 4.000 813.240 ;
    END
  END s_axi_rdata[106]
  PIN s_axi_rdata[107]
    DIRECTION OUTPUT ;
    USE SIGNAL ;
    ANTENNADIFFAREA 0.340600 ;
    PORT
      LAYER met3 ;
        RECT 0.000 618.840 4.000 619.440 ;
    END
  END s_axi_rdata[107]
  PIN s_axi_rdata[108]
    DIRECTION OUTPUT ;
    USE SIGNAL ;
    ANTENNADIFFAREA 0.340600 ;
    PORT
      LAYER met3 ;
        RECT 0.000 887.440 4.000 888.040 ;
    END
  END s_axi_rdata[108]
  PIN s_axi_rdata[109]
    DIRECTION OUTPUT ;
    USE SIGNAL ;
    ANTENNADIFFAREA 0.340600 ;
    PORT
      LAYER met3 ;
        RECT 0.000 867.040 4.000 867.640 ;
    END
  END s_axi_rdata[109]
  PIN s_axi_rdata[10]
    DIRECTION OUTPUT ;
    USE SIGNAL ;
    ANTENNADIFFAREA 0.340600 ;
    PORT
      LAYER met3 ;
        RECT 0.000 795.640 4.000 796.240 ;
    END
  END s_axi_rdata[10]
  PIN s_axi_rdata[110]
    DIRECTION OUTPUT ;
    USE SIGNAL ;
    ANTENNADIFFAREA 0.340600 ;
    PORT
      LAYER met3 ;
        RECT 896.000 530.440 900.000 531.040 ;
    END
  END s_axi_rdata[110]
  PIN s_axi_rdata[111]
    DIRECTION OUTPUT ;
    USE SIGNAL ;
    ANTENNADIFFAREA 0.340600 ;
    PORT
      LAYER met3 ;
        RECT 0.000 843.240 4.000 843.840 ;
    END
  END s_axi_rdata[111]
  PIN s_axi_rdata[112]
    DIRECTION OUTPUT ;
    USE SIGNAL ;
    ANTENNADIFFAREA 0.340600 ;
    PORT
      LAYER met3 ;
        RECT 0.000 734.440 4.000 735.040 ;
    END
  END s_axi_rdata[112]
  PIN s_axi_rdata[113]
    DIRECTION OUTPUT ;
    USE SIGNAL ;
    ANTENNADIFFAREA 0.340600 ;
    PORT
      LAYER met3 ;
        RECT 0.000 853.440 4.000 854.040 ;
    END
  END s_axi_rdata[113]
  PIN s_axi_rdata[114]
    DIRECTION OUTPUT ;
    USE SIGNAL ;
    ANTENNADIFFAREA 0.340600 ;
    PORT
      LAYER met3 ;
        RECT 0.000 809.240 4.000 809.840 ;
    END
  END s_axi_rdata[114]
  PIN s_axi_rdata[115]
    DIRECTION OUTPUT ;
    USE SIGNAL ;
    ANTENNADIFFAREA 0.340600 ;
    PORT
      LAYER met3 ;
        RECT 0.000 642.640 4.000 643.240 ;
    END
  END s_axi_rdata[115]
  PIN s_axi_rdata[116]
    DIRECTION OUTPUT ;
    USE SIGNAL ;
    ANTENNADIFFAREA 0.340600 ;
    PORT
      LAYER met3 ;
        RECT 896.000 30.640 900.000 31.240 ;
    END
  END s_axi_rdata[116]
  PIN s_axi_rdata[117]
    DIRECTION OUTPUT ;
    USE SIGNAL ;
    ANTENNADIFFAREA 0.340600 ;
    PORT
      LAYER met3 ;
        RECT 896.000 34.040 900.000 34.640 ;
    END
  END s_axi_rdata[117]
  PIN s_axi_rdata[118]
    DIRECTION OUTPUT ;
    USE SIGNAL ;
    ANTENNADIFFAREA 0.340600 ;
    PORT
      LAYER met3 ;
        RECT 896.000 10.240 900.000 10.840 ;
    END
  END s_axi_rdata[118]
  PIN s_axi_rdata[119]
    DIRECTION OUTPUT ;
    USE SIGNAL ;
    ANTENNADIFFAREA 0.340600 ;
    PORT
      LAYER met3 ;
        RECT 896.000 105.440 900.000 106.040 ;
    END
  END s_axi_rdata[119]
  PIN s_axi_rdata[11]
    DIRECTION OUTPUT ;
    USE SIGNAL ;
    ANTENNADIFFAREA 0.340600 ;
    PORT
      LAYER met3 ;
        RECT 0.000 768.440 4.000 769.040 ;
    END
  END s_axi_rdata[11]
  PIN s_axi_rdata[120]
    DIRECTION OUTPUT ;
    USE SIGNAL ;
    ANTENNADIFFAREA 0.340600 ;
    PORT
      LAYER met3 ;
        RECT 896.000 510.040 900.000 510.640 ;
    END
  END s_axi_rdata[120]
  PIN s_axi_rdata[121]
    DIRECTION OUTPUT ;
    USE SIGNAL ;
    ANTENNADIFFAREA 0.340600 ;
    PORT
      LAYER met3 ;
        RECT 896.000 13.640 900.000 14.240 ;
    END
  END s_axi_rdata[121]
  PIN s_axi_rdata[122]
    DIRECTION OUTPUT ;
    USE SIGNAL ;
    ANTENNADIFFAREA 0.340600 ;
    PORT
      LAYER met3 ;
        RECT 896.000 282.240 900.000 282.840 ;
    END
  END s_axi_rdata[122]
  PIN s_axi_rdata[123]
    DIRECTION OUTPUT ;
    USE SIGNAL ;
    ANTENNADIFFAREA 0.340600 ;
    PORT
      LAYER met3 ;
        RECT 896.000 411.440 900.000 412.040 ;
    END
  END s_axi_rdata[123]
  PIN s_axi_rdata[124]
    DIRECTION OUTPUT ;
    USE SIGNAL ;
    ANTENNADIFFAREA 0.340600 ;
    PORT
      LAYER met3 ;
        RECT 896.000 71.440 900.000 72.040 ;
    END
  END s_axi_rdata[124]
  PIN s_axi_rdata[125]
    DIRECTION OUTPUT ;
    USE SIGNAL ;
    ANTENNADIFFAREA 0.340600 ;
    PORT
      LAYER met3 ;
        RECT 896.000 377.440 900.000 378.040 ;
    END
  END s_axi_rdata[125]
  PIN s_axi_rdata[126]
    DIRECTION OUTPUT ;
    USE SIGNAL ;
    ANTENNADIFFAREA 0.340600 ;
    PORT
      LAYER met3 ;
        RECT 896.000 574.640 900.000 575.240 ;
    END
  END s_axi_rdata[126]
  PIN s_axi_rdata[127]
    DIRECTION OUTPUT ;
    USE SIGNAL ;
    ANTENNADIFFAREA 0.340600 ;
    PORT
      LAYER met3 ;
        RECT 896.000 537.240 900.000 537.840 ;
    END
  END s_axi_rdata[127]
  PIN s_axi_rdata[12]
    DIRECTION OUTPUT ;
    USE SIGNAL ;
    ANTENNADIFFAREA 0.340600 ;
    PORT
      LAYER met3 ;
        RECT 0.000 894.240 4.000 894.840 ;
    END
  END s_axi_rdata[12]
  PIN s_axi_rdata[13]
    DIRECTION OUTPUT ;
    USE SIGNAL ;
    ANTENNADIFFAREA 0.340600 ;
    PORT
      LAYER met3 ;
        RECT 0.000 703.840 4.000 704.440 ;
    END
  END s_axi_rdata[13]
  PIN s_axi_rdata[14]
    DIRECTION OUTPUT ;
    USE SIGNAL ;
    ANTENNADIFFAREA 0.340600 ;
    PORT
      LAYER met3 ;
        RECT 896.000 540.640 900.000 541.240 ;
    END
  END s_axi_rdata[14]
  PIN s_axi_rdata[15]
    DIRECTION OUTPUT ;
    USE SIGNAL ;
    ANTENNADIFFAREA 0.340600 ;
    PORT
      LAYER met3 ;
        RECT 0.000 758.240 4.000 758.840 ;
    END
  END s_axi_rdata[15]
  PIN s_axi_rdata[16]
    DIRECTION OUTPUT ;
    USE SIGNAL ;
    ANTENNADIFFAREA 0.340600 ;
    PORT
      LAYER met3 ;
        RECT 0.000 805.840 4.000 806.440 ;
    END
  END s_axi_rdata[16]
  PIN s_axi_rdata[17]
    DIRECTION OUTPUT ;
    USE SIGNAL ;
    ANTENNADIFFAREA 0.340600 ;
    PORT
      LAYER met3 ;
        RECT 0.000 877.240 4.000 877.840 ;
    END
  END s_axi_rdata[17]
  PIN s_axi_rdata[18]
    DIRECTION OUTPUT ;
    USE SIGNAL ;
    ANTENNADIFFAREA 0.340600 ;
    PORT
      LAYER met3 ;
        RECT 0.000 856.840 4.000 857.440 ;
    END
  END s_axi_rdata[18]
  PIN s_axi_rdata[19]
    DIRECTION OUTPUT ;
    USE SIGNAL ;
    ANTENNADIFFAREA 0.340600 ;
    PORT
      LAYER met3 ;
        RECT 0.000 836.440 4.000 837.040 ;
    END
  END s_axi_rdata[19]
  PIN s_axi_rdata[1]
    DIRECTION OUTPUT ;
    USE SIGNAL ;
    ANTENNADIFFAREA 0.340600 ;
    PORT
      LAYER met3 ;
        RECT 896.000 554.240 900.000 554.840 ;
    END
  END s_axi_rdata[1]
  PIN s_axi_rdata[20]
    DIRECTION OUTPUT ;
    USE SIGNAL ;
    ANTENNADIFFAREA 0.340600 ;
    PORT
      LAYER met3 ;
        RECT 896.000 51.040 900.000 51.640 ;
    END
  END s_axi_rdata[20]
  PIN s_axi_rdata[21]
    DIRECTION OUTPUT ;
    USE SIGNAL ;
    ANTENNADIFFAREA 0.340600 ;
    PORT
      LAYER met3 ;
        RECT 896.000 17.040 900.000 17.640 ;
    END
  END s_axi_rdata[21]
  PIN s_axi_rdata[22]
    DIRECTION OUTPUT ;
    USE SIGNAL ;
    ANTENNADIFFAREA 0.340600 ;
    PORT
      LAYER met3 ;
        RECT 896.000 3.440 900.000 4.040 ;
    END
  END s_axi_rdata[22]
  PIN s_axi_rdata[23]
    DIRECTION OUTPUT ;
    USE SIGNAL ;
    ANTENNADIFFAREA 0.340600 ;
    PORT
      LAYER met3 ;
        RECT 896.000 343.440 900.000 344.040 ;
    END
  END s_axi_rdata[23]
  PIN s_axi_rdata[24]
    DIRECTION OUTPUT ;
    USE SIGNAL ;
    ANTENNADIFFAREA 0.340600 ;
    PORT
      LAYER met3 ;
        RECT 896.000 78.240 900.000 78.840 ;
    END
  END s_axi_rdata[24]
  PIN s_axi_rdata[25]
    DIRECTION OUTPUT ;
    USE SIGNAL ;
    ANTENNADIFFAREA 0.340600 ;
    PORT
      LAYER met3 ;
        RECT 896.000 98.640 900.000 99.240 ;
    END
  END s_axi_rdata[25]
  PIN s_axi_rdata[26]
    DIRECTION OUTPUT ;
    USE SIGNAL ;
    ANTENNADIFFAREA 0.340600 ;
    PORT
      LAYER met3 ;
        RECT 896.000 312.840 900.000 313.440 ;
    END
  END s_axi_rdata[26]
  PIN s_axi_rdata[27]
    DIRECTION OUTPUT ;
    USE SIGNAL ;
    ANTENNADIFFAREA 0.340600 ;
    PORT
      LAYER met3 ;
        RECT 896.000 380.840 900.000 381.440 ;
    END
  END s_axi_rdata[27]
  PIN s_axi_rdata[28]
    DIRECTION OUTPUT ;
    USE SIGNAL ;
    ANTENNADIFFAREA 0.340600 ;
    PORT
      LAYER met3 ;
        RECT 896.000 20.440 900.000 21.040 ;
    END
  END s_axi_rdata[28]
  PIN s_axi_rdata[29]
    DIRECTION OUTPUT ;
    USE SIGNAL ;
    ANTENNADIFFAREA 0.340600 ;
    PORT
      LAYER met3 ;
        RECT 896.000 285.640 900.000 286.240 ;
    END
  END s_axi_rdata[29]
  PIN s_axi_rdata[2]
    DIRECTION OUTPUT ;
    USE SIGNAL ;
    ANTENNADIFFAREA 0.340600 ;
    PORT
      LAYER met3 ;
        RECT 896.000 588.240 900.000 588.840 ;
    END
  END s_axi_rdata[2]
  PIN s_axi_rdata[30]
    DIRECTION OUTPUT ;
    USE SIGNAL ;
    ANTENNADIFFAREA 0.340600 ;
    PORT
      LAYER met3 ;
        RECT 896.000 516.840 900.000 517.440 ;
    END
  END s_axi_rdata[30]
  PIN s_axi_rdata[31]
    DIRECTION OUTPUT ;
    USE SIGNAL ;
    ANTENNADIFFAREA 0.340600 ;
    PORT
      LAYER met3 ;
        RECT 896.000 561.040 900.000 561.640 ;
    END
  END s_axi_rdata[31]
  PIN s_axi_rdata[32]
    DIRECTION OUTPUT ;
    USE SIGNAL ;
    ANTENNADIFFAREA 0.340600 ;
    PORT
      LAYER met3 ;
        RECT 896.000 646.040 900.000 646.640 ;
    END
  END s_axi_rdata[32]
  PIN s_axi_rdata[33]
    DIRECTION OUTPUT ;
    USE SIGNAL ;
    ANTENNADIFFAREA 0.340600 ;
    PORT
      LAYER met3 ;
        RECT 896.000 622.240 900.000 622.840 ;
    END
  END s_axi_rdata[33]
  PIN s_axi_rdata[34]
    DIRECTION OUTPUT ;
    USE SIGNAL ;
    ANTENNADIFFAREA 0.340600 ;
    PORT
      LAYER met3 ;
        RECT 896.000 618.840 900.000 619.440 ;
    END
  END s_axi_rdata[34]
  PIN s_axi_rdata[35]
    DIRECTION OUTPUT ;
    USE SIGNAL ;
    ANTENNADIFFAREA 0.340600 ;
    PORT
      LAYER met3 ;
        RECT 896.000 632.440 900.000 633.040 ;
    END
  END s_axi_rdata[35]
  PIN s_axi_rdata[36]
    DIRECTION OUTPUT ;
    USE SIGNAL ;
    ANTENNADIFFAREA 0.340600 ;
    PORT
      LAYER met3 ;
        RECT 896.000 564.440 900.000 565.040 ;
    END
  END s_axi_rdata[36]
  PIN s_axi_rdata[37]
    DIRECTION OUTPUT ;
    USE SIGNAL ;
    ANTENNADIFFAREA 0.340600 ;
    PORT
      LAYER met3 ;
        RECT 896.000 533.840 900.000 534.440 ;
    END
  END s_axi_rdata[37]
  PIN s_axi_rdata[38]
    DIRECTION OUTPUT ;
    USE SIGNAL ;
    ANTENNADIFFAREA 0.340600 ;
    PORT
      LAYER met3 ;
        RECT 896.000 605.240 900.000 605.840 ;
    END
  END s_axi_rdata[38]
  PIN s_axi_rdata[39]
    DIRECTION OUTPUT ;
    USE SIGNAL ;
    ANTENNADIFFAREA 0.340600 ;
    PORT
      LAYER met3 ;
        RECT 896.000 584.840 900.000 585.440 ;
    END
  END s_axi_rdata[39]
  PIN s_axi_rdata[3]
    DIRECTION OUTPUT ;
    USE SIGNAL ;
    ANTENNADIFFAREA 0.340600 ;
    PORT
      LAYER met3 ;
        RECT 896.000 673.240 900.000 673.840 ;
    END
  END s_axi_rdata[3]
  PIN s_axi_rdata[40]
    DIRECTION OUTPUT ;
    USE SIGNAL ;
    ANTENNADIFFAREA 0.340600 ;
    PORT
      LAYER met3 ;
        RECT 896.000 547.440 900.000 548.040 ;
    END
  END s_axi_rdata[40]
  PIN s_axi_rdata[41]
    DIRECTION OUTPUT ;
    USE SIGNAL ;
    ANTENNADIFFAREA 0.340600 ;
    PORT
      LAYER met3 ;
        RECT 896.000 598.440 900.000 599.040 ;
    END
  END s_axi_rdata[41]
  PIN s_axi_rdata[42]
    DIRECTION OUTPUT ;
    USE SIGNAL ;
    ANTENNADIFFAREA 0.340600 ;
    PORT
      LAYER met3 ;
        RECT 0.000 799.040 4.000 799.640 ;
    END
  END s_axi_rdata[42]
  PIN s_axi_rdata[43]
    DIRECTION OUTPUT ;
    USE SIGNAL ;
    ANTENNADIFFAREA 0.340600 ;
    PORT
      LAYER met3 ;
        RECT 0.000 605.240 4.000 605.840 ;
    END
  END s_axi_rdata[43]
  PIN s_axi_rdata[44]
    DIRECTION OUTPUT ;
    USE SIGNAL ;
    ANTENNADIFFAREA 0.340600 ;
    PORT
      LAYER met3 ;
        RECT 0.000 884.040 4.000 884.640 ;
    END
  END s_axi_rdata[44]
  PIN s_axi_rdata[45]
    DIRECTION OUTPUT ;
    USE SIGNAL ;
    ANTENNADIFFAREA 0.340600 ;
    PORT
      LAYER met3 ;
        RECT 0.000 846.640 4.000 847.240 ;
    END
  END s_axi_rdata[45]
  PIN s_axi_rdata[46]
    DIRECTION OUTPUT ;
    USE SIGNAL ;
    ANTENNADIFFAREA 0.340600 ;
    PORT
      LAYER met3 ;
        RECT 896.000 557.640 900.000 558.240 ;
    END
  END s_axi_rdata[46]
  PIN s_axi_rdata[47]
    DIRECTION OUTPUT ;
    USE SIGNAL ;
    ANTENNADIFFAREA 0.340600 ;
    PORT
      LAYER met3 ;
        RECT 0.000 635.840 4.000 636.440 ;
    END
  END s_axi_rdata[47]
  PIN s_axi_rdata[48]
    DIRECTION OUTPUT ;
    USE SIGNAL ;
    ANTENNADIFFAREA 0.340600 ;
    PORT
      LAYER met3 ;
        RECT 0.000 765.040 4.000 765.640 ;
    END
  END s_axi_rdata[48]
  PIN s_axi_rdata[49]
    DIRECTION OUTPUT ;
    USE SIGNAL ;
    ANTENNADIFFAREA 0.340600 ;
    PORT
      LAYER met3 ;
        RECT 0.000 839.840 4.000 840.440 ;
    END
  END s_axi_rdata[49]
  PIN s_axi_rdata[4]
    DIRECTION OUTPUT ;
    USE SIGNAL ;
    ANTENNADIFFAREA 0.340600 ;
    PORT
      LAYER met3 ;
        RECT 896.000 676.640 900.000 677.240 ;
    END
  END s_axi_rdata[4]
  PIN s_axi_rdata[50]
    DIRECTION OUTPUT ;
    USE SIGNAL ;
    ANTENNADIFFAREA 0.340600 ;
    PORT
      LAYER met3 ;
        RECT 0.000 656.240 4.000 656.840 ;
    END
  END s_axi_rdata[50]
  PIN s_axi_rdata[51]
    DIRECTION OUTPUT ;
    USE SIGNAL ;
    ANTENNADIFFAREA 0.340600 ;
    PORT
      LAYER met3 ;
        RECT 0.000 622.240 4.000 622.840 ;
    END
  END s_axi_rdata[51]
  PIN s_axi_rdata[52]
    DIRECTION OUTPUT ;
    USE SIGNAL ;
    ANTENNADIFFAREA 0.340600 ;
    PORT
      LAYER met3 ;
        RECT 896.000 176.840 900.000 177.440 ;
    END
  END s_axi_rdata[52]
  PIN s_axi_rdata[53]
    DIRECTION OUTPUT ;
    USE SIGNAL ;
    ANTENNADIFFAREA 0.340600 ;
    PORT
      LAYER met3 ;
        RECT 896.000 408.040 900.000 408.640 ;
    END
  END s_axi_rdata[53]
  PIN s_axi_rdata[54]
    DIRECTION OUTPUT ;
    USE SIGNAL ;
    ANTENNADIFFAREA 0.340600 ;
    PORT
      LAYER met3 ;
        RECT 896.000 0.040 900.000 0.640 ;
    END
  END s_axi_rdata[54]
  PIN s_axi_rdata[55]
    DIRECTION OUTPUT ;
    USE SIGNAL ;
    ANTENNADIFFAREA 0.340600 ;
    PORT
      LAYER met3 ;
        RECT 896.000 64.640 900.000 65.240 ;
    END
  END s_axi_rdata[55]
  PIN s_axi_rdata[56]
    DIRECTION OUTPUT ;
    USE SIGNAL ;
    ANTENNADIFFAREA 0.340600 ;
    PORT
      LAYER met3 ;
        RECT 896.000 306.040 900.000 306.640 ;
    END
  END s_axi_rdata[56]
  PIN s_axi_rdata[57]
    DIRECTION OUTPUT ;
    USE SIGNAL ;
    ANTENNADIFFAREA 0.340600 ;
    PORT
      LAYER met3 ;
        RECT 896.000 40.840 900.000 41.440 ;
    END
  END s_axi_rdata[57]
  PIN s_axi_rdata[58]
    DIRECTION OUTPUT ;
    USE SIGNAL ;
    ANTENNADIFFAREA 0.340600 ;
    PORT
      LAYER met3 ;
        RECT 896.000 139.440 900.000 140.040 ;
    END
  END s_axi_rdata[58]
  PIN s_axi_rdata[59]
    DIRECTION OUTPUT ;
    USE SIGNAL ;
    ANTENNADIFFAREA 0.340600 ;
    PORT
      LAYER met3 ;
        RECT 896.000 421.640 900.000 422.240 ;
    END
  END s_axi_rdata[59]
  PIN s_axi_rdata[5]
    DIRECTION OUTPUT ;
    USE SIGNAL ;
    ANTENNADIFFAREA 0.340600 ;
    PORT
      LAYER met3 ;
        RECT 896.000 659.640 900.000 660.240 ;
    END
  END s_axi_rdata[5]
  PIN s_axi_rdata[60]
    DIRECTION OUTPUT ;
    USE SIGNAL ;
    ANTENNADIFFAREA 0.340600 ;
    PORT
      LAYER met3 ;
        RECT 896.000 57.840 900.000 58.440 ;
    END
  END s_axi_rdata[60]
  PIN s_axi_rdata[61]
    DIRECTION OUTPUT ;
    USE SIGNAL ;
    ANTENNADIFFAREA 0.340600 ;
    PORT
      LAYER met3 ;
        RECT 896.000 108.840 900.000 109.440 ;
    END
  END s_axi_rdata[61]
  PIN s_axi_rdata[62]
    DIRECTION OUTPUT ;
    USE SIGNAL ;
    ANTENNADIFFAREA 0.340600 ;
    PORT
      LAYER met3 ;
        RECT 896.000 520.240 900.000 520.840 ;
    END
  END s_axi_rdata[62]
  PIN s_axi_rdata[63]
    DIRECTION OUTPUT ;
    USE SIGNAL ;
    ANTENNADIFFAREA 0.340600 ;
    PORT
      LAYER met3 ;
        RECT 896.000 523.640 900.000 524.240 ;
    END
  END s_axi_rdata[63]
  PIN s_axi_rdata[64]
    DIRECTION OUTPUT ;
    USE SIGNAL ;
    ANTENNADIFFAREA 0.340600 ;
    PORT
      LAYER met3 ;
        RECT 896.000 571.240 900.000 571.840 ;
    END
  END s_axi_rdata[64]
  PIN s_axi_rdata[65]
    DIRECTION OUTPUT ;
    USE SIGNAL ;
    ANTENNADIFFAREA 0.340600 ;
    PORT
      LAYER met3 ;
        RECT 896.000 578.040 900.000 578.640 ;
    END
  END s_axi_rdata[65]
  PIN s_axi_rdata[66]
    DIRECTION OUTPUT ;
    USE SIGNAL ;
    ANTENNADIFFAREA 0.340600 ;
    PORT
      LAYER met3 ;
        RECT 896.000 652.840 900.000 653.440 ;
    END
  END s_axi_rdata[66]
  PIN s_axi_rdata[67]
    DIRECTION OUTPUT ;
    USE SIGNAL ;
    ANTENNADIFFAREA 0.340600 ;
    PORT
      LAYER met3 ;
        RECT 896.000 635.840 900.000 636.440 ;
    END
  END s_axi_rdata[67]
  PIN s_axi_rdata[68]
    DIRECTION OUTPUT ;
    USE SIGNAL ;
    ANTENNADIFFAREA 0.340600 ;
    PORT
      LAYER met3 ;
        RECT 896.000 567.840 900.000 568.440 ;
    END
  END s_axi_rdata[68]
  PIN s_axi_rdata[69]
    DIRECTION OUTPUT ;
    USE SIGNAL ;
    ANTENNADIFFAREA 0.340600 ;
    PORT
      LAYER met3 ;
        RECT 0.000 873.840 4.000 874.440 ;
    END
  END s_axi_rdata[69]
  PIN s_axi_rdata[6]
    DIRECTION OUTPUT ;
    USE SIGNAL ;
    ANTENNADIFFAREA 0.340600 ;
    PORT
      LAYER met3 ;
        RECT 0.000 816.040 4.000 816.640 ;
    END
  END s_axi_rdata[6]
  PIN s_axi_rdata[70]
    DIRECTION OUTPUT ;
    USE SIGNAL ;
    ANTENNADIFFAREA 0.340600 ;
    PORT
      LAYER met3 ;
        RECT 0.000 880.640 4.000 881.240 ;
    END
  END s_axi_rdata[70]
  PIN s_axi_rdata[71]
    DIRECTION OUTPUT ;
    USE SIGNAL ;
    ANTENNADIFFAREA 0.340600 ;
    PORT
      LAYER met3 ;
        RECT 0.000 897.640 4.000 898.240 ;
    END
  END s_axi_rdata[71]
  PIN s_axi_rdata[72]
    DIRECTION OUTPUT ;
    USE SIGNAL ;
    ANTENNADIFFAREA 0.340600 ;
    PORT
      LAYER met3 ;
        RECT 0.000 890.840 4.000 891.440 ;
    END
  END s_axi_rdata[72]
  PIN s_axi_rdata[73]
    DIRECTION OUTPUT ;
    USE SIGNAL ;
    ANTENNADIFFAREA 0.340600 ;
    PORT
      LAYER met3 ;
        RECT 0.000 860.240 4.000 860.840 ;
    END
  END s_axi_rdata[73]
  PIN s_axi_rdata[74]
    DIRECTION OUTPUT ;
    USE SIGNAL ;
    ANTENNADIFFAREA 0.340600 ;
    PORT
      LAYER met3 ;
        RECT 0.000 683.440 4.000 684.040 ;
    END
  END s_axi_rdata[74]
  PIN s_axi_rdata[75]
    DIRECTION OUTPUT ;
    USE SIGNAL ;
    ANTENNADIFFAREA 0.340600 ;
    PORT
      LAYER met3 ;
        RECT 0.000 819.440 4.000 820.040 ;
    END
  END s_axi_rdata[75]
  PIN s_axi_rdata[76]
    DIRECTION OUTPUT ;
    USE SIGNAL ;
    ANTENNADIFFAREA 0.340600 ;
    PORT
      LAYER met3 ;
        RECT 0.000 822.840 4.000 823.440 ;
    END
  END s_axi_rdata[76]
  PIN s_axi_rdata[77]
    DIRECTION OUTPUT ;
    USE SIGNAL ;
    ANTENNADIFFAREA 0.340600 ;
    PORT
      LAYER met3 ;
        RECT 0.000 829.640 4.000 830.240 ;
    END
  END s_axi_rdata[77]
  PIN s_axi_rdata[78]
    DIRECTION OUTPUT ;
    USE SIGNAL ;
    ANTENNADIFFAREA 0.340600 ;
    PORT
      LAYER met3 ;
        RECT 896.000 836.440 900.000 837.040 ;
    END
  END s_axi_rdata[78]
  PIN s_axi_rdata[79]
    DIRECTION OUTPUT ;
    USE SIGNAL ;
    ANTENNADIFFAREA 0.340600 ;
    PORT
      LAYER met3 ;
        RECT 896.000 758.240 900.000 758.840 ;
    END
  END s_axi_rdata[79]
  PIN s_axi_rdata[7]
    DIRECTION OUTPUT ;
    USE SIGNAL ;
    ANTENNADIFFAREA 0.340600 ;
    PORT
      LAYER met3 ;
        RECT 896.000 805.840 900.000 806.440 ;
    END
  END s_axi_rdata[7]
  PIN s_axi_rdata[80]
    DIRECTION OUTPUT ;
    USE SIGNAL ;
    ANTENNADIFFAREA 0.340600 ;
    PORT
      LAYER met3 ;
        RECT 896.000 717.440 900.000 718.040 ;
    END
  END s_axi_rdata[80]
  PIN s_axi_rdata[81]
    DIRECTION OUTPUT ;
    USE SIGNAL ;
    ANTENNADIFFAREA 0.340600 ;
    PORT
      LAYER met3 ;
        RECT 896.000 761.640 900.000 762.240 ;
    END
  END s_axi_rdata[81]
  PIN s_axi_rdata[82]
    DIRECTION OUTPUT ;
    USE SIGNAL ;
    ANTENNADIFFAREA 0.340600 ;
    PORT
      LAYER met3 ;
        RECT 896.000 809.240 900.000 809.840 ;
    END
  END s_axi_rdata[82]
  PIN s_axi_rdata[83]
    DIRECTION OUTPUT ;
    USE SIGNAL ;
    ANTENNADIFFAREA 0.340600 ;
    PORT
      LAYER met3 ;
        RECT 896.000 812.640 900.000 813.240 ;
    END
  END s_axi_rdata[83]
  PIN s_axi_rdata[84]
    DIRECTION OUTPUT ;
    USE SIGNAL ;
    ANTENNADIFFAREA 0.340600 ;
    PORT
      LAYER met3 ;
        RECT 896.000 765.040 900.000 765.640 ;
    END
  END s_axi_rdata[84]
  PIN s_axi_rdata[85]
    DIRECTION OUTPUT ;
    USE SIGNAL ;
    ANTENNADIFFAREA 0.340600 ;
    PORT
      LAYER met3 ;
        RECT 896.000 690.240 900.000 690.840 ;
    END
  END s_axi_rdata[85]
  PIN s_axi_rdata[86]
    DIRECTION OUTPUT ;
    USE SIGNAL ;
    ANTENNADIFFAREA 0.340600 ;
    PORT
      LAYER met3 ;
        RECT 896.000 731.040 900.000 731.640 ;
    END
  END s_axi_rdata[86]
  PIN s_axi_rdata[87]
    DIRECTION OUTPUT ;
    USE SIGNAL ;
    ANTENNADIFFAREA 0.340600 ;
    PORT
      LAYER met3 ;
        RECT 896.000 826.240 900.000 826.840 ;
    END
  END s_axi_rdata[87]
  PIN s_axi_rdata[88]
    DIRECTION OUTPUT ;
    USE SIGNAL ;
    ANTENNADIFFAREA 0.340600 ;
    PORT
      LAYER met3 ;
        RECT 896.000 737.840 900.000 738.440 ;
    END
  END s_axi_rdata[88]
  PIN s_axi_rdata[89]
    DIRECTION OUTPUT ;
    USE SIGNAL ;
    ANTENNADIFFAREA 0.340600 ;
    PORT
      LAYER met3 ;
        RECT 896.000 714.040 900.000 714.640 ;
    END
  END s_axi_rdata[89]
  PIN s_axi_rdata[8]
    DIRECTION OUTPUT ;
    USE SIGNAL ;
    ANTENNADIFFAREA 0.340600 ;
    PORT
      LAYER met3 ;
        RECT 896.000 771.840 900.000 772.440 ;
    END
  END s_axi_rdata[8]
  PIN s_axi_rdata[90]
    DIRECTION OUTPUT ;
    USE SIGNAL ;
    ANTENNADIFFAREA 0.340600 ;
    PORT
      LAYER met3 ;
        RECT 896.000 686.840 900.000 687.440 ;
    END
  END s_axi_rdata[90]
  PIN s_axi_rdata[91]
    DIRECTION OUTPUT ;
    USE SIGNAL ;
    ANTENNADIFFAREA 0.340600 ;
    PORT
      LAYER met3 ;
        RECT 896.000 816.040 900.000 816.640 ;
    END
  END s_axi_rdata[91]
  PIN s_axi_rdata[92]
    DIRECTION OUTPUT ;
    USE SIGNAL ;
    ANTENNADIFFAREA 0.340600 ;
    PORT
      LAYER met3 ;
        RECT 896.000 775.240 900.000 775.840 ;
    END
  END s_axi_rdata[92]
  PIN s_axi_rdata[93]
    DIRECTION OUTPUT ;
    USE SIGNAL ;
    ANTENNADIFFAREA 0.340600 ;
    PORT
      LAYER met3 ;
        RECT 896.000 744.640 900.000 745.240 ;
    END
  END s_axi_rdata[93]
  PIN s_axi_rdata[94]
    DIRECTION OUTPUT ;
    USE SIGNAL ;
    ANTENNADIFFAREA 0.340600 ;
    PORT
      LAYER met3 ;
        RECT 896.000 697.040 900.000 697.640 ;
    END
  END s_axi_rdata[94]
  PIN s_axi_rdata[95]
    DIRECTION OUTPUT ;
    USE SIGNAL ;
    ANTENNADIFFAREA 0.340600 ;
    PORT
      LAYER met3 ;
        RECT 896.000 778.640 900.000 779.240 ;
    END
  END s_axi_rdata[95]
  PIN s_axi_rdata[96]
    DIRECTION OUTPUT ;
    USE SIGNAL ;
    ANTENNADIFFAREA 0.340600 ;
    PORT
      LAYER met3 ;
        RECT 896.000 768.440 900.000 769.040 ;
    END
  END s_axi_rdata[96]
  PIN s_axi_rdata[97]
    DIRECTION OUTPUT ;
    USE SIGNAL ;
    ANTENNADIFFAREA 0.340600 ;
    PORT
      LAYER met3 ;
        RECT 896.000 829.640 900.000 830.240 ;
    END
  END s_axi_rdata[97]
  PIN s_axi_rdata[98]
    DIRECTION OUTPUT ;
    USE SIGNAL ;
    ANTENNADIFFAREA 0.340600 ;
    PORT
      LAYER met3 ;
        RECT 896.000 782.040 900.000 782.640 ;
    END
  END s_axi_rdata[98]
  PIN s_axi_rdata[99]
    DIRECTION OUTPUT ;
    USE SIGNAL ;
    ANTENNADIFFAREA 0.340600 ;
    PORT
      LAYER met3 ;
        RECT 896.000 833.040 900.000 833.640 ;
    END
  END s_axi_rdata[99]
  PIN s_axi_rdata[9]
    DIRECTION OUTPUT ;
    USE SIGNAL ;
    ANTENNADIFFAREA 0.340600 ;
    PORT
      LAYER met3 ;
        RECT 896.000 683.440 900.000 684.040 ;
    END
  END s_axi_rdata[9]
  PIN s_axi_rready[0]
    DIRECTION INPUT ;
    USE SIGNAL ;
    ANTENNAGATEAREA 0.196500 ;
    PORT
      LAYER met3 ;
        RECT 896.000 785.440 900.000 786.040 ;
    END
  END s_axi_rready[0]
  PIN s_axi_rready[1]
    DIRECTION INPUT ;
    USE SIGNAL ;
    ANTENNAGATEAREA 0.196500 ;
    PORT
      LAYER met3 ;
        RECT 896.000 700.440 900.000 701.040 ;
    END
  END s_axi_rready[1]
  PIN s_axi_rready[2]
    DIRECTION INPUT ;
    USE SIGNAL ;
    ANTENNAGATEAREA 0.196500 ;
    PORT
      LAYER met3 ;
        RECT 896.000 724.240 900.000 724.840 ;
    END
  END s_axi_rready[2]
  PIN s_axi_rready[3]
    DIRECTION INPUT ;
    USE SIGNAL ;
    ANTENNAGATEAREA 0.196500 ;
    PORT
      LAYER met3 ;
        RECT 896.000 788.840 900.000 789.440 ;
    END
  END s_axi_rready[3]
  PIN s_axi_rresp[0]
    DIRECTION OUTPUT ;
    USE SIGNAL ;
    ANTENNADIFFAREA 0.340600 ;
    PORT
      LAYER met3 ;
        RECT 896.000 727.640 900.000 728.240 ;
    END
  END s_axi_rresp[0]
  PIN s_axi_rresp[1]
    DIRECTION OUTPUT ;
    USE SIGNAL ;
    ANTENNADIFFAREA 0.340600 ;
    PORT
      LAYER met3 ;
        RECT 896.000 707.240 900.000 707.840 ;
    END
  END s_axi_rresp[1]
  PIN s_axi_rresp[2]
    DIRECTION OUTPUT ;
    USE SIGNAL ;
    ANTENNADIFFAREA 0.340600 ;
    PORT
      LAYER met3 ;
        RECT 896.000 792.240 900.000 792.840 ;
    END
  END s_axi_rresp[2]
  PIN s_axi_rresp[3]
    DIRECTION OUTPUT ;
    USE SIGNAL ;
    ANTENNADIFFAREA 0.340600 ;
    PORT
      LAYER met3 ;
        RECT 896.000 710.640 900.000 711.240 ;
    END
  END s_axi_rresp[3]
  PIN s_axi_rresp[4]
    DIRECTION OUTPUT ;
    USE SIGNAL ;
    ANTENNADIFFAREA 0.340600 ;
    PORT
      LAYER met3 ;
        RECT 896.000 734.440 900.000 735.040 ;
    END
  END s_axi_rresp[4]
  PIN s_axi_rresp[5]
    DIRECTION OUTPUT ;
    USE SIGNAL ;
    ANTENNADIFFAREA 0.340600 ;
    PORT
      LAYER met3 ;
        RECT 896.000 819.440 900.000 820.040 ;
    END
  END s_axi_rresp[5]
  PIN s_axi_rresp[6]
    DIRECTION OUTPUT ;
    USE SIGNAL ;
    ANTENNADIFFAREA 0.340600 ;
    PORT
      LAYER met3 ;
        RECT 896.000 795.640 900.000 796.240 ;
    END
  END s_axi_rresp[6]
  PIN s_axi_rresp[7]
    DIRECTION OUTPUT ;
    USE SIGNAL ;
    ANTENNADIFFAREA 0.340600 ;
    PORT
      LAYER met3 ;
        RECT 896.000 751.440 900.000 752.040 ;
    END
  END s_axi_rresp[7]
  PIN s_axi_rvalid[0]
    DIRECTION OUTPUT ;
    USE SIGNAL ;
    ANTENNADIFFAREA 0.340600 ;
    PORT
      LAYER met3 ;
        RECT 896.000 741.240 900.000 741.840 ;
    END
  END s_axi_rvalid[0]
  PIN s_axi_rvalid[1]
    DIRECTION OUTPUT ;
    USE SIGNAL ;
    ANTENNADIFFAREA 0.340600 ;
    PORT
      LAYER met3 ;
        RECT 896.000 693.640 900.000 694.240 ;
    END
  END s_axi_rvalid[1]
  PIN s_axi_rvalid[2]
    DIRECTION OUTPUT ;
    USE SIGNAL ;
    ANTENNADIFFAREA 0.340600 ;
    PORT
      LAYER met3 ;
        RECT 896.000 799.040 900.000 799.640 ;
    END
  END s_axi_rvalid[2]
  PIN s_axi_rvalid[3]
    DIRECTION OUTPUT ;
    USE SIGNAL ;
    ANTENNADIFFAREA 0.340600 ;
    PORT
      LAYER met3 ;
        RECT 896.000 822.840 900.000 823.440 ;
    END
  END s_axi_rvalid[3]
  PIN s_axi_wdata[0]
    DIRECTION INPUT ;
    USE SIGNAL ;
    ANTENNAGATEAREA 0.126000 ;
    PORT
      LAYER met2 ;
        RECT 444.450 0.000 444.730 4.000 ;
    END
  END s_axi_wdata[0]
  PIN s_axi_wdata[100]
    DIRECTION INPUT ;
    USE SIGNAL ;
    ANTENNAGATEAREA 0.126000 ;
    PORT
      LAYER met2 ;
        RECT 45.170 0.000 45.450 4.000 ;
    END
  END s_axi_wdata[100]
  PIN s_axi_wdata[101]
    DIRECTION INPUT ;
    USE SIGNAL ;
    ANTENNAGATEAREA 0.126000 ;
    PORT
      LAYER met2 ;
        RECT 405.810 0.000 406.090 4.000 ;
    END
  END s_axi_wdata[101]
  PIN s_axi_wdata[102]
    DIRECTION INPUT ;
    USE SIGNAL ;
    ANTENNAGATEAREA 0.126000 ;
    PORT
      LAYER met2 ;
        RECT 412.250 0.000 412.530 4.000 ;
    END
  END s_axi_wdata[102]
  PIN s_axi_wdata[103]
    DIRECTION INPUT ;
    USE SIGNAL ;
    ANTENNAGATEAREA 0.126000 ;
    PORT
      LAYER met2 ;
        RECT 186.850 896.000 187.130 900.000 ;
    END
  END s_axi_wdata[103]
  PIN s_axi_wdata[104]
    DIRECTION INPUT ;
    USE SIGNAL ;
    ANTENNAGATEAREA 0.126000 ;
    PORT
      LAYER met2 ;
        RECT 219.050 896.000 219.330 900.000 ;
    END
  END s_axi_wdata[104]
  PIN s_axi_wdata[105]
    DIRECTION INPUT ;
    USE SIGNAL ;
    ANTENNAGATEAREA 0.126000 ;
    PORT
      LAYER met2 ;
        RECT 180.410 896.000 180.690 900.000 ;
    END
  END s_axi_wdata[105]
  PIN s_axi_wdata[106]
    DIRECTION INPUT ;
    USE SIGNAL ;
    ANTENNAGATEAREA 0.126000 ;
    PORT
      LAYER met2 ;
        RECT 177.190 896.000 177.470 900.000 ;
    END
  END s_axi_wdata[106]
  PIN s_axi_wdata[107]
    DIRECTION INPUT ;
    USE SIGNAL ;
    ANTENNAGATEAREA 0.126000 ;
    PORT
      LAYER met2 ;
        RECT 22.630 0.000 22.910 4.000 ;
    END
  END s_axi_wdata[107]
  PIN s_axi_wdata[108]
    DIRECTION INPUT ;
    USE SIGNAL ;
    ANTENNAGATEAREA 0.126000 ;
    PORT
      LAYER met2 ;
        RECT 109.570 896.000 109.850 900.000 ;
    END
  END s_axi_wdata[108]
  PIN s_axi_wdata[109]
    DIRECTION INPUT ;
    USE SIGNAL ;
    ANTENNAGATEAREA 0.126000 ;
    PORT
      LAYER met2 ;
        RECT 41.950 896.000 42.230 900.000 ;
    END
  END s_axi_wdata[109]
  PIN s_axi_wdata[10]
    DIRECTION INPUT ;
    USE SIGNAL ;
    ANTENNAGATEAREA 0.126000 ;
    PORT
      LAYER met2 ;
        RECT 235.150 896.000 235.430 900.000 ;
    END
  END s_axi_wdata[10]
  PIN s_axi_wdata[110]
    DIRECTION INPUT ;
    USE SIGNAL ;
    ANTENNAGATEAREA 0.126000 ;
    PORT
      LAYER met2 ;
        RECT 29.070 896.000 29.350 900.000 ;
    END
  END s_axi_wdata[110]
  PIN s_axi_wdata[111]
    DIRECTION INPUT ;
    USE SIGNAL ;
    ANTENNAGATEAREA 0.126000 ;
    PORT
      LAYER met2 ;
        RECT 70.930 896.000 71.210 900.000 ;
    END
  END s_axi_wdata[111]
  PIN s_axi_wdata[112]
    DIRECTION INPUT ;
    USE SIGNAL ;
    ANTENNAGATEAREA 0.126000 ;
    PORT
      LAYER met2 ;
        RECT 99.910 896.000 100.190 900.000 ;
    END
  END s_axi_wdata[112]
  PIN s_axi_wdata[113]
    DIRECTION INPUT ;
    USE SIGNAL ;
    ANTENNAGATEAREA 0.126000 ;
    PORT
      LAYER met2 ;
        RECT 138.550 896.000 138.830 900.000 ;
    END
  END s_axi_wdata[113]
  PIN s_axi_wdata[114]
    DIRECTION INPUT ;
    USE SIGNAL ;
    ANTENNAGATEAREA 0.126000 ;
    PORT
      LAYER met2 ;
        RECT 16.190 896.000 16.470 900.000 ;
    END
  END s_axi_wdata[114]
  PIN s_axi_wdata[115]
    DIRECTION INPUT ;
    USE SIGNAL ;
    ANTENNAGATEAREA 0.126000 ;
    PORT
      LAYER met2 ;
        RECT 9.750 896.000 10.030 900.000 ;
    END
  END s_axi_wdata[115]
  PIN s_axi_wdata[116]
    DIRECTION INPUT ;
    USE SIGNAL ;
    ANTENNAGATEAREA 0.126000 ;
    PORT
      LAYER met2 ;
        RECT 170.750 896.000 171.030 900.000 ;
    END
  END s_axi_wdata[116]
  PIN s_axi_wdata[117]
    DIRECTION INPUT ;
    USE SIGNAL ;
    ANTENNAGATEAREA 0.126000 ;
    PORT
      LAYER met2 ;
        RECT 93.470 896.000 93.750 900.000 ;
    END
  END s_axi_wdata[117]
  PIN s_axi_wdata[118]
    DIRECTION INPUT ;
    USE SIGNAL ;
    ANTENNAGATEAREA 0.126000 ;
    PORT
      LAYER met2 ;
        RECT 196.510 896.000 196.790 900.000 ;
    END
  END s_axi_wdata[118]
  PIN s_axi_wdata[119]
    DIRECTION INPUT ;
    USE SIGNAL ;
    ANTENNAGATEAREA 0.126000 ;
    PORT
      LAYER met2 ;
        RECT 106.350 896.000 106.630 900.000 ;
    END
  END s_axi_wdata[119]
  PIN s_axi_wdata[11]
    DIRECTION INPUT ;
    USE SIGNAL ;
    ANTENNAGATEAREA 0.126000 ;
    PORT
      LAYER met2 ;
        RECT 228.710 896.000 228.990 900.000 ;
    END
  END s_axi_wdata[11]
  PIN s_axi_wdata[120]
    DIRECTION INPUT ;
    USE SIGNAL ;
    ANTENNAGATEAREA 0.126000 ;
    PORT
      LAYER met2 ;
        RECT 209.390 896.000 209.670 900.000 ;
    END
  END s_axi_wdata[120]
  PIN s_axi_wdata[121]
    DIRECTION INPUT ;
    USE SIGNAL ;
    ANTENNAGATEAREA 0.126000 ;
    PORT
      LAYER met2 ;
        RECT 132.110 0.000 132.390 4.000 ;
    END
  END s_axi_wdata[121]
  PIN s_axi_wdata[122]
    DIRECTION INPUT ;
    USE SIGNAL ;
    ANTENNAGATEAREA 0.126000 ;
    PORT
      LAYER met2 ;
        RECT 96.690 0.000 96.970 4.000 ;
    END
  END s_axi_wdata[122]
  PIN s_axi_wdata[123]
    DIRECTION INPUT ;
    USE SIGNAL ;
    ANTENNAGATEAREA 0.126000 ;
    PORT
      LAYER met2 ;
        RECT 106.350 0.000 106.630 4.000 ;
    END
  END s_axi_wdata[123]
  PIN s_axi_wdata[124]
    DIRECTION INPUT ;
    USE SIGNAL ;
    ANTENNAGATEAREA 0.159000 ;
    PORT
      LAYER met2 ;
        RECT 112.790 0.000 113.070 4.000 ;
    END
  END s_axi_wdata[124]
  PIN s_axi_wdata[125]
    DIRECTION INPUT ;
    USE SIGNAL ;
    ANTENNAGATEAREA 0.126000 ;
    PORT
      LAYER met2 ;
        RECT 119.230 0.000 119.510 4.000 ;
    END
  END s_axi_wdata[125]
  PIN s_axi_wdata[126]
    DIRECTION INPUT ;
    USE SIGNAL ;
    ANTENNAGATEAREA 0.126000 ;
    PORT
      LAYER met2 ;
        RECT 122.450 0.000 122.730 4.000 ;
    END
  END s_axi_wdata[126]
  PIN s_axi_wdata[127]
    DIRECTION INPUT ;
    USE SIGNAL ;
    ANTENNAGATEAREA 0.126000 ;
    PORT
      LAYER met2 ;
        RECT 128.890 0.000 129.170 4.000 ;
    END
  END s_axi_wdata[127]
  PIN s_axi_wdata[12]
    DIRECTION INPUT ;
    USE SIGNAL ;
    ANTENNAGATEAREA 0.126000 ;
    PORT
      LAYER met2 ;
        RECT 154.650 896.000 154.930 900.000 ;
    END
  END s_axi_wdata[12]
  PIN s_axi_wdata[13]
    DIRECTION INPUT ;
    USE SIGNAL ;
    ANTENNAGATEAREA 0.126000 ;
    PORT
      LAYER met2 ;
        RECT 25.850 896.000 26.130 900.000 ;
    END
  END s_axi_wdata[13]
  PIN s_axi_wdata[14]
    DIRECTION INPUT ;
    USE SIGNAL ;
    ANTENNAGATEAREA 0.126000 ;
    PORT
      LAYER met2 ;
        RECT 38.730 896.000 39.010 900.000 ;
    END
  END s_axi_wdata[14]
  PIN s_axi_wdata[15]
    DIRECTION INPUT ;
    USE SIGNAL ;
    ANTENNAGATEAREA 0.126000 ;
    PORT
      LAYER met2 ;
        RECT 48.390 896.000 48.670 900.000 ;
    END
  END s_axi_wdata[15]
  PIN s_axi_wdata[16]
    DIRECTION INPUT ;
    USE SIGNAL ;
    ANTENNAGATEAREA 0.126000 ;
    PORT
      LAYER met2 ;
        RECT 103.130 896.000 103.410 900.000 ;
    END
  END s_axi_wdata[16]
  PIN s_axi_wdata[17]
    DIRECTION INPUT ;
    USE SIGNAL ;
    ANTENNAGATEAREA 0.126000 ;
    PORT
      LAYER met2 ;
        RECT 135.330 896.000 135.610 900.000 ;
    END
  END s_axi_wdata[17]
  PIN s_axi_wdata[18]
    DIRECTION INPUT ;
    USE SIGNAL ;
    ANTENNAGATEAREA 0.126000 ;
    PORT
      LAYER met2 ;
        RECT 35.510 0.000 35.790 4.000 ;
    END
  END s_axi_wdata[18]
  PIN s_axi_wdata[19]
    DIRECTION INPUT ;
    USE SIGNAL ;
    ANTENNAGATEAREA 0.126000 ;
    PORT
      LAYER met2 ;
        RECT 29.070 0.000 29.350 4.000 ;
    END
  END s_axi_wdata[19]
  PIN s_axi_wdata[1]
    DIRECTION INPUT ;
    USE SIGNAL ;
    ANTENNAGATEAREA 0.126000 ;
    PORT
      LAYER met2 ;
        RECT 399.370 0.000 399.650 4.000 ;
    END
  END s_axi_wdata[1]
  PIN s_axi_wdata[20]
    DIRECTION INPUT ;
    USE SIGNAL ;
    ANTENNAGATEAREA 0.126000 ;
    PORT
      LAYER met2 ;
        RECT 151.430 896.000 151.710 900.000 ;
    END
  END s_axi_wdata[20]
  PIN s_axi_wdata[21]
    DIRECTION INPUT ;
    USE SIGNAL ;
    ANTENNAGATEAREA 0.126000 ;
    PORT
      LAYER met2 ;
        RECT 164.310 896.000 164.590 900.000 ;
    END
  END s_axi_wdata[21]
  PIN s_axi_wdata[22]
    DIRECTION INPUT ;
    USE SIGNAL ;
    ANTENNAGATEAREA 0.126000 ;
    PORT
      LAYER met2 ;
        RECT 112.790 896.000 113.070 900.000 ;
    END
  END s_axi_wdata[22]
  PIN s_axi_wdata[23]
    DIRECTION INPUT ;
    USE SIGNAL ;
    ANTENNAGATEAREA 0.213000 ;
    PORT
      LAYER met2 ;
        RECT 132.110 896.000 132.390 900.000 ;
    END
  END s_axi_wdata[23]
  PIN s_axi_wdata[24]
    DIRECTION INPUT ;
    USE SIGNAL ;
    ANTENNAGATEAREA 0.126000 ;
    PORT
      LAYER met2 ;
        RECT 144.990 896.000 145.270 900.000 ;
    END
  END s_axi_wdata[24]
  PIN s_axi_wdata[25]
    DIRECTION INPUT ;
    USE SIGNAL ;
    ANTENNAGATEAREA 0.126000 ;
    PORT
      LAYER met2 ;
        RECT 103.130 0.000 103.410 4.000 ;
    END
  END s_axi_wdata[25]
  PIN s_axi_wdata[26]
    DIRECTION INPUT ;
    USE SIGNAL ;
    ANTENNAGATEAREA 0.126000 ;
    PORT
      LAYER met2 ;
        RECT 74.150 0.000 74.430 4.000 ;
    END
  END s_axi_wdata[26]
  PIN s_axi_wdata[27]
    DIRECTION INPUT ;
    USE SIGNAL ;
    ANTENNAGATEAREA 0.126000 ;
    PORT
      LAYER met2 ;
        RECT 54.830 0.000 55.110 4.000 ;
    END
  END s_axi_wdata[27]
  PIN s_axi_wdata[28]
    DIRECTION INPUT ;
    USE SIGNAL ;
    ANTENNAGATEAREA 0.126000 ;
    PORT
      LAYER met2 ;
        RECT 90.250 0.000 90.530 4.000 ;
    END
  END s_axi_wdata[28]
  PIN s_axi_wdata[29]
    DIRECTION INPUT ;
    USE SIGNAL ;
    ANTENNAGATEAREA 0.126000 ;
    PORT
      LAYER met2 ;
        RECT 64.490 0.000 64.770 4.000 ;
    END
  END s_axi_wdata[29]
  PIN s_axi_wdata[2]
    DIRECTION INPUT ;
    USE SIGNAL ;
    ANTENNAGATEAREA 0.126000 ;
    PORT
      LAYER met2 ;
        RECT 431.570 0.000 431.850 4.000 ;
    END
  END s_axi_wdata[2]
  PIN s_axi_wdata[30]
    DIRECTION INPUT ;
    USE SIGNAL ;
    ANTENNAGATEAREA 0.126000 ;
    PORT
      LAYER met2 ;
        RECT 99.910 0.000 100.190 4.000 ;
    END
  END s_axi_wdata[30]
  PIN s_axi_wdata[31]
    DIRECTION INPUT ;
    USE SIGNAL ;
    ANTENNAGATEAREA 0.126000 ;
    PORT
      LAYER met2 ;
        RECT 116.010 0.000 116.290 4.000 ;
    END
  END s_axi_wdata[31]
  PIN s_axi_wdata[32]
    DIRECTION INPUT ;
    USE SIGNAL ;
    ANTENNAGATEAREA 0.126000 ;
    PORT
      LAYER met2 ;
        RECT 428.350 0.000 428.630 4.000 ;
    END
  END s_axi_wdata[32]
  PIN s_axi_wdata[33]
    DIRECTION INPUT ;
    USE SIGNAL ;
    ANTENNAGATEAREA 0.126000 ;
    PORT
      LAYER met2 ;
        RECT 386.490 0.000 386.770 4.000 ;
    END
  END s_axi_wdata[33]
  PIN s_axi_wdata[34]
    DIRECTION INPUT ;
    USE SIGNAL ;
    ANTENNAGATEAREA 0.126000 ;
    PORT
      LAYER met2 ;
        RECT 450.890 0.000 451.170 4.000 ;
    END
  END s_axi_wdata[34]
  PIN s_axi_wdata[35]
    DIRECTION INPUT ;
    USE SIGNAL ;
    ANTENNAGATEAREA 0.126000 ;
    PORT
      LAYER met2 ;
        RECT 457.330 0.000 457.610 4.000 ;
    END
  END s_axi_wdata[35]
  PIN s_axi_wdata[36]
    DIRECTION INPUT ;
    USE SIGNAL ;
    ANTENNAGATEAREA 0.126000 ;
    PORT
      LAYER met2 ;
        RECT 389.710 0.000 389.990 4.000 ;
    END
  END s_axi_wdata[36]
  PIN s_axi_wdata[37]
    DIRECTION INPUT ;
    USE SIGNAL ;
    ANTENNAGATEAREA 0.126000 ;
    PORT
      LAYER met2 ;
        RECT 486.310 0.000 486.590 4.000 ;
    END
  END s_axi_wdata[37]
  PIN s_axi_wdata[38]
    DIRECTION INPUT ;
    USE SIGNAL ;
    ANTENNAGATEAREA 0.126000 ;
    PORT
      LAYER met2 ;
        RECT 415.470 0.000 415.750 4.000 ;
    END
  END s_axi_wdata[38]
  PIN s_axi_wdata[39]
    DIRECTION INPUT ;
    USE SIGNAL ;
    ANTENNAGATEAREA 0.126000 ;
    PORT
      LAYER met2 ;
        RECT 248.030 896.000 248.310 900.000 ;
    END
  END s_axi_wdata[39]
  PIN s_axi_wdata[3]
    DIRECTION INPUT ;
    USE SIGNAL ;
    ANTENNAGATEAREA 0.126000 ;
    PORT
      LAYER met2 ;
        RECT 460.550 0.000 460.830 4.000 ;
    END
  END s_axi_wdata[3]
  PIN s_axi_wdata[40]
    DIRECTION INPUT ;
    USE SIGNAL ;
    ANTENNAGATEAREA 0.126000 ;
    PORT
      LAYER met2 ;
        RECT 231.930 896.000 232.210 900.000 ;
    END
  END s_axi_wdata[40]
  PIN s_axi_wdata[41]
    DIRECTION INPUT ;
    USE SIGNAL ;
    ANTENNAGATEAREA 0.126000 ;
    PORT
      LAYER met2 ;
        RECT 22.630 896.000 22.910 900.000 ;
    END
  END s_axi_wdata[41]
  PIN s_axi_wdata[42]
    DIRECTION INPUT ;
    USE SIGNAL ;
    ANTENNAGATEAREA 0.126000 ;
    PORT
      LAYER met2 ;
        RECT 212.610 896.000 212.890 900.000 ;
    END
  END s_axi_wdata[42]
  PIN s_axi_wdata[43]
    DIRECTION INPUT ;
    USE SIGNAL ;
    ANTENNAGATEAREA 0.126000 ;
    PORT
      LAYER met2 ;
        RECT 383.270 0.000 383.550 4.000 ;
    END
  END s_axi_wdata[43]
  PIN s_axi_wdata[44]
    DIRECTION INPUT ;
    USE SIGNAL ;
    ANTENNAGATEAREA 0.126000 ;
    PORT
      LAYER met2 ;
        RECT 51.610 896.000 51.890 900.000 ;
    END
  END s_axi_wdata[44]
  PIN s_axi_wdata[45]
    DIRECTION INPUT ;
    USE SIGNAL ;
    ANTENNAGATEAREA 0.126000 ;
    PORT
      LAYER met2 ;
        RECT 6.530 896.000 6.810 900.000 ;
    END
  END s_axi_wdata[45]
  PIN s_axi_wdata[46]
    DIRECTION INPUT ;
    USE SIGNAL ;
    ANTENNAGATEAREA 0.126000 ;
    PORT
      LAYER met2 ;
        RECT 161.090 896.000 161.370 900.000 ;
    END
  END s_axi_wdata[46]
  PIN s_axi_wdata[47]
    DIRECTION INPUT ;
    USE SIGNAL ;
    ANTENNAGATEAREA 0.126000 ;
    PORT
      LAYER met2 ;
        RECT 116.010 896.000 116.290 900.000 ;
    END
  END s_axi_wdata[47]
  PIN s_axi_wdata[48]
    DIRECTION INPUT ;
    USE SIGNAL ;
    ANTENNAGATEAREA 0.126000 ;
    PORT
      LAYER met2 ;
        RECT 119.230 896.000 119.510 900.000 ;
    END
  END s_axi_wdata[48]
  PIN s_axi_wdata[49]
    DIRECTION INPUT ;
    USE SIGNAL ;
    ANTENNAGATEAREA 0.126000 ;
    PORT
      LAYER met2 ;
        RECT 148.210 896.000 148.490 900.000 ;
    END
  END s_axi_wdata[49]
  PIN s_axi_wdata[4]
    DIRECTION INPUT ;
    USE SIGNAL ;
    ANTENNAGATEAREA 0.126000 ;
    PORT
      LAYER met2 ;
        RECT 376.830 0.000 377.110 4.000 ;
    END
  END s_axi_wdata[4]
  PIN s_axi_wdata[50]
    DIRECTION INPUT ;
    USE SIGNAL ;
    ANTENNAGATEAREA 0.126000 ;
    PORT
      LAYER met2 ;
        RECT 41.950 0.000 42.230 4.000 ;
    END
  END s_axi_wdata[50]
  PIN s_axi_wdata[51]
    DIRECTION INPUT ;
    USE SIGNAL ;
    ANTENNAGATEAREA 0.126000 ;
    PORT
      LAYER met2 ;
        RECT 19.410 0.000 19.690 4.000 ;
    END
  END s_axi_wdata[51]
  PIN s_axi_wdata[52]
    DIRECTION INPUT ;
    USE SIGNAL ;
    ANTENNAGATEAREA 0.126000 ;
    PORT
      LAYER met2 ;
        RECT 122.450 896.000 122.730 900.000 ;
    END
  END s_axi_wdata[52]
  PIN s_axi_wdata[53]
    DIRECTION INPUT ;
    USE SIGNAL ;
    ANTENNAGATEAREA 0.126000 ;
    PORT
      LAYER met2 ;
        RECT 173.970 896.000 174.250 900.000 ;
    END
  END s_axi_wdata[53]
  PIN s_axi_wdata[54]
    DIRECTION INPUT ;
    USE SIGNAL ;
    ANTENNAGATEAREA 0.126000 ;
    PORT
      LAYER met2 ;
        RECT 80.590 896.000 80.870 900.000 ;
    END
  END s_axi_wdata[54]
  PIN s_axi_wdata[55]
    DIRECTION INPUT ;
    USE SIGNAL ;
    ANTENNAGATEAREA 0.126000 ;
    PORT
      LAYER met2 ;
        RECT 58.050 0.000 58.330 4.000 ;
    END
  END s_axi_wdata[55]
  PIN s_axi_wdata[56]
    DIRECTION INPUT ;
    USE SIGNAL ;
    ANTENNAGATEAREA 0.126000 ;
    PORT
      LAYER met2 ;
        RECT 215.830 896.000 216.110 900.000 ;
    END
  END s_axi_wdata[56]
  PIN s_axi_wdata[57]
    DIRECTION INPUT ;
    USE SIGNAL ;
    ANTENNAGATEAREA 0.126000 ;
    PORT
      LAYER met2 ;
        RECT 138.550 0.000 138.830 4.000 ;
    END
  END s_axi_wdata[57]
  PIN s_axi_wdata[58]
    DIRECTION INPUT ;
    USE SIGNAL ;
    ANTENNAGATEAREA 0.126000 ;
    PORT
      LAYER met2 ;
        RECT 70.930 0.000 71.210 4.000 ;
    END
  END s_axi_wdata[58]
  PIN s_axi_wdata[59]
    DIRECTION INPUT ;
    USE SIGNAL ;
    ANTENNAGATEAREA 0.126000 ;
    PORT
      LAYER met2 ;
        RECT 38.730 0.000 39.010 4.000 ;
    END
  END s_axi_wdata[59]
  PIN s_axi_wdata[5]
    DIRECTION INPUT ;
    USE SIGNAL ;
    ANTENNAGATEAREA 0.126000 ;
    PORT
      LAYER met2 ;
        RECT 447.670 0.000 447.950 4.000 ;
    END
  END s_axi_wdata[5]
  PIN s_axi_wdata[60]
    DIRECTION INPUT ;
    USE SIGNAL ;
    ANTENNAGATEAREA 0.126000 ;
    PORT
      LAYER met2 ;
        RECT 83.810 0.000 84.090 4.000 ;
    END
  END s_axi_wdata[60]
  PIN s_axi_wdata[61]
    DIRECTION INPUT ;
    USE SIGNAL ;
    ANTENNAGATEAREA 0.126000 ;
    PORT
      LAYER met2 ;
        RECT 80.590 0.000 80.870 4.000 ;
    END
  END s_axi_wdata[61]
  PIN s_axi_wdata[62]
    DIRECTION INPUT ;
    USE SIGNAL ;
    ANTENNAGATEAREA 0.126000 ;
    PORT
      LAYER met2 ;
        RECT 93.470 0.000 93.750 4.000 ;
    END
  END s_axi_wdata[62]
  PIN s_axi_wdata[63]
    DIRECTION INPUT ;
    USE SIGNAL ;
    ANTENNAGATEAREA 0.126000 ;
    PORT
      LAYER met2 ;
        RECT 109.570 0.000 109.850 4.000 ;
    END
  END s_axi_wdata[63]
  PIN s_axi_wdata[64]
    DIRECTION INPUT ;
    USE SIGNAL ;
    ANTENNAGATEAREA 0.126000 ;
    PORT
      LAYER met2 ;
        RECT 566.810 0.000 567.090 4.000 ;
    END
  END s_axi_wdata[64]
  PIN s_axi_wdata[65]
    DIRECTION INPUT ;
    USE SIGNAL ;
    ANTENNAGATEAREA 0.126000 ;
    PORT
      LAYER met2 ;
        RECT 77.370 0.000 77.650 4.000 ;
    END
  END s_axi_wdata[65]
  PIN s_axi_wdata[66]
    DIRECTION INPUT ;
    USE SIGNAL ;
    ANTENNAGATEAREA 0.126000 ;
    PORT
      LAYER met2 ;
        RECT 183.630 896.000 183.910 900.000 ;
    END
  END s_axi_wdata[66]
  PIN s_axi_wdata[67]
    DIRECTION INPUT ;
    USE SIGNAL ;
    ANTENNAGATEAREA 0.126000 ;
    PORT
      LAYER met2 ;
        RECT 254.470 896.000 254.750 900.000 ;
    END
  END s_axi_wdata[67]
  PIN s_axi_wdata[68]
    DIRECTION INPUT ;
    USE SIGNAL ;
    ANTENNAGATEAREA 0.126000 ;
    PORT
      LAYER met2 ;
        RECT 241.590 896.000 241.870 900.000 ;
    END
  END s_axi_wdata[68]
  PIN s_axi_wdata[69]
    DIRECTION INPUT ;
    USE SIGNAL ;
    ANTENNAGATEAREA 0.126000 ;
    PORT
      LAYER met2 ;
        RECT 12.970 896.000 13.250 900.000 ;
    END
  END s_axi_wdata[69]
  PIN s_axi_wdata[6]
    DIRECTION INPUT ;
    USE SIGNAL ;
    ANTENNAGATEAREA 0.126000 ;
    PORT
      LAYER met2 ;
        RECT 251.250 896.000 251.530 900.000 ;
    END
  END s_axi_wdata[6]
  PIN s_axi_wdata[70]
    DIRECTION INPUT ;
    USE SIGNAL ;
    ANTENNAGATEAREA 0.126000 ;
    PORT
      LAYER met2 ;
        RECT 19.410 896.000 19.690 900.000 ;
    END
  END s_axi_wdata[70]
  PIN s_axi_wdata[71]
    DIRECTION INPUT ;
    USE SIGNAL ;
    ANTENNAGATEAREA 0.126000 ;
    PORT
      LAYER met2 ;
        RECT 193.290 896.000 193.570 900.000 ;
    END
  END s_axi_wdata[71]
  PIN s_axi_wdata[72]
    DIRECTION INPUT ;
    USE SIGNAL ;
    ANTENNAGATEAREA 0.126000 ;
    PORT
      LAYER met2 ;
        RECT 83.810 896.000 84.090 900.000 ;
    END
  END s_axi_wdata[72]
  PIN s_axi_wdata[73]
    DIRECTION INPUT ;
    USE SIGNAL ;
    ANTENNAGATEAREA 0.126000 ;
    PORT
      LAYER met2 ;
        RECT 77.370 896.000 77.650 900.000 ;
    END
  END s_axi_wdata[73]
  PIN s_axi_wdata[74]
    DIRECTION INPUT ;
    USE SIGNAL ;
    ANTENNAGATEAREA 0.126000 ;
    PORT
      LAYER met2 ;
        RECT 3.310 896.000 3.590 900.000 ;
    END
  END s_axi_wdata[74]
  PIN s_axi_wdata[75]
    DIRECTION INPUT ;
    USE SIGNAL ;
    ANTENNAGATEAREA 0.126000 ;
    PORT
      LAYER met2 ;
        RECT 225.490 896.000 225.770 900.000 ;
    END
  END s_axi_wdata[75]
  PIN s_axi_wdata[76]
    DIRECTION INPUT ;
    USE SIGNAL ;
    ANTENNAGATEAREA 0.126000 ;
    PORT
      LAYER met2 ;
        RECT 32.290 896.000 32.570 900.000 ;
    END
  END s_axi_wdata[76]
  PIN s_axi_wdata[77]
    DIRECTION INPUT ;
    USE SIGNAL ;
    ANTENNAGATEAREA 0.126000 ;
    PORT
      LAYER met2 ;
        RECT 67.710 896.000 67.990 900.000 ;
    END
  END s_axi_wdata[77]
  PIN s_axi_wdata[78]
    DIRECTION INPUT ;
    USE SIGNAL ;
    ANTENNAGATEAREA 0.126000 ;
    PORT
      LAYER met2 ;
        RECT 61.270 896.000 61.550 900.000 ;
    END
  END s_axi_wdata[78]
  PIN s_axi_wdata[79]
    DIRECTION INPUT ;
    USE SIGNAL ;
    ANTENNAGATEAREA 0.126000 ;
    PORT
      LAYER met2 ;
        RECT 35.510 896.000 35.790 900.000 ;
    END
  END s_axi_wdata[79]
  PIN s_axi_wdata[7]
    DIRECTION INPUT ;
    USE SIGNAL ;
    ANTENNAGATEAREA 0.126000 ;
    PORT
      LAYER met2 ;
        RECT 202.950 896.000 203.230 900.000 ;
    END
  END s_axi_wdata[7]
  PIN s_axi_wdata[80]
    DIRECTION INPUT ;
    USE SIGNAL ;
    ANTENNAGATEAREA 0.126000 ;
    PORT
      LAYER met2 ;
        RECT 0.090 896.000 0.370 900.000 ;
    END
  END s_axi_wdata[80]
  PIN s_axi_wdata[81]
    DIRECTION INPUT ;
    USE SIGNAL ;
    ANTENNAGATEAREA 0.126000 ;
    PORT
      LAYER met2 ;
        RECT 54.830 896.000 55.110 900.000 ;
    END
  END s_axi_wdata[81]
  PIN s_axi_wdata[82]
    DIRECTION INPUT ;
    USE SIGNAL ;
    ANTENNAGATEAREA 0.126000 ;
    PORT
      LAYER met2 ;
        RECT 125.670 896.000 125.950 900.000 ;
    END
  END s_axi_wdata[82]
  PIN s_axi_wdata[83]
    DIRECTION INPUT ;
    USE SIGNAL ;
    ANTENNAGATEAREA 0.126000 ;
    PORT
      LAYER met2 ;
        RECT 157.870 896.000 158.150 900.000 ;
    END
  END s_axi_wdata[83]
  PIN s_axi_wdata[84]
    DIRECTION INPUT ;
    USE SIGNAL ;
    ANTENNAGATEAREA 0.126000 ;
    PORT
      LAYER met2 ;
        RECT 141.770 896.000 142.050 900.000 ;
    END
  END s_axi_wdata[84]
  PIN s_axi_wdata[85]
    DIRECTION INPUT ;
    USE SIGNAL ;
    ANTENNAGATEAREA 0.126000 ;
    PORT
      LAYER met2 ;
        RECT 45.170 896.000 45.450 900.000 ;
    END
  END s_axi_wdata[85]
  PIN s_axi_wdata[86]
    DIRECTION INPUT ;
    USE SIGNAL ;
    ANTENNAGATEAREA 0.126000 ;
    PORT
      LAYER met2 ;
        RECT 167.530 896.000 167.810 900.000 ;
    END
  END s_axi_wdata[86]
  PIN s_axi_wdata[87]
    DIRECTION INPUT ;
    USE SIGNAL ;
    ANTENNAGATEAREA 0.126000 ;
    PORT
      LAYER met2 ;
        RECT 90.250 896.000 90.530 900.000 ;
    END
  END s_axi_wdata[87]
  PIN s_axi_wdata[88]
    DIRECTION INPUT ;
    USE SIGNAL ;
    ANTENNAGATEAREA 0.126000 ;
    PORT
      LAYER met2 ;
        RECT 96.690 896.000 96.970 900.000 ;
    END
  END s_axi_wdata[88]
  PIN s_axi_wdata[89]
    DIRECTION INPUT ;
    USE SIGNAL ;
    ANTENNAGATEAREA 0.126000 ;
    PORT
      LAYER met2 ;
        RECT 64.490 896.000 64.770 900.000 ;
    END
  END s_axi_wdata[89]
  PIN s_axi_wdata[8]
    DIRECTION INPUT ;
    USE SIGNAL ;
    ANTENNAGATEAREA 0.126000 ;
    PORT
      LAYER met2 ;
        RECT 244.810 896.000 245.090 900.000 ;
    END
  END s_axi_wdata[8]
  PIN s_axi_wdata[90]
    DIRECTION INPUT ;
    USE SIGNAL ;
    ANTENNAGATEAREA 0.126000 ;
    PORT
      LAYER met2 ;
        RECT 74.150 896.000 74.430 900.000 ;
    END
  END s_axi_wdata[90]
  PIN s_axi_wdata[91]
    DIRECTION INPUT ;
    USE SIGNAL ;
    ANTENNAGATEAREA 0.126000 ;
    PORT
      LAYER met2 ;
        RECT 58.050 896.000 58.330 900.000 ;
    END
  END s_axi_wdata[91]
  PIN s_axi_wdata[92]
    DIRECTION INPUT ;
    USE SIGNAL ;
    ANTENNAGATEAREA 0.126000 ;
    PORT
      LAYER met2 ;
        RECT 199.730 896.000 200.010 900.000 ;
    END
  END s_axi_wdata[92]
  PIN s_axi_wdata[93]
    DIRECTION INPUT ;
    USE SIGNAL ;
    ANTENNAGATEAREA 0.126000 ;
    PORT
      LAYER met2 ;
        RECT 128.890 896.000 129.170 900.000 ;
    END
  END s_axi_wdata[93]
  PIN s_axi_wdata[94]
    DIRECTION INPUT ;
    USE SIGNAL ;
    ANTENNAGATEAREA 0.126000 ;
    PORT
      LAYER met2 ;
        RECT 222.270 896.000 222.550 900.000 ;
    END
  END s_axi_wdata[94]
  PIN s_axi_wdata[95]
    DIRECTION INPUT ;
    USE SIGNAL ;
    ANTENNAGATEAREA 0.213000 ;
    PORT
      LAYER met2 ;
        RECT 87.030 896.000 87.310 900.000 ;
    END
  END s_axi_wdata[95]
  PIN s_axi_wdata[96]
    DIRECTION INPUT ;
    USE SIGNAL ;
    ANTENNAGATEAREA 0.126000 ;
    PORT
      LAYER met2 ;
        RECT 238.370 896.000 238.650 900.000 ;
    END
  END s_axi_wdata[96]
  PIN s_axi_wdata[97]
    DIRECTION INPUT ;
    USE SIGNAL ;
    ANTENNAGATEAREA 0.126000 ;
    PORT
      LAYER met2 ;
        RECT 190.070 896.000 190.350 900.000 ;
    END
  END s_axi_wdata[97]
  PIN s_axi_wdata[98]
    DIRECTION INPUT ;
    USE SIGNAL ;
    ANTENNAGATEAREA 0.126000 ;
    PORT
      LAYER met2 ;
        RECT 206.170 896.000 206.450 900.000 ;
    END
  END s_axi_wdata[98]
  PIN s_axi_wdata[99]
    DIRECTION INPUT ;
    USE SIGNAL ;
    ANTENNAGATEAREA 0.126000 ;
    PORT
      LAYER met3 ;
        RECT 0.000 153.040 4.000 153.640 ;
    END
  END s_axi_wdata[99]
  PIN s_axi_wdata[9]
    DIRECTION INPUT ;
    USE SIGNAL ;
    ANTENNAGATEAREA 0.247500 ;
    PORT
      LAYER met3 ;
        RECT 896.000 748.040 900.000 748.640 ;
    END
  END s_axi_wdata[9]
  PIN s_axi_wready[0]
    DIRECTION OUTPUT ;
    USE SIGNAL ;
    ANTENNADIFFAREA 0.340600 ;
    PORT
      LAYER met3 ;
        RECT 0.000 217.640 4.000 218.240 ;
    END
  END s_axi_wready[0]
  PIN s_axi_wready[1]
    DIRECTION OUTPUT ;
    USE SIGNAL ;
    ANTENNADIFFAREA 0.340600 ;
    PORT
      LAYER met3 ;
        RECT 0.000 163.240 4.000 163.840 ;
    END
  END s_axi_wready[1]
  PIN s_axi_wready[2]
    DIRECTION OUTPUT ;
    USE SIGNAL ;
    ANTENNADIFFAREA 0.340600 ;
    PORT
      LAYER met3 ;
        RECT 896.000 720.840 900.000 721.440 ;
    END
  END s_axi_wready[2]
  PIN s_axi_wready[3]
    DIRECTION OUTPUT ;
    USE SIGNAL ;
    ANTENNADIFFAREA 0.340600 ;
    PORT
      LAYER met3 ;
        RECT 0.000 214.240 4.000 214.840 ;
    END
  END s_axi_wready[3]
  PIN s_axi_wstrb[0]
    DIRECTION INPUT ;
    USE SIGNAL ;
    ANTENNAGATEAREA 0.126000 ;
    PORT
      LAYER met3 ;
        RECT 0.000 207.440 4.000 208.040 ;
    END
  END s_axi_wstrb[0]
  PIN s_axi_wstrb[10]
    DIRECTION INPUT ;
    USE SIGNAL ;
    ANTENNAGATEAREA 0.126000 ;
    PORT
      LAYER met3 ;
        RECT 0.000 180.240 4.000 180.840 ;
    END
  END s_axi_wstrb[10]
  PIN s_axi_wstrb[11]
    DIRECTION INPUT ;
    USE SIGNAL ;
    ANTENNAGATEAREA 0.126000 ;
    PORT
      LAYER met3 ;
        RECT 0.000 183.640 4.000 184.240 ;
    END
  END s_axi_wstrb[11]
  PIN s_axi_wstrb[12]
    DIRECTION INPUT ;
    USE SIGNAL ;
    ANTENNAGATEAREA 0.126000 ;
    PORT
      LAYER met3 ;
        RECT 0.000 159.840 4.000 160.440 ;
    END
  END s_axi_wstrb[12]
  PIN s_axi_wstrb[13]
    DIRECTION INPUT ;
    USE SIGNAL ;
    ANTENNAGATEAREA 0.126000 ;
    PORT
      LAYER met3 ;
        RECT 896.000 802.440 900.000 803.040 ;
    END
  END s_axi_wstrb[13]
  PIN s_axi_wstrb[14]
    DIRECTION INPUT ;
    USE SIGNAL ;
    ANTENNAGATEAREA 0.126000 ;
    PORT
      LAYER met3 ;
        RECT 0.000 176.840 4.000 177.440 ;
    END
  END s_axi_wstrb[14]
  PIN s_axi_wstrb[15]
    DIRECTION INPUT ;
    USE SIGNAL ;
    ANTENNAGATEAREA 0.126000 ;
    PORT
      LAYER met3 ;
        RECT 0.000 204.040 4.000 204.640 ;
    END
  END s_axi_wstrb[15]
  PIN s_axi_wstrb[1]
    DIRECTION INPUT ;
    USE SIGNAL ;
    ANTENNAGATEAREA 0.126000 ;
    PORT
      LAYER met3 ;
        RECT 896.000 703.840 900.000 704.440 ;
    END
  END s_axi_wstrb[1]
  PIN s_axi_wstrb[2]
    DIRECTION INPUT ;
    USE SIGNAL ;
    ANTENNAGATEAREA 0.126000 ;
    PORT
      LAYER met3 ;
        RECT 0.000 210.840 4.000 211.440 ;
    END
  END s_axi_wstrb[2]
  PIN s_axi_wstrb[3]
    DIRECTION INPUT ;
    USE SIGNAL ;
    ANTENNAGATEAREA 0.126000 ;
    PORT
      LAYER met3 ;
        RECT 0.000 173.440 4.000 174.040 ;
    END
  END s_axi_wstrb[3]
  PIN s_axi_wstrb[4]
    DIRECTION INPUT ;
    USE SIGNAL ;
    ANTENNAGATEAREA 0.126000 ;
    PORT
      LAYER met3 ;
        RECT 0.000 193.840 4.000 194.440 ;
    END
  END s_axi_wstrb[4]
  PIN s_axi_wstrb[5]
    DIRECTION INPUT ;
    USE SIGNAL ;
    ANTENNAGATEAREA 0.126000 ;
    PORT
      LAYER met3 ;
        RECT 896.000 754.840 900.000 755.440 ;
    END
  END s_axi_wstrb[5]
  PIN s_axi_wstrb[6]
    DIRECTION INPUT ;
    USE SIGNAL ;
    ANTENNAGATEAREA 0.126000 ;
    PORT
      LAYER met3 ;
        RECT 0.000 170.040 4.000 170.640 ;
    END
  END s_axi_wstrb[6]
  PIN s_axi_wstrb[7]
    DIRECTION INPUT ;
    USE SIGNAL ;
    ANTENNAGATEAREA 0.126000 ;
    PORT
      LAYER met3 ;
        RECT 0.000 166.640 4.000 167.240 ;
    END
  END s_axi_wstrb[7]
  PIN s_axi_wstrb[8]
    DIRECTION INPUT ;
    USE SIGNAL ;
    ANTENNAGATEAREA 0.126000 ;
    PORT
      LAYER met3 ;
        RECT 0.000 190.440 4.000 191.040 ;
    END
  END s_axi_wstrb[8]
  PIN s_axi_wstrb[9]
    DIRECTION INPUT ;
    USE SIGNAL ;
    ANTENNAGATEAREA 0.126000 ;
    PORT
      LAYER met3 ;
        RECT 0.000 200.640 4.000 201.240 ;
    END
  END s_axi_wstrb[9]
  PIN s_axi_wvalid[0]
    DIRECTION INPUT ;
    USE SIGNAL ;
    ANTENNAGATEAREA 0.213000 ;
    PORT
      LAYER met3 ;
        RECT 0.000 156.440 4.000 157.040 ;
    END
  END s_axi_wvalid[0]
  PIN s_axi_wvalid[1]
    DIRECTION INPUT ;
    USE SIGNAL ;
    ANTENNAGATEAREA 0.213000 ;
    PORT
      LAYER met3 ;
        RECT 0.000 197.240 4.000 197.840 ;
    END
  END s_axi_wvalid[1]
  PIN s_axi_wvalid[2]
    DIRECTION INPUT ;
    USE SIGNAL ;
    ANTENNAGATEAREA 0.495000 ;
    PORT
      LAYER met3 ;
        RECT 896.000 680.040 900.000 680.640 ;
    END
  END s_axi_wvalid[2]
  PIN s_axi_wvalid[3]
    DIRECTION INPUT ;
    USE SIGNAL ;
    ANTENNAGATEAREA 0.213000 ;
    PORT
      LAYER met3 ;
        RECT 0.000 187.040 4.000 187.640 ;
    END
  END s_axi_wvalid[3]
  OBS
      LAYER li1 ;
        RECT 5.520 10.795 894.240 886.805 ;
      LAYER met1 ;
        RECT 0.070 4.800 899.230 894.500 ;
      LAYER met2 ;
        RECT 0.650 895.720 3.030 898.125 ;
        RECT 3.870 895.720 6.250 898.125 ;
        RECT 7.090 895.720 9.470 898.125 ;
        RECT 10.310 895.720 12.690 898.125 ;
        RECT 13.530 895.720 15.910 898.125 ;
        RECT 16.750 895.720 19.130 898.125 ;
        RECT 19.970 895.720 22.350 898.125 ;
        RECT 23.190 895.720 25.570 898.125 ;
        RECT 26.410 895.720 28.790 898.125 ;
        RECT 29.630 895.720 32.010 898.125 ;
        RECT 32.850 895.720 35.230 898.125 ;
        RECT 36.070 895.720 38.450 898.125 ;
        RECT 39.290 895.720 41.670 898.125 ;
        RECT 42.510 895.720 44.890 898.125 ;
        RECT 45.730 895.720 48.110 898.125 ;
        RECT 48.950 895.720 51.330 898.125 ;
        RECT 52.170 895.720 54.550 898.125 ;
        RECT 55.390 895.720 57.770 898.125 ;
        RECT 58.610 895.720 60.990 898.125 ;
        RECT 61.830 895.720 64.210 898.125 ;
        RECT 65.050 895.720 67.430 898.125 ;
        RECT 68.270 895.720 70.650 898.125 ;
        RECT 71.490 895.720 73.870 898.125 ;
        RECT 74.710 895.720 77.090 898.125 ;
        RECT 77.930 895.720 80.310 898.125 ;
        RECT 81.150 895.720 83.530 898.125 ;
        RECT 84.370 895.720 86.750 898.125 ;
        RECT 87.590 895.720 89.970 898.125 ;
        RECT 90.810 895.720 93.190 898.125 ;
        RECT 94.030 895.720 96.410 898.125 ;
        RECT 97.250 895.720 99.630 898.125 ;
        RECT 100.470 895.720 102.850 898.125 ;
        RECT 103.690 895.720 106.070 898.125 ;
        RECT 106.910 895.720 109.290 898.125 ;
        RECT 110.130 895.720 112.510 898.125 ;
        RECT 113.350 895.720 115.730 898.125 ;
        RECT 116.570 895.720 118.950 898.125 ;
        RECT 119.790 895.720 122.170 898.125 ;
        RECT 123.010 895.720 125.390 898.125 ;
        RECT 126.230 895.720 128.610 898.125 ;
        RECT 129.450 895.720 131.830 898.125 ;
        RECT 132.670 895.720 135.050 898.125 ;
        RECT 135.890 895.720 138.270 898.125 ;
        RECT 139.110 895.720 141.490 898.125 ;
        RECT 142.330 895.720 144.710 898.125 ;
        RECT 145.550 895.720 147.930 898.125 ;
        RECT 148.770 895.720 151.150 898.125 ;
        RECT 151.990 895.720 154.370 898.125 ;
        RECT 155.210 895.720 157.590 898.125 ;
        RECT 158.430 895.720 160.810 898.125 ;
        RECT 161.650 895.720 164.030 898.125 ;
        RECT 164.870 895.720 167.250 898.125 ;
        RECT 168.090 895.720 170.470 898.125 ;
        RECT 171.310 895.720 173.690 898.125 ;
        RECT 174.530 895.720 176.910 898.125 ;
        RECT 177.750 895.720 180.130 898.125 ;
        RECT 180.970 895.720 183.350 898.125 ;
        RECT 184.190 895.720 186.570 898.125 ;
        RECT 187.410 895.720 189.790 898.125 ;
        RECT 190.630 895.720 193.010 898.125 ;
        RECT 193.850 895.720 196.230 898.125 ;
        RECT 197.070 895.720 199.450 898.125 ;
        RECT 200.290 895.720 202.670 898.125 ;
        RECT 203.510 895.720 205.890 898.125 ;
        RECT 206.730 895.720 209.110 898.125 ;
        RECT 209.950 895.720 212.330 898.125 ;
        RECT 213.170 895.720 215.550 898.125 ;
        RECT 216.390 895.720 218.770 898.125 ;
        RECT 219.610 895.720 221.990 898.125 ;
        RECT 222.830 895.720 225.210 898.125 ;
        RECT 226.050 895.720 228.430 898.125 ;
        RECT 229.270 895.720 231.650 898.125 ;
        RECT 232.490 895.720 234.870 898.125 ;
        RECT 235.710 895.720 238.090 898.125 ;
        RECT 238.930 895.720 241.310 898.125 ;
        RECT 242.150 895.720 244.530 898.125 ;
        RECT 245.370 895.720 247.750 898.125 ;
        RECT 248.590 895.720 250.970 898.125 ;
        RECT 251.810 895.720 254.190 898.125 ;
        RECT 255.030 895.720 257.410 898.125 ;
        RECT 258.250 895.720 260.630 898.125 ;
        RECT 261.470 895.720 263.850 898.125 ;
        RECT 264.690 895.720 267.070 898.125 ;
        RECT 267.910 895.720 270.290 898.125 ;
        RECT 271.130 895.720 273.510 898.125 ;
        RECT 274.350 895.720 276.730 898.125 ;
        RECT 277.570 895.720 279.950 898.125 ;
        RECT 280.790 895.720 283.170 898.125 ;
        RECT 284.010 895.720 286.390 898.125 ;
        RECT 287.230 895.720 289.610 898.125 ;
        RECT 290.450 895.720 292.830 898.125 ;
        RECT 293.670 895.720 296.050 898.125 ;
        RECT 296.890 895.720 299.270 898.125 ;
        RECT 300.110 895.720 302.490 898.125 ;
        RECT 303.330 895.720 305.710 898.125 ;
        RECT 306.550 895.720 308.930 898.125 ;
        RECT 309.770 895.720 312.150 898.125 ;
        RECT 312.990 895.720 315.370 898.125 ;
        RECT 316.210 895.720 318.590 898.125 ;
        RECT 319.430 895.720 321.810 898.125 ;
        RECT 322.650 895.720 325.030 898.125 ;
        RECT 325.870 895.720 328.250 898.125 ;
        RECT 329.090 895.720 331.470 898.125 ;
        RECT 332.310 895.720 334.690 898.125 ;
        RECT 335.530 895.720 337.910 898.125 ;
        RECT 338.750 895.720 341.130 898.125 ;
        RECT 341.970 895.720 344.350 898.125 ;
        RECT 345.190 895.720 347.570 898.125 ;
        RECT 348.410 895.720 350.790 898.125 ;
        RECT 351.630 895.720 354.010 898.125 ;
        RECT 354.850 895.720 357.230 898.125 ;
        RECT 358.070 895.720 360.450 898.125 ;
        RECT 361.290 895.720 363.670 898.125 ;
        RECT 364.510 895.720 366.890 898.125 ;
        RECT 367.730 895.720 370.110 898.125 ;
        RECT 370.950 895.720 373.330 898.125 ;
        RECT 374.170 895.720 376.550 898.125 ;
        RECT 377.390 895.720 379.770 898.125 ;
        RECT 380.610 895.720 382.990 898.125 ;
        RECT 383.830 895.720 386.210 898.125 ;
        RECT 387.050 895.720 389.430 898.125 ;
        RECT 390.270 895.720 392.650 898.125 ;
        RECT 393.490 895.720 395.870 898.125 ;
        RECT 396.710 895.720 399.090 898.125 ;
        RECT 399.930 895.720 402.310 898.125 ;
        RECT 403.150 895.720 405.530 898.125 ;
        RECT 406.370 895.720 408.750 898.125 ;
        RECT 409.590 895.720 411.970 898.125 ;
        RECT 412.810 895.720 415.190 898.125 ;
        RECT 416.030 895.720 418.410 898.125 ;
        RECT 419.250 895.720 421.630 898.125 ;
        RECT 422.470 895.720 424.850 898.125 ;
        RECT 425.690 895.720 428.070 898.125 ;
        RECT 428.910 895.720 431.290 898.125 ;
        RECT 432.130 895.720 434.510 898.125 ;
        RECT 435.350 895.720 437.730 898.125 ;
        RECT 438.570 895.720 440.950 898.125 ;
        RECT 441.790 895.720 444.170 898.125 ;
        RECT 445.010 895.720 447.390 898.125 ;
        RECT 448.230 895.720 450.610 898.125 ;
        RECT 451.450 895.720 453.830 898.125 ;
        RECT 454.670 895.720 457.050 898.125 ;
        RECT 457.890 895.720 460.270 898.125 ;
        RECT 461.110 895.720 463.490 898.125 ;
        RECT 464.330 895.720 466.710 898.125 ;
        RECT 467.550 895.720 469.930 898.125 ;
        RECT 470.770 895.720 473.150 898.125 ;
        RECT 473.990 895.720 476.370 898.125 ;
        RECT 477.210 895.720 479.590 898.125 ;
        RECT 480.430 895.720 482.810 898.125 ;
        RECT 483.650 895.720 486.030 898.125 ;
        RECT 486.870 895.720 489.250 898.125 ;
        RECT 490.090 895.720 492.470 898.125 ;
        RECT 493.310 895.720 495.690 898.125 ;
        RECT 496.530 895.720 498.910 898.125 ;
        RECT 499.750 895.720 502.130 898.125 ;
        RECT 502.970 895.720 505.350 898.125 ;
        RECT 506.190 895.720 508.570 898.125 ;
        RECT 509.410 895.720 511.790 898.125 ;
        RECT 512.630 895.720 515.010 898.125 ;
        RECT 515.850 895.720 518.230 898.125 ;
        RECT 519.070 895.720 521.450 898.125 ;
        RECT 522.290 895.720 524.670 898.125 ;
        RECT 525.510 895.720 527.890 898.125 ;
        RECT 528.730 895.720 531.110 898.125 ;
        RECT 531.950 895.720 534.330 898.125 ;
        RECT 535.170 895.720 537.550 898.125 ;
        RECT 538.390 895.720 540.770 898.125 ;
        RECT 541.610 895.720 543.990 898.125 ;
        RECT 544.830 895.720 547.210 898.125 ;
        RECT 548.050 895.720 550.430 898.125 ;
        RECT 551.270 895.720 553.650 898.125 ;
        RECT 554.490 895.720 556.870 898.125 ;
        RECT 557.710 895.720 560.090 898.125 ;
        RECT 560.930 895.720 563.310 898.125 ;
        RECT 564.150 895.720 566.530 898.125 ;
        RECT 567.370 895.720 569.750 898.125 ;
        RECT 570.590 895.720 572.970 898.125 ;
        RECT 573.810 895.720 576.190 898.125 ;
        RECT 577.030 895.720 579.410 898.125 ;
        RECT 580.250 895.720 582.630 898.125 ;
        RECT 583.470 895.720 585.850 898.125 ;
        RECT 586.690 895.720 589.070 898.125 ;
        RECT 589.910 895.720 592.290 898.125 ;
        RECT 593.130 895.720 595.510 898.125 ;
        RECT 596.350 895.720 598.730 898.125 ;
        RECT 599.570 895.720 601.950 898.125 ;
        RECT 602.790 895.720 605.170 898.125 ;
        RECT 606.010 895.720 608.390 898.125 ;
        RECT 609.230 895.720 611.610 898.125 ;
        RECT 612.450 895.720 614.830 898.125 ;
        RECT 615.670 895.720 618.050 898.125 ;
        RECT 618.890 895.720 621.270 898.125 ;
        RECT 622.110 895.720 624.490 898.125 ;
        RECT 625.330 895.720 627.710 898.125 ;
        RECT 628.550 895.720 630.930 898.125 ;
        RECT 631.770 895.720 634.150 898.125 ;
        RECT 634.990 895.720 637.370 898.125 ;
        RECT 638.210 895.720 640.590 898.125 ;
        RECT 641.430 895.720 643.810 898.125 ;
        RECT 644.650 895.720 647.030 898.125 ;
        RECT 647.870 895.720 650.250 898.125 ;
        RECT 651.090 895.720 653.470 898.125 ;
        RECT 654.310 895.720 656.690 898.125 ;
        RECT 657.530 895.720 659.910 898.125 ;
        RECT 660.750 895.720 663.130 898.125 ;
        RECT 663.970 895.720 666.350 898.125 ;
        RECT 667.190 895.720 669.570 898.125 ;
        RECT 670.410 895.720 672.790 898.125 ;
        RECT 673.630 895.720 676.010 898.125 ;
        RECT 676.850 895.720 679.230 898.125 ;
        RECT 680.070 895.720 682.450 898.125 ;
        RECT 683.290 895.720 685.670 898.125 ;
        RECT 686.510 895.720 688.890 898.125 ;
        RECT 689.730 895.720 692.110 898.125 ;
        RECT 692.950 895.720 695.330 898.125 ;
        RECT 696.170 895.720 698.550 898.125 ;
        RECT 699.390 895.720 701.770 898.125 ;
        RECT 702.610 895.720 704.990 898.125 ;
        RECT 705.830 895.720 708.210 898.125 ;
        RECT 709.050 895.720 711.430 898.125 ;
        RECT 712.270 895.720 714.650 898.125 ;
        RECT 715.490 895.720 717.870 898.125 ;
        RECT 718.710 895.720 721.090 898.125 ;
        RECT 721.930 895.720 724.310 898.125 ;
        RECT 725.150 895.720 727.530 898.125 ;
        RECT 728.370 895.720 730.750 898.125 ;
        RECT 731.590 895.720 733.970 898.125 ;
        RECT 734.810 895.720 737.190 898.125 ;
        RECT 738.030 895.720 740.410 898.125 ;
        RECT 741.250 895.720 743.630 898.125 ;
        RECT 744.470 895.720 746.850 898.125 ;
        RECT 747.690 895.720 750.070 898.125 ;
        RECT 750.910 895.720 753.290 898.125 ;
        RECT 754.130 895.720 756.510 898.125 ;
        RECT 757.350 895.720 759.730 898.125 ;
        RECT 760.570 895.720 762.950 898.125 ;
        RECT 763.790 895.720 766.170 898.125 ;
        RECT 767.010 895.720 769.390 898.125 ;
        RECT 770.230 895.720 772.610 898.125 ;
        RECT 773.450 895.720 775.830 898.125 ;
        RECT 776.670 895.720 779.050 898.125 ;
        RECT 779.890 895.720 782.270 898.125 ;
        RECT 783.110 895.720 785.490 898.125 ;
        RECT 786.330 895.720 788.710 898.125 ;
        RECT 789.550 895.720 791.930 898.125 ;
        RECT 792.770 895.720 795.150 898.125 ;
        RECT 795.990 895.720 798.370 898.125 ;
        RECT 799.210 895.720 801.590 898.125 ;
        RECT 802.430 895.720 804.810 898.125 ;
        RECT 805.650 895.720 808.030 898.125 ;
        RECT 808.870 895.720 811.250 898.125 ;
        RECT 812.090 895.720 814.470 898.125 ;
        RECT 815.310 895.720 817.690 898.125 ;
        RECT 818.530 895.720 820.910 898.125 ;
        RECT 821.750 895.720 824.130 898.125 ;
        RECT 824.970 895.720 827.350 898.125 ;
        RECT 828.190 895.720 830.570 898.125 ;
        RECT 831.410 895.720 833.790 898.125 ;
        RECT 834.630 895.720 837.010 898.125 ;
        RECT 837.850 895.720 840.230 898.125 ;
        RECT 841.070 895.720 843.450 898.125 ;
        RECT 844.290 895.720 846.670 898.125 ;
        RECT 847.510 895.720 849.890 898.125 ;
        RECT 850.730 895.720 853.110 898.125 ;
        RECT 853.950 895.720 856.330 898.125 ;
        RECT 857.170 895.720 859.550 898.125 ;
        RECT 860.390 895.720 862.770 898.125 ;
        RECT 863.610 895.720 865.990 898.125 ;
        RECT 866.830 895.720 869.210 898.125 ;
        RECT 870.050 895.720 872.430 898.125 ;
        RECT 873.270 895.720 875.650 898.125 ;
        RECT 876.490 895.720 878.870 898.125 ;
        RECT 879.710 895.720 882.090 898.125 ;
        RECT 882.930 895.720 885.310 898.125 ;
        RECT 886.150 895.720 888.530 898.125 ;
        RECT 889.370 895.720 891.750 898.125 ;
        RECT 892.590 895.720 894.970 898.125 ;
        RECT 895.810 895.720 898.190 898.125 ;
        RECT 899.030 895.720 899.200 898.125 ;
        RECT 0.100 4.280 899.200 895.720 ;
        RECT 0.650 0.155 3.030 4.280 ;
        RECT 3.870 0.155 6.250 4.280 ;
        RECT 7.090 0.155 9.470 4.280 ;
        RECT 10.310 0.155 12.690 4.280 ;
        RECT 13.530 0.155 15.910 4.280 ;
        RECT 16.750 0.155 19.130 4.280 ;
        RECT 19.970 0.155 22.350 4.280 ;
        RECT 23.190 0.155 25.570 4.280 ;
        RECT 26.410 0.155 28.790 4.280 ;
        RECT 29.630 0.155 32.010 4.280 ;
        RECT 32.850 0.155 35.230 4.280 ;
        RECT 36.070 0.155 38.450 4.280 ;
        RECT 39.290 0.155 41.670 4.280 ;
        RECT 42.510 0.155 44.890 4.280 ;
        RECT 45.730 0.155 48.110 4.280 ;
        RECT 48.950 0.155 51.330 4.280 ;
        RECT 52.170 0.155 54.550 4.280 ;
        RECT 55.390 0.155 57.770 4.280 ;
        RECT 58.610 0.155 60.990 4.280 ;
        RECT 61.830 0.155 64.210 4.280 ;
        RECT 65.050 0.155 67.430 4.280 ;
        RECT 68.270 0.155 70.650 4.280 ;
        RECT 71.490 0.155 73.870 4.280 ;
        RECT 74.710 0.155 77.090 4.280 ;
        RECT 77.930 0.155 80.310 4.280 ;
        RECT 81.150 0.155 83.530 4.280 ;
        RECT 84.370 0.155 86.750 4.280 ;
        RECT 87.590 0.155 89.970 4.280 ;
        RECT 90.810 0.155 93.190 4.280 ;
        RECT 94.030 0.155 96.410 4.280 ;
        RECT 97.250 0.155 99.630 4.280 ;
        RECT 100.470 0.155 102.850 4.280 ;
        RECT 103.690 0.155 106.070 4.280 ;
        RECT 106.910 0.155 109.290 4.280 ;
        RECT 110.130 0.155 112.510 4.280 ;
        RECT 113.350 0.155 115.730 4.280 ;
        RECT 116.570 0.155 118.950 4.280 ;
        RECT 119.790 0.155 122.170 4.280 ;
        RECT 123.010 0.155 125.390 4.280 ;
        RECT 126.230 0.155 128.610 4.280 ;
        RECT 129.450 0.155 131.830 4.280 ;
        RECT 132.670 0.155 135.050 4.280 ;
        RECT 135.890 0.155 138.270 4.280 ;
        RECT 139.110 0.155 141.490 4.280 ;
        RECT 142.330 0.155 144.710 4.280 ;
        RECT 145.550 0.155 147.930 4.280 ;
        RECT 148.770 0.155 151.150 4.280 ;
        RECT 151.990 0.155 154.370 4.280 ;
        RECT 155.210 0.155 157.590 4.280 ;
        RECT 158.430 0.155 160.810 4.280 ;
        RECT 161.650 0.155 164.030 4.280 ;
        RECT 164.870 0.155 167.250 4.280 ;
        RECT 168.090 0.155 170.470 4.280 ;
        RECT 171.310 0.155 173.690 4.280 ;
        RECT 174.530 0.155 176.910 4.280 ;
        RECT 177.750 0.155 180.130 4.280 ;
        RECT 180.970 0.155 183.350 4.280 ;
        RECT 184.190 0.155 186.570 4.280 ;
        RECT 187.410 0.155 189.790 4.280 ;
        RECT 190.630 0.155 193.010 4.280 ;
        RECT 193.850 0.155 196.230 4.280 ;
        RECT 197.070 0.155 199.450 4.280 ;
        RECT 200.290 0.155 202.670 4.280 ;
        RECT 203.510 0.155 205.890 4.280 ;
        RECT 206.730 0.155 209.110 4.280 ;
        RECT 209.950 0.155 212.330 4.280 ;
        RECT 213.170 0.155 215.550 4.280 ;
        RECT 216.390 0.155 218.770 4.280 ;
        RECT 219.610 0.155 221.990 4.280 ;
        RECT 222.830 0.155 225.210 4.280 ;
        RECT 226.050 0.155 228.430 4.280 ;
        RECT 229.270 0.155 231.650 4.280 ;
        RECT 232.490 0.155 234.870 4.280 ;
        RECT 235.710 0.155 238.090 4.280 ;
        RECT 238.930 0.155 241.310 4.280 ;
        RECT 242.150 0.155 244.530 4.280 ;
        RECT 245.370 0.155 247.750 4.280 ;
        RECT 248.590 0.155 250.970 4.280 ;
        RECT 251.810 0.155 254.190 4.280 ;
        RECT 255.030 0.155 257.410 4.280 ;
        RECT 258.250 0.155 260.630 4.280 ;
        RECT 261.470 0.155 263.850 4.280 ;
        RECT 264.690 0.155 267.070 4.280 ;
        RECT 267.910 0.155 270.290 4.280 ;
        RECT 271.130 0.155 273.510 4.280 ;
        RECT 274.350 0.155 276.730 4.280 ;
        RECT 277.570 0.155 279.950 4.280 ;
        RECT 280.790 0.155 283.170 4.280 ;
        RECT 284.010 0.155 286.390 4.280 ;
        RECT 287.230 0.155 289.610 4.280 ;
        RECT 290.450 0.155 292.830 4.280 ;
        RECT 293.670 0.155 296.050 4.280 ;
        RECT 296.890 0.155 299.270 4.280 ;
        RECT 300.110 0.155 302.490 4.280 ;
        RECT 303.330 0.155 305.710 4.280 ;
        RECT 306.550 0.155 308.930 4.280 ;
        RECT 309.770 0.155 312.150 4.280 ;
        RECT 312.990 0.155 315.370 4.280 ;
        RECT 316.210 0.155 318.590 4.280 ;
        RECT 319.430 0.155 321.810 4.280 ;
        RECT 322.650 0.155 325.030 4.280 ;
        RECT 325.870 0.155 328.250 4.280 ;
        RECT 329.090 0.155 331.470 4.280 ;
        RECT 332.310 0.155 334.690 4.280 ;
        RECT 335.530 0.155 337.910 4.280 ;
        RECT 338.750 0.155 341.130 4.280 ;
        RECT 341.970 0.155 344.350 4.280 ;
        RECT 345.190 0.155 347.570 4.280 ;
        RECT 348.410 0.155 350.790 4.280 ;
        RECT 351.630 0.155 354.010 4.280 ;
        RECT 354.850 0.155 357.230 4.280 ;
        RECT 358.070 0.155 360.450 4.280 ;
        RECT 361.290 0.155 363.670 4.280 ;
        RECT 364.510 0.155 366.890 4.280 ;
        RECT 367.730 0.155 370.110 4.280 ;
        RECT 370.950 0.155 373.330 4.280 ;
        RECT 374.170 0.155 376.550 4.280 ;
        RECT 377.390 0.155 379.770 4.280 ;
        RECT 380.610 0.155 382.990 4.280 ;
        RECT 383.830 0.155 386.210 4.280 ;
        RECT 387.050 0.155 389.430 4.280 ;
        RECT 390.270 0.155 392.650 4.280 ;
        RECT 393.490 0.155 395.870 4.280 ;
        RECT 396.710 0.155 399.090 4.280 ;
        RECT 399.930 0.155 402.310 4.280 ;
        RECT 403.150 0.155 405.530 4.280 ;
        RECT 406.370 0.155 408.750 4.280 ;
        RECT 409.590 0.155 411.970 4.280 ;
        RECT 412.810 0.155 415.190 4.280 ;
        RECT 416.030 0.155 418.410 4.280 ;
        RECT 419.250 0.155 421.630 4.280 ;
        RECT 422.470 0.155 424.850 4.280 ;
        RECT 425.690 0.155 428.070 4.280 ;
        RECT 428.910 0.155 431.290 4.280 ;
        RECT 432.130 0.155 434.510 4.280 ;
        RECT 435.350 0.155 437.730 4.280 ;
        RECT 438.570 0.155 440.950 4.280 ;
        RECT 441.790 0.155 444.170 4.280 ;
        RECT 445.010 0.155 447.390 4.280 ;
        RECT 448.230 0.155 450.610 4.280 ;
        RECT 451.450 0.155 453.830 4.280 ;
        RECT 454.670 0.155 457.050 4.280 ;
        RECT 457.890 0.155 460.270 4.280 ;
        RECT 461.110 0.155 463.490 4.280 ;
        RECT 464.330 0.155 466.710 4.280 ;
        RECT 467.550 0.155 469.930 4.280 ;
        RECT 470.770 0.155 473.150 4.280 ;
        RECT 473.990 0.155 476.370 4.280 ;
        RECT 477.210 0.155 479.590 4.280 ;
        RECT 480.430 0.155 482.810 4.280 ;
        RECT 483.650 0.155 486.030 4.280 ;
        RECT 486.870 0.155 489.250 4.280 ;
        RECT 490.090 0.155 492.470 4.280 ;
        RECT 493.310 0.155 495.690 4.280 ;
        RECT 496.530 0.155 498.910 4.280 ;
        RECT 499.750 0.155 502.130 4.280 ;
        RECT 502.970 0.155 505.350 4.280 ;
        RECT 506.190 0.155 508.570 4.280 ;
        RECT 509.410 0.155 511.790 4.280 ;
        RECT 512.630 0.155 515.010 4.280 ;
        RECT 515.850 0.155 518.230 4.280 ;
        RECT 519.070 0.155 521.450 4.280 ;
        RECT 522.290 0.155 524.670 4.280 ;
        RECT 525.510 0.155 527.890 4.280 ;
        RECT 528.730 0.155 531.110 4.280 ;
        RECT 531.950 0.155 534.330 4.280 ;
        RECT 535.170 0.155 537.550 4.280 ;
        RECT 538.390 0.155 540.770 4.280 ;
        RECT 541.610 0.155 543.990 4.280 ;
        RECT 544.830 0.155 547.210 4.280 ;
        RECT 548.050 0.155 550.430 4.280 ;
        RECT 551.270 0.155 553.650 4.280 ;
        RECT 554.490 0.155 556.870 4.280 ;
        RECT 557.710 0.155 560.090 4.280 ;
        RECT 560.930 0.155 563.310 4.280 ;
        RECT 564.150 0.155 566.530 4.280 ;
        RECT 567.370 0.155 569.750 4.280 ;
        RECT 570.590 0.155 572.970 4.280 ;
        RECT 573.810 0.155 576.190 4.280 ;
        RECT 577.030 0.155 579.410 4.280 ;
        RECT 580.250 0.155 582.630 4.280 ;
        RECT 583.470 0.155 585.850 4.280 ;
        RECT 586.690 0.155 589.070 4.280 ;
        RECT 589.910 0.155 592.290 4.280 ;
        RECT 593.130 0.155 595.510 4.280 ;
        RECT 596.350 0.155 598.730 4.280 ;
        RECT 599.570 0.155 601.950 4.280 ;
        RECT 602.790 0.155 605.170 4.280 ;
        RECT 606.010 0.155 608.390 4.280 ;
        RECT 609.230 0.155 611.610 4.280 ;
        RECT 612.450 0.155 614.830 4.280 ;
        RECT 615.670 0.155 618.050 4.280 ;
        RECT 618.890 0.155 621.270 4.280 ;
        RECT 622.110 0.155 624.490 4.280 ;
        RECT 625.330 0.155 627.710 4.280 ;
        RECT 628.550 0.155 630.930 4.280 ;
        RECT 631.770 0.155 634.150 4.280 ;
        RECT 634.990 0.155 637.370 4.280 ;
        RECT 638.210 0.155 640.590 4.280 ;
        RECT 641.430 0.155 899.200 4.280 ;
      LAYER met3 ;
        RECT 4.400 897.240 896.000 898.105 ;
        RECT 3.750 895.240 896.000 897.240 ;
        RECT 4.400 893.840 896.000 895.240 ;
        RECT 3.750 891.840 896.000 893.840 ;
        RECT 4.400 890.440 896.000 891.840 ;
        RECT 3.750 888.440 896.000 890.440 ;
        RECT 4.400 887.040 896.000 888.440 ;
        RECT 3.750 885.040 896.000 887.040 ;
        RECT 4.400 883.640 896.000 885.040 ;
        RECT 3.750 881.640 896.000 883.640 ;
        RECT 4.400 880.240 896.000 881.640 ;
        RECT 3.750 878.240 896.000 880.240 ;
        RECT 4.400 876.840 896.000 878.240 ;
        RECT 3.750 874.840 896.000 876.840 ;
        RECT 4.400 873.440 896.000 874.840 ;
        RECT 3.750 871.440 896.000 873.440 ;
        RECT 4.400 870.040 896.000 871.440 ;
        RECT 3.750 868.040 896.000 870.040 ;
        RECT 4.400 866.640 896.000 868.040 ;
        RECT 3.750 864.640 896.000 866.640 ;
        RECT 4.400 863.240 896.000 864.640 ;
        RECT 3.750 861.240 896.000 863.240 ;
        RECT 4.400 859.840 896.000 861.240 ;
        RECT 3.750 857.840 896.000 859.840 ;
        RECT 4.400 856.440 896.000 857.840 ;
        RECT 3.750 854.440 896.000 856.440 ;
        RECT 4.400 853.040 896.000 854.440 ;
        RECT 3.750 851.040 896.000 853.040 ;
        RECT 4.400 849.640 896.000 851.040 ;
        RECT 3.750 847.640 896.000 849.640 ;
        RECT 4.400 846.240 896.000 847.640 ;
        RECT 3.750 844.240 896.000 846.240 ;
        RECT 4.400 842.840 896.000 844.240 ;
        RECT 3.750 840.840 896.000 842.840 ;
        RECT 4.400 839.440 896.000 840.840 ;
        RECT 3.750 837.440 896.000 839.440 ;
        RECT 4.400 836.040 895.600 837.440 ;
        RECT 3.750 834.040 896.000 836.040 ;
        RECT 4.400 832.640 895.600 834.040 ;
        RECT 3.750 830.640 896.000 832.640 ;
        RECT 4.400 829.240 895.600 830.640 ;
        RECT 3.750 827.240 896.000 829.240 ;
        RECT 4.400 825.840 895.600 827.240 ;
        RECT 3.750 823.840 896.000 825.840 ;
        RECT 4.400 822.440 895.600 823.840 ;
        RECT 3.750 820.440 896.000 822.440 ;
        RECT 4.400 819.040 895.600 820.440 ;
        RECT 3.750 817.040 896.000 819.040 ;
        RECT 4.400 815.640 895.600 817.040 ;
        RECT 3.750 813.640 896.000 815.640 ;
        RECT 4.400 812.240 895.600 813.640 ;
        RECT 3.750 810.240 896.000 812.240 ;
        RECT 4.400 808.840 895.600 810.240 ;
        RECT 3.750 806.840 896.000 808.840 ;
        RECT 4.400 805.440 895.600 806.840 ;
        RECT 3.750 803.440 896.000 805.440 ;
        RECT 4.400 802.040 895.600 803.440 ;
        RECT 3.750 800.040 896.000 802.040 ;
        RECT 4.400 798.640 895.600 800.040 ;
        RECT 3.750 796.640 896.000 798.640 ;
        RECT 4.400 795.240 895.600 796.640 ;
        RECT 3.750 793.240 896.000 795.240 ;
        RECT 4.400 791.840 895.600 793.240 ;
        RECT 3.750 789.840 896.000 791.840 ;
        RECT 4.400 788.440 895.600 789.840 ;
        RECT 3.750 786.440 896.000 788.440 ;
        RECT 4.400 785.040 895.600 786.440 ;
        RECT 3.750 783.040 896.000 785.040 ;
        RECT 4.400 781.640 895.600 783.040 ;
        RECT 3.750 779.640 896.000 781.640 ;
        RECT 4.400 778.240 895.600 779.640 ;
        RECT 3.750 776.240 896.000 778.240 ;
        RECT 4.400 774.840 895.600 776.240 ;
        RECT 3.750 772.840 896.000 774.840 ;
        RECT 4.400 771.440 895.600 772.840 ;
        RECT 3.750 769.440 896.000 771.440 ;
        RECT 4.400 768.040 895.600 769.440 ;
        RECT 3.750 766.040 896.000 768.040 ;
        RECT 4.400 764.640 895.600 766.040 ;
        RECT 3.750 762.640 896.000 764.640 ;
        RECT 4.400 761.240 895.600 762.640 ;
        RECT 3.750 759.240 896.000 761.240 ;
        RECT 4.400 757.840 895.600 759.240 ;
        RECT 3.750 755.840 896.000 757.840 ;
        RECT 4.400 754.440 895.600 755.840 ;
        RECT 3.750 752.440 896.000 754.440 ;
        RECT 4.400 751.040 895.600 752.440 ;
        RECT 3.750 749.040 896.000 751.040 ;
        RECT 4.400 747.640 895.600 749.040 ;
        RECT 3.750 745.640 896.000 747.640 ;
        RECT 4.400 744.240 895.600 745.640 ;
        RECT 3.750 742.240 896.000 744.240 ;
        RECT 4.400 740.840 895.600 742.240 ;
        RECT 3.750 738.840 896.000 740.840 ;
        RECT 4.400 737.440 895.600 738.840 ;
        RECT 3.750 735.440 896.000 737.440 ;
        RECT 4.400 734.040 895.600 735.440 ;
        RECT 3.750 732.040 896.000 734.040 ;
        RECT 4.400 730.640 895.600 732.040 ;
        RECT 3.750 728.640 896.000 730.640 ;
        RECT 4.400 727.240 895.600 728.640 ;
        RECT 3.750 725.240 896.000 727.240 ;
        RECT 4.400 723.840 895.600 725.240 ;
        RECT 3.750 721.840 896.000 723.840 ;
        RECT 4.400 720.440 895.600 721.840 ;
        RECT 3.750 718.440 896.000 720.440 ;
        RECT 4.400 717.040 895.600 718.440 ;
        RECT 3.750 715.040 896.000 717.040 ;
        RECT 4.400 713.640 895.600 715.040 ;
        RECT 3.750 711.640 896.000 713.640 ;
        RECT 4.400 710.240 895.600 711.640 ;
        RECT 3.750 708.240 896.000 710.240 ;
        RECT 4.400 706.840 895.600 708.240 ;
        RECT 3.750 704.840 896.000 706.840 ;
        RECT 4.400 703.440 895.600 704.840 ;
        RECT 3.750 701.440 896.000 703.440 ;
        RECT 4.400 700.040 895.600 701.440 ;
        RECT 3.750 698.040 896.000 700.040 ;
        RECT 4.400 696.640 895.600 698.040 ;
        RECT 3.750 694.640 896.000 696.640 ;
        RECT 4.400 693.240 895.600 694.640 ;
        RECT 3.750 691.240 896.000 693.240 ;
        RECT 4.400 689.840 895.600 691.240 ;
        RECT 3.750 687.840 896.000 689.840 ;
        RECT 4.400 686.440 895.600 687.840 ;
        RECT 3.750 684.440 896.000 686.440 ;
        RECT 4.400 683.040 895.600 684.440 ;
        RECT 3.750 681.040 896.000 683.040 ;
        RECT 4.400 679.640 895.600 681.040 ;
        RECT 3.750 677.640 896.000 679.640 ;
        RECT 4.400 676.240 895.600 677.640 ;
        RECT 3.750 674.240 896.000 676.240 ;
        RECT 4.400 672.840 895.600 674.240 ;
        RECT 3.750 670.840 896.000 672.840 ;
        RECT 4.400 669.440 895.600 670.840 ;
        RECT 3.750 667.440 896.000 669.440 ;
        RECT 4.400 666.040 895.600 667.440 ;
        RECT 3.750 664.040 896.000 666.040 ;
        RECT 4.400 662.640 895.600 664.040 ;
        RECT 3.750 660.640 896.000 662.640 ;
        RECT 4.400 659.240 895.600 660.640 ;
        RECT 3.750 657.240 896.000 659.240 ;
        RECT 4.400 655.840 895.600 657.240 ;
        RECT 3.750 653.840 896.000 655.840 ;
        RECT 4.400 652.440 895.600 653.840 ;
        RECT 3.750 650.440 896.000 652.440 ;
        RECT 4.400 649.040 895.600 650.440 ;
        RECT 3.750 647.040 896.000 649.040 ;
        RECT 4.400 645.640 895.600 647.040 ;
        RECT 3.750 643.640 896.000 645.640 ;
        RECT 4.400 642.240 895.600 643.640 ;
        RECT 3.750 640.240 896.000 642.240 ;
        RECT 4.400 638.840 895.600 640.240 ;
        RECT 3.750 636.840 896.000 638.840 ;
        RECT 4.400 635.440 895.600 636.840 ;
        RECT 3.750 633.440 896.000 635.440 ;
        RECT 4.400 632.040 895.600 633.440 ;
        RECT 3.750 630.040 896.000 632.040 ;
        RECT 4.400 628.640 895.600 630.040 ;
        RECT 3.750 626.640 896.000 628.640 ;
        RECT 4.400 625.240 895.600 626.640 ;
        RECT 3.750 623.240 896.000 625.240 ;
        RECT 4.400 621.840 895.600 623.240 ;
        RECT 3.750 619.840 896.000 621.840 ;
        RECT 4.400 618.440 895.600 619.840 ;
        RECT 3.750 616.440 896.000 618.440 ;
        RECT 4.400 615.040 895.600 616.440 ;
        RECT 3.750 613.040 896.000 615.040 ;
        RECT 4.400 611.640 895.600 613.040 ;
        RECT 3.750 609.640 896.000 611.640 ;
        RECT 4.400 608.240 895.600 609.640 ;
        RECT 3.750 606.240 896.000 608.240 ;
        RECT 4.400 604.840 895.600 606.240 ;
        RECT 3.750 602.840 896.000 604.840 ;
        RECT 4.400 601.440 895.600 602.840 ;
        RECT 3.750 599.440 896.000 601.440 ;
        RECT 4.400 598.040 895.600 599.440 ;
        RECT 3.750 596.040 896.000 598.040 ;
        RECT 4.400 594.640 895.600 596.040 ;
        RECT 3.750 592.640 896.000 594.640 ;
        RECT 4.400 591.240 895.600 592.640 ;
        RECT 3.750 589.240 896.000 591.240 ;
        RECT 4.400 587.840 895.600 589.240 ;
        RECT 3.750 585.840 896.000 587.840 ;
        RECT 4.400 584.440 895.600 585.840 ;
        RECT 3.750 582.440 896.000 584.440 ;
        RECT 4.400 581.040 895.600 582.440 ;
        RECT 3.750 579.040 896.000 581.040 ;
        RECT 4.400 577.640 895.600 579.040 ;
        RECT 3.750 575.640 896.000 577.640 ;
        RECT 4.400 574.240 895.600 575.640 ;
        RECT 3.750 572.240 896.000 574.240 ;
        RECT 4.400 570.840 895.600 572.240 ;
        RECT 3.750 568.840 896.000 570.840 ;
        RECT 4.400 567.440 895.600 568.840 ;
        RECT 3.750 565.440 896.000 567.440 ;
        RECT 4.400 564.040 895.600 565.440 ;
        RECT 3.750 562.040 896.000 564.040 ;
        RECT 4.400 560.640 895.600 562.040 ;
        RECT 3.750 558.640 896.000 560.640 ;
        RECT 4.400 557.240 895.600 558.640 ;
        RECT 3.750 555.240 896.000 557.240 ;
        RECT 4.400 553.840 895.600 555.240 ;
        RECT 3.750 551.840 896.000 553.840 ;
        RECT 4.400 550.440 895.600 551.840 ;
        RECT 3.750 548.440 896.000 550.440 ;
        RECT 4.400 547.040 895.600 548.440 ;
        RECT 3.750 545.040 896.000 547.040 ;
        RECT 4.400 543.640 895.600 545.040 ;
        RECT 3.750 541.640 896.000 543.640 ;
        RECT 4.400 540.240 895.600 541.640 ;
        RECT 3.750 538.240 896.000 540.240 ;
        RECT 4.400 536.840 895.600 538.240 ;
        RECT 3.750 534.840 896.000 536.840 ;
        RECT 4.400 533.440 895.600 534.840 ;
        RECT 3.750 531.440 896.000 533.440 ;
        RECT 4.400 530.040 895.600 531.440 ;
        RECT 3.750 528.040 896.000 530.040 ;
        RECT 4.400 526.640 895.600 528.040 ;
        RECT 3.750 524.640 896.000 526.640 ;
        RECT 4.400 523.240 895.600 524.640 ;
        RECT 3.750 521.240 896.000 523.240 ;
        RECT 4.400 519.840 895.600 521.240 ;
        RECT 3.750 517.840 896.000 519.840 ;
        RECT 4.400 516.440 895.600 517.840 ;
        RECT 3.750 514.440 896.000 516.440 ;
        RECT 4.400 513.040 895.600 514.440 ;
        RECT 3.750 511.040 896.000 513.040 ;
        RECT 4.400 509.640 895.600 511.040 ;
        RECT 3.750 507.640 896.000 509.640 ;
        RECT 4.400 506.240 895.600 507.640 ;
        RECT 3.750 504.240 896.000 506.240 ;
        RECT 4.400 502.840 895.600 504.240 ;
        RECT 3.750 500.840 896.000 502.840 ;
        RECT 4.400 499.440 895.600 500.840 ;
        RECT 3.750 497.440 896.000 499.440 ;
        RECT 4.400 496.040 895.600 497.440 ;
        RECT 3.750 494.040 896.000 496.040 ;
        RECT 4.400 492.640 895.600 494.040 ;
        RECT 3.750 490.640 896.000 492.640 ;
        RECT 4.400 489.240 895.600 490.640 ;
        RECT 3.750 487.240 896.000 489.240 ;
        RECT 4.400 485.840 895.600 487.240 ;
        RECT 3.750 483.840 896.000 485.840 ;
        RECT 4.400 482.440 895.600 483.840 ;
        RECT 3.750 480.440 896.000 482.440 ;
        RECT 4.400 479.040 895.600 480.440 ;
        RECT 3.750 477.040 896.000 479.040 ;
        RECT 4.400 475.640 895.600 477.040 ;
        RECT 3.750 473.640 896.000 475.640 ;
        RECT 4.400 472.240 895.600 473.640 ;
        RECT 3.750 470.240 896.000 472.240 ;
        RECT 4.400 468.840 895.600 470.240 ;
        RECT 3.750 466.840 896.000 468.840 ;
        RECT 4.400 465.440 895.600 466.840 ;
        RECT 3.750 463.440 896.000 465.440 ;
        RECT 4.400 462.040 895.600 463.440 ;
        RECT 3.750 460.040 896.000 462.040 ;
        RECT 4.400 458.640 895.600 460.040 ;
        RECT 3.750 456.640 896.000 458.640 ;
        RECT 4.400 455.240 895.600 456.640 ;
        RECT 3.750 453.240 896.000 455.240 ;
        RECT 4.400 451.840 895.600 453.240 ;
        RECT 3.750 449.840 896.000 451.840 ;
        RECT 4.400 448.440 895.600 449.840 ;
        RECT 3.750 446.440 896.000 448.440 ;
        RECT 4.400 445.040 895.600 446.440 ;
        RECT 3.750 443.040 896.000 445.040 ;
        RECT 4.400 441.640 895.600 443.040 ;
        RECT 3.750 439.640 896.000 441.640 ;
        RECT 4.400 438.240 895.600 439.640 ;
        RECT 3.750 436.240 896.000 438.240 ;
        RECT 4.400 434.840 895.600 436.240 ;
        RECT 3.750 432.840 896.000 434.840 ;
        RECT 4.400 431.440 895.600 432.840 ;
        RECT 3.750 429.440 896.000 431.440 ;
        RECT 4.400 428.040 895.600 429.440 ;
        RECT 3.750 426.040 896.000 428.040 ;
        RECT 4.400 424.640 895.600 426.040 ;
        RECT 3.750 422.640 896.000 424.640 ;
        RECT 4.400 421.240 895.600 422.640 ;
        RECT 3.750 419.240 896.000 421.240 ;
        RECT 4.400 417.840 895.600 419.240 ;
        RECT 3.750 415.840 896.000 417.840 ;
        RECT 4.400 414.440 895.600 415.840 ;
        RECT 3.750 412.440 896.000 414.440 ;
        RECT 4.400 411.040 895.600 412.440 ;
        RECT 3.750 409.040 896.000 411.040 ;
        RECT 4.400 407.640 895.600 409.040 ;
        RECT 3.750 405.640 896.000 407.640 ;
        RECT 4.400 404.240 895.600 405.640 ;
        RECT 3.750 402.240 896.000 404.240 ;
        RECT 4.400 400.840 895.600 402.240 ;
        RECT 3.750 398.840 896.000 400.840 ;
        RECT 4.400 397.440 895.600 398.840 ;
        RECT 3.750 395.440 896.000 397.440 ;
        RECT 4.400 394.040 895.600 395.440 ;
        RECT 3.750 392.040 896.000 394.040 ;
        RECT 4.400 390.640 895.600 392.040 ;
        RECT 3.750 388.640 896.000 390.640 ;
        RECT 4.400 387.240 895.600 388.640 ;
        RECT 3.750 385.240 896.000 387.240 ;
        RECT 4.400 383.840 895.600 385.240 ;
        RECT 3.750 381.840 896.000 383.840 ;
        RECT 4.400 380.440 895.600 381.840 ;
        RECT 3.750 378.440 896.000 380.440 ;
        RECT 4.400 377.040 895.600 378.440 ;
        RECT 3.750 375.040 896.000 377.040 ;
        RECT 4.400 373.640 895.600 375.040 ;
        RECT 3.750 371.640 896.000 373.640 ;
        RECT 4.400 370.240 895.600 371.640 ;
        RECT 3.750 368.240 896.000 370.240 ;
        RECT 4.400 366.840 895.600 368.240 ;
        RECT 3.750 364.840 896.000 366.840 ;
        RECT 4.400 363.440 895.600 364.840 ;
        RECT 3.750 361.440 896.000 363.440 ;
        RECT 4.400 360.040 895.600 361.440 ;
        RECT 3.750 358.040 896.000 360.040 ;
        RECT 4.400 356.640 895.600 358.040 ;
        RECT 3.750 354.640 896.000 356.640 ;
        RECT 4.400 353.240 895.600 354.640 ;
        RECT 3.750 351.240 896.000 353.240 ;
        RECT 4.400 349.840 895.600 351.240 ;
        RECT 3.750 347.840 896.000 349.840 ;
        RECT 4.400 346.440 895.600 347.840 ;
        RECT 3.750 344.440 896.000 346.440 ;
        RECT 4.400 343.040 895.600 344.440 ;
        RECT 3.750 341.040 896.000 343.040 ;
        RECT 4.400 339.640 895.600 341.040 ;
        RECT 3.750 337.640 896.000 339.640 ;
        RECT 4.400 336.240 895.600 337.640 ;
        RECT 3.750 334.240 896.000 336.240 ;
        RECT 4.400 332.840 895.600 334.240 ;
        RECT 3.750 330.840 896.000 332.840 ;
        RECT 4.400 329.440 895.600 330.840 ;
        RECT 3.750 327.440 896.000 329.440 ;
        RECT 4.400 326.040 895.600 327.440 ;
        RECT 3.750 324.040 896.000 326.040 ;
        RECT 4.400 322.640 895.600 324.040 ;
        RECT 3.750 320.640 896.000 322.640 ;
        RECT 4.400 319.240 895.600 320.640 ;
        RECT 3.750 317.240 896.000 319.240 ;
        RECT 4.400 315.840 895.600 317.240 ;
        RECT 3.750 313.840 896.000 315.840 ;
        RECT 4.400 312.440 895.600 313.840 ;
        RECT 3.750 310.440 896.000 312.440 ;
        RECT 4.400 309.040 895.600 310.440 ;
        RECT 3.750 307.040 896.000 309.040 ;
        RECT 4.400 305.640 895.600 307.040 ;
        RECT 3.750 303.640 896.000 305.640 ;
        RECT 4.400 302.240 895.600 303.640 ;
        RECT 3.750 300.240 896.000 302.240 ;
        RECT 4.400 298.840 895.600 300.240 ;
        RECT 3.750 296.840 896.000 298.840 ;
        RECT 4.400 295.440 895.600 296.840 ;
        RECT 3.750 293.440 896.000 295.440 ;
        RECT 4.400 292.040 895.600 293.440 ;
        RECT 3.750 290.040 896.000 292.040 ;
        RECT 4.400 288.640 895.600 290.040 ;
        RECT 3.750 286.640 896.000 288.640 ;
        RECT 4.400 285.240 895.600 286.640 ;
        RECT 3.750 283.240 896.000 285.240 ;
        RECT 4.400 281.840 895.600 283.240 ;
        RECT 3.750 279.840 896.000 281.840 ;
        RECT 4.400 278.440 895.600 279.840 ;
        RECT 3.750 276.440 896.000 278.440 ;
        RECT 4.400 275.040 895.600 276.440 ;
        RECT 3.750 273.040 896.000 275.040 ;
        RECT 4.400 271.640 895.600 273.040 ;
        RECT 3.750 269.640 896.000 271.640 ;
        RECT 4.400 268.240 895.600 269.640 ;
        RECT 3.750 266.240 896.000 268.240 ;
        RECT 4.400 264.840 895.600 266.240 ;
        RECT 3.750 262.840 896.000 264.840 ;
        RECT 4.400 261.440 895.600 262.840 ;
        RECT 3.750 259.440 896.000 261.440 ;
        RECT 4.400 258.040 895.600 259.440 ;
        RECT 3.750 256.040 896.000 258.040 ;
        RECT 4.400 254.640 895.600 256.040 ;
        RECT 3.750 252.640 896.000 254.640 ;
        RECT 4.400 251.240 895.600 252.640 ;
        RECT 3.750 249.240 896.000 251.240 ;
        RECT 4.400 247.840 895.600 249.240 ;
        RECT 3.750 245.840 896.000 247.840 ;
        RECT 4.400 244.440 895.600 245.840 ;
        RECT 3.750 242.440 896.000 244.440 ;
        RECT 4.400 241.040 895.600 242.440 ;
        RECT 3.750 239.040 896.000 241.040 ;
        RECT 4.400 237.640 895.600 239.040 ;
        RECT 3.750 235.640 896.000 237.640 ;
        RECT 4.400 234.240 895.600 235.640 ;
        RECT 3.750 232.240 896.000 234.240 ;
        RECT 4.400 230.840 895.600 232.240 ;
        RECT 3.750 228.840 896.000 230.840 ;
        RECT 4.400 227.440 895.600 228.840 ;
        RECT 3.750 225.440 896.000 227.440 ;
        RECT 4.400 224.040 895.600 225.440 ;
        RECT 3.750 222.040 896.000 224.040 ;
        RECT 4.400 220.640 895.600 222.040 ;
        RECT 3.750 218.640 896.000 220.640 ;
        RECT 4.400 217.240 895.600 218.640 ;
        RECT 3.750 215.240 896.000 217.240 ;
        RECT 4.400 213.840 895.600 215.240 ;
        RECT 3.750 211.840 896.000 213.840 ;
        RECT 4.400 210.440 895.600 211.840 ;
        RECT 3.750 208.440 896.000 210.440 ;
        RECT 4.400 207.040 895.600 208.440 ;
        RECT 3.750 205.040 896.000 207.040 ;
        RECT 4.400 203.640 895.600 205.040 ;
        RECT 3.750 201.640 896.000 203.640 ;
        RECT 4.400 200.240 895.600 201.640 ;
        RECT 3.750 198.240 896.000 200.240 ;
        RECT 4.400 196.840 895.600 198.240 ;
        RECT 3.750 194.840 896.000 196.840 ;
        RECT 4.400 193.440 895.600 194.840 ;
        RECT 3.750 191.440 896.000 193.440 ;
        RECT 4.400 190.040 895.600 191.440 ;
        RECT 3.750 188.040 896.000 190.040 ;
        RECT 4.400 186.640 895.600 188.040 ;
        RECT 3.750 184.640 896.000 186.640 ;
        RECT 4.400 183.240 895.600 184.640 ;
        RECT 3.750 181.240 896.000 183.240 ;
        RECT 4.400 179.840 895.600 181.240 ;
        RECT 3.750 177.840 896.000 179.840 ;
        RECT 4.400 176.440 895.600 177.840 ;
        RECT 3.750 174.440 896.000 176.440 ;
        RECT 4.400 173.040 895.600 174.440 ;
        RECT 3.750 171.040 896.000 173.040 ;
        RECT 4.400 169.640 895.600 171.040 ;
        RECT 3.750 167.640 896.000 169.640 ;
        RECT 4.400 166.240 895.600 167.640 ;
        RECT 3.750 164.240 896.000 166.240 ;
        RECT 4.400 162.840 895.600 164.240 ;
        RECT 3.750 160.840 896.000 162.840 ;
        RECT 4.400 159.440 895.600 160.840 ;
        RECT 3.750 157.440 896.000 159.440 ;
        RECT 4.400 156.040 895.600 157.440 ;
        RECT 3.750 154.040 896.000 156.040 ;
        RECT 4.400 152.640 895.600 154.040 ;
        RECT 3.750 150.640 896.000 152.640 ;
        RECT 3.750 149.240 895.600 150.640 ;
        RECT 3.750 147.240 896.000 149.240 ;
        RECT 3.750 145.840 895.600 147.240 ;
        RECT 3.750 143.840 896.000 145.840 ;
        RECT 3.750 142.440 895.600 143.840 ;
        RECT 3.750 140.440 896.000 142.440 ;
        RECT 3.750 139.040 895.600 140.440 ;
        RECT 3.750 137.040 896.000 139.040 ;
        RECT 3.750 135.640 895.600 137.040 ;
        RECT 3.750 133.640 896.000 135.640 ;
        RECT 3.750 132.240 895.600 133.640 ;
        RECT 3.750 130.240 896.000 132.240 ;
        RECT 3.750 128.840 895.600 130.240 ;
        RECT 3.750 126.840 896.000 128.840 ;
        RECT 3.750 125.440 895.600 126.840 ;
        RECT 3.750 123.440 896.000 125.440 ;
        RECT 3.750 122.040 895.600 123.440 ;
        RECT 3.750 120.040 896.000 122.040 ;
        RECT 3.750 118.640 895.600 120.040 ;
        RECT 3.750 116.640 896.000 118.640 ;
        RECT 3.750 115.240 895.600 116.640 ;
        RECT 3.750 113.240 896.000 115.240 ;
        RECT 3.750 111.840 895.600 113.240 ;
        RECT 3.750 109.840 896.000 111.840 ;
        RECT 3.750 108.440 895.600 109.840 ;
        RECT 3.750 106.440 896.000 108.440 ;
        RECT 3.750 105.040 895.600 106.440 ;
        RECT 3.750 103.040 896.000 105.040 ;
        RECT 3.750 101.640 895.600 103.040 ;
        RECT 3.750 99.640 896.000 101.640 ;
        RECT 3.750 98.240 895.600 99.640 ;
        RECT 3.750 96.240 896.000 98.240 ;
        RECT 3.750 94.840 895.600 96.240 ;
        RECT 3.750 92.840 896.000 94.840 ;
        RECT 3.750 91.440 895.600 92.840 ;
        RECT 3.750 89.440 896.000 91.440 ;
        RECT 3.750 88.040 895.600 89.440 ;
        RECT 3.750 86.040 896.000 88.040 ;
        RECT 3.750 84.640 895.600 86.040 ;
        RECT 3.750 82.640 896.000 84.640 ;
        RECT 3.750 81.240 895.600 82.640 ;
        RECT 3.750 79.240 896.000 81.240 ;
        RECT 3.750 77.840 895.600 79.240 ;
        RECT 3.750 75.840 896.000 77.840 ;
        RECT 3.750 74.440 895.600 75.840 ;
        RECT 3.750 72.440 896.000 74.440 ;
        RECT 3.750 71.040 895.600 72.440 ;
        RECT 3.750 69.040 896.000 71.040 ;
        RECT 3.750 67.640 895.600 69.040 ;
        RECT 3.750 65.640 896.000 67.640 ;
        RECT 3.750 64.240 895.600 65.640 ;
        RECT 3.750 62.240 896.000 64.240 ;
        RECT 3.750 60.840 895.600 62.240 ;
        RECT 3.750 58.840 896.000 60.840 ;
        RECT 3.750 57.440 895.600 58.840 ;
        RECT 3.750 55.440 896.000 57.440 ;
        RECT 3.750 54.040 895.600 55.440 ;
        RECT 3.750 52.040 896.000 54.040 ;
        RECT 3.750 50.640 895.600 52.040 ;
        RECT 3.750 48.640 896.000 50.640 ;
        RECT 3.750 47.240 895.600 48.640 ;
        RECT 3.750 45.240 896.000 47.240 ;
        RECT 3.750 43.840 895.600 45.240 ;
        RECT 3.750 41.840 896.000 43.840 ;
        RECT 3.750 40.440 895.600 41.840 ;
        RECT 3.750 38.440 896.000 40.440 ;
        RECT 3.750 37.040 895.600 38.440 ;
        RECT 3.750 35.040 896.000 37.040 ;
        RECT 3.750 33.640 895.600 35.040 ;
        RECT 3.750 31.640 896.000 33.640 ;
        RECT 3.750 30.240 895.600 31.640 ;
        RECT 3.750 28.240 896.000 30.240 ;
        RECT 3.750 26.840 895.600 28.240 ;
        RECT 3.750 24.840 896.000 26.840 ;
        RECT 3.750 23.440 895.600 24.840 ;
        RECT 3.750 21.440 896.000 23.440 ;
        RECT 3.750 20.040 895.600 21.440 ;
        RECT 3.750 18.040 896.000 20.040 ;
        RECT 3.750 16.640 895.600 18.040 ;
        RECT 3.750 14.640 896.000 16.640 ;
        RECT 3.750 13.240 895.600 14.640 ;
        RECT 3.750 11.240 896.000 13.240 ;
        RECT 3.750 9.840 895.600 11.240 ;
        RECT 3.750 7.840 896.000 9.840 ;
        RECT 3.750 6.440 895.600 7.840 ;
        RECT 3.750 4.440 896.000 6.440 ;
        RECT 3.750 3.040 895.600 4.440 ;
        RECT 3.750 1.040 896.000 3.040 ;
        RECT 3.750 0.175 895.600 1.040 ;
      LAYER met4 ;
        RECT 3.975 15.135 20.640 882.465 ;
        RECT 23.040 15.135 23.940 882.465 ;
        RECT 26.340 15.135 174.240 882.465 ;
        RECT 176.640 15.135 177.540 882.465 ;
        RECT 179.940 15.135 327.840 882.465 ;
        RECT 330.240 15.135 331.140 882.465 ;
        RECT 333.540 15.135 481.440 882.465 ;
        RECT 483.840 15.135 484.740 882.465 ;
        RECT 487.140 15.135 635.040 882.465 ;
        RECT 637.440 15.135 638.340 882.465 ;
        RECT 640.740 15.135 788.640 882.465 ;
        RECT 791.040 15.135 791.940 882.465 ;
        RECT 794.340 15.135 889.345 882.465 ;
  END
END axi4lite_arbiter_top
END LIBRARY

